VERSION 5.8 ;
BUSBITCHARS "[]" ;
DIVIDERCHAR "/" ;
UNITS
    DATABASE MICRONS 1000 ;
END UNITS

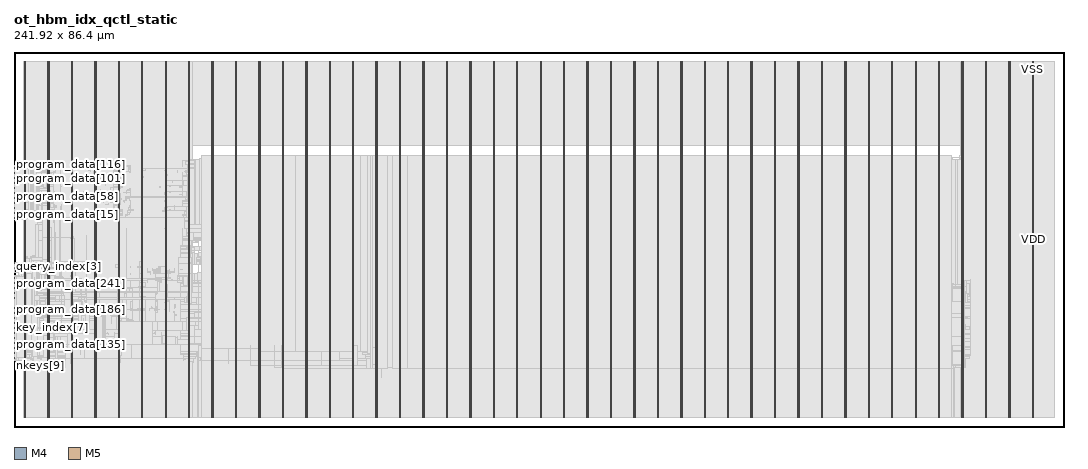
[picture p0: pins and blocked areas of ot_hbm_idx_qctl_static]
MACRO ot_hbm_idx_qctl_static
  FOREIGN ot_hbm_idx_qctl_static 0 0 ;
  CLASS BLOCK ;
  SIZE 241.92 BY 86.4 ;
  PIN clk_program
    DIRECTION INPUT ;
    USE SIGNAL ;
    PORT
      LAYER M4 ;
        RECT  0 21.936 0.084 21.96 ;
    END
  END clk_program
  PIN clk_program_mem
    DIRECTION INPUT ;
    USE SIGNAL ;
    PORT
      LAYER M4 ;
        RECT  0 22.032 0.084 22.056 ;
    END
  END clk_program_mem
  PIN fault
    DIRECTION OUTPUT ;
    USE SIGNAL ;
    PORT
      LAYER M4 ;
        RECT  0 22.128 0.084 22.152 ;
    END
  END fault
  PIN frame_start
    DIRECTION OUTPUT ;
    USE SIGNAL ;
    PORT
      LAYER M4 ;
        RECT  0 22.224 0.084 22.248 ;
    END
  END frame_start
  PIN key_index[0]
    DIRECTION OUTPUT ;
    USE SIGNAL ;
    PORT
      LAYER M4 ;
        RECT  0 22.32 0.084 22.344 ;
    END
  END key_index[0]
  PIN key_index[1]
    DIRECTION OUTPUT ;
    USE SIGNAL ;
    PORT
      LAYER M4 ;
        RECT  0 22.416 0.084 22.44 ;
    END
  END key_index[1]
  PIN key_index[2]
    DIRECTION OUTPUT ;
    USE SIGNAL ;
    PORT
      LAYER M4 ;
        RECT  0 22.512 0.084 22.536 ;
    END
  END key_index[2]
  PIN key_index[3]
    DIRECTION OUTPUT ;
    USE SIGNAL ;
    PORT
      LAYER M4 ;
        RECT  0 22.608 0.084 22.632 ;
    END
  END key_index[3]
  PIN key_index[4]
    DIRECTION OUTPUT ;
    USE SIGNAL ;
    PORT
      LAYER M4 ;
        RECT  0 22.704 0.084 22.728 ;
    END
  END key_index[4]
  PIN key_index[5]
    DIRECTION OUTPUT ;
    USE SIGNAL ;
    PORT
      LAYER M4 ;
        RECT  0 22.8 0.084 22.824 ;
    END
  END key_index[5]
  PIN key_index[6]
    DIRECTION OUTPUT ;
    USE SIGNAL ;
    PORT
      LAYER M4 ;
        RECT  0 22.896 0.084 22.92 ;
    END
  END key_index[6]
  PIN key_index[7]
    DIRECTION OUTPUT ;
    USE SIGNAL ;
    PORT
      LAYER M4 ;
        RECT  0 22.992 0.084 23.016 ;
    END
  END key_index[7]
  PIN key_slot
    DIRECTION OUTPUT ;
    USE SIGNAL ;
    PORT
      LAYER M4 ;
        RECT  0 23.088 0.084 23.112 ;
    END
  END key_slot
  PIN length[0]
    DIRECTION INPUT ;
    USE SIGNAL ;
    PORT
      LAYER M4 ;
        RECT  0 23.184 0.084 23.208 ;
    END
  END length[0]
  PIN length[10]
    DIRECTION INPUT ;
    USE SIGNAL ;
    PORT
      LAYER M4 ;
        RECT  0 24.144 0.084 24.168 ;
    END
  END length[10]
  PIN length[11]
    DIRECTION INPUT ;
    USE SIGNAL ;
    PORT
      LAYER M4 ;
        RECT  0 24.24 0.084 24.264 ;
    END
  END length[11]
  PIN length[1]
    DIRECTION INPUT ;
    USE SIGNAL ;
    PORT
      LAYER M4 ;
        RECT  0 23.28 0.084 23.304 ;
    END
  END length[1]
  PIN length[2]
    DIRECTION INPUT ;
    USE SIGNAL ;
    PORT
      LAYER M4 ;
        RECT  0 23.376 0.084 23.4 ;
    END
  END length[2]
  PIN length[3]
    DIRECTION INPUT ;
    USE SIGNAL ;
    PORT
      LAYER M4 ;
        RECT  0 23.472 0.084 23.496 ;
    END
  END length[3]
  PIN length[4]
    DIRECTION INPUT ;
    USE SIGNAL ;
    PORT
      LAYER M4 ;
        RECT  0 23.568 0.084 23.592 ;
    END
  END length[4]
  PIN length[5]
    DIRECTION INPUT ;
    USE SIGNAL ;
    PORT
      LAYER M4 ;
        RECT  0 23.664 0.084 23.688 ;
    END
  END length[5]
  PIN length[6]
    DIRECTION INPUT ;
    USE SIGNAL ;
    PORT
      LAYER M4 ;
        RECT  0 23.76 0.084 23.784 ;
    END
  END length[6]
  PIN length[7]
    DIRECTION INPUT ;
    USE SIGNAL ;
    PORT
      LAYER M4 ;
        RECT  0 23.856 0.084 23.88 ;
    END
  END length[7]
  PIN length[8]
    DIRECTION INPUT ;
    USE SIGNAL ;
    PORT
      LAYER M4 ;
        RECT  0 23.952 0.084 23.976 ;
    END
  END length[8]
  PIN length[9]
    DIRECTION INPUT ;
    USE SIGNAL ;
    PORT
      LAYER M4 ;
        RECT  0 24.048 0.084 24.072 ;
    END
  END length[9]
  PIN nkeys[0]
    DIRECTION INPUT ;
    USE SIGNAL ;
    PORT
      LAYER M4 ;
        RECT  0 24.336 0.084 24.36 ;
    END
  END nkeys[0]
  PIN nkeys[10]
    DIRECTION INPUT ;
    USE SIGNAL ;
    PORT
      LAYER M4 ;
        RECT  0 16.08 0.084 16.104 ;
    END
  END nkeys[10]
  PIN nkeys[11]
    DIRECTION INPUT ;
    USE SIGNAL ;
    PORT
      LAYER M4 ;
        RECT  0 16.176 0.084 16.2 ;
    END
  END nkeys[11]
  PIN nkeys[12]
    DIRECTION INPUT ;
    USE SIGNAL ;
    PORT
      LAYER M4 ;
        RECT  0 16.272 0.084 16.296 ;
    END
  END nkeys[12]
  PIN nkeys[13]
    DIRECTION INPUT ;
    USE SIGNAL ;
    PORT
      LAYER M4 ;
        RECT  0 16.368 0.084 16.392 ;
    END
  END nkeys[13]
  PIN nkeys[1]
    DIRECTION INPUT ;
    USE SIGNAL ;
    PORT
      LAYER M4 ;
        RECT  0 24.432 0.084 24.456 ;
    END
  END nkeys[1]
  PIN nkeys[2]
    DIRECTION INPUT ;
    USE SIGNAL ;
    PORT
      LAYER M4 ;
        RECT  0 24.528 0.084 24.552 ;
    END
  END nkeys[2]
  PIN nkeys[3]
    DIRECTION INPUT ;
    USE SIGNAL ;
    PORT
      LAYER M4 ;
        RECT  0 24.624 0.084 24.648 ;
    END
  END nkeys[3]
  PIN nkeys[4]
    DIRECTION INPUT ;
    USE SIGNAL ;
    PORT
      LAYER M4 ;
        RECT  0 24.72 0.084 24.744 ;
    END
  END nkeys[4]
  PIN nkeys[5]
    DIRECTION INPUT ;
    USE SIGNAL ;
    PORT
      LAYER M4 ;
        RECT  0 24.816 0.084 24.84 ;
    END
  END nkeys[5]
  PIN nkeys[6]
    DIRECTION INPUT ;
    USE SIGNAL ;
    PORT
      LAYER M4 ;
        RECT  0 24.912 0.084 24.936 ;
    END
  END nkeys[6]
  PIN nkeys[7]
    DIRECTION INPUT ;
    USE SIGNAL ;
    PORT
      LAYER M4 ;
        RECT  0 15.792 0.084 15.816 ;
    END
  END nkeys[7]
  PIN nkeys[8]
    DIRECTION INPUT ;
    USE SIGNAL ;
    PORT
      LAYER M4 ;
        RECT  0 15.888 0.084 15.912 ;
    END
  END nkeys[8]
  PIN nkeys[9]
    DIRECTION INPUT ;
    USE SIGNAL ;
    PORT
      LAYER M4 ;
        RECT  0 15.984 0.084 16.008 ;
    END
  END nkeys[9]
  PIN nq[0]
    DIRECTION OUTPUT ;
    USE SIGNAL ;
    PORT
      LAYER M4 ;
        RECT  0 16.464 0.084 16.488 ;
    END
  END nq[0]
  PIN nq[10]
    DIRECTION OUTPUT ;
    USE SIGNAL ;
    PORT
      LAYER M4 ;
        RECT  0 17.424 0.084 17.448 ;
    END
  END nq[10]
  PIN nq[11]
    DIRECTION OUTPUT ;
    USE SIGNAL ;
    PORT
      LAYER M4 ;
        RECT  0 17.52 0.084 17.544 ;
    END
  END nq[11]
  PIN nq[1]
    DIRECTION OUTPUT ;
    USE SIGNAL ;
    PORT
      LAYER M4 ;
        RECT  0 16.56 0.084 16.584 ;
    END
  END nq[1]
  PIN nq[2]
    DIRECTION OUTPUT ;
    USE SIGNAL ;
    PORT
      LAYER M4 ;
        RECT  0 16.656 0.084 16.68 ;
    END
  END nq[2]
  PIN nq[3]
    DIRECTION OUTPUT ;
    USE SIGNAL ;
    PORT
      LAYER M4 ;
        RECT  0 16.752 0.084 16.776 ;
    END
  END nq[3]
  PIN nq[4]
    DIRECTION OUTPUT ;
    USE SIGNAL ;
    PORT
      LAYER M4 ;
        RECT  0 16.848 0.084 16.872 ;
    END
  END nq[4]
  PIN nq[5]
    DIRECTION OUTPUT ;
    USE SIGNAL ;
    PORT
      LAYER M4 ;
        RECT  0 16.944 0.084 16.968 ;
    END
  END nq[5]
  PIN nq[6]
    DIRECTION OUTPUT ;
    USE SIGNAL ;
    PORT
      LAYER M4 ;
        RECT  0 17.04 0.084 17.064 ;
    END
  END nq[6]
  PIN nq[7]
    DIRECTION OUTPUT ;
    USE SIGNAL ;
    PORT
      LAYER M4 ;
        RECT  0 17.136 0.084 17.16 ;
    END
  END nq[7]
  PIN nq[8]
    DIRECTION OUTPUT ;
    USE SIGNAL ;
    PORT
      LAYER M4 ;
        RECT  0 17.232 0.084 17.256 ;
    END
  END nq[8]
  PIN nq[9]
    DIRECTION OUTPUT ;
    USE SIGNAL ;
    PORT
      LAYER M4 ;
        RECT  0 17.328 0.084 17.352 ;
    END
  END nq[9]
  PIN program_addr[0]
    DIRECTION INPUT ;
    USE SIGNAL ;
    PORT
      LAYER M4 ;
        RECT  0 17.616 0.084 17.64 ;
    END
  END program_addr[0]
  PIN program_addr[1]
    DIRECTION INPUT ;
    USE SIGNAL ;
    PORT
      LAYER M4 ;
        RECT  0 17.712 0.084 17.736 ;
    END
  END program_addr[1]
  PIN program_addr[2]
    DIRECTION INPUT ;
    USE SIGNAL ;
    PORT
      LAYER M4 ;
        RECT  0 17.808 0.084 17.832 ;
    END
  END program_addr[2]
  PIN program_addr[3]
    DIRECTION INPUT ;
    USE SIGNAL ;
    PORT
      LAYER M4 ;
        RECT  0 17.904 0.084 17.928 ;
    END
  END program_addr[3]
  PIN program_addr[4]
    DIRECTION INPUT ;
    USE SIGNAL ;
    PORT
      LAYER M4 ;
        RECT  0 18 0.084 18.024 ;
    END
  END program_addr[4]
  PIN program_addr[5]
    DIRECTION INPUT ;
    USE SIGNAL ;
    PORT
      LAYER M4 ;
        RECT  0 18.096 0.084 18.12 ;
    END
  END program_addr[5]
  PIN program_addr[6]
    DIRECTION INPUT ;
    USE SIGNAL ;
    PORT
      LAYER M4 ;
        RECT  0 18.192 0.084 18.216 ;
    END
  END program_addr[6]
  PIN program_addr[7]
    DIRECTION INPUT ;
    USE SIGNAL ;
    PORT
      LAYER M4 ;
        RECT  0 18.288 0.084 18.312 ;
    END
  END program_addr[7]
  PIN program_data[0]
    DIRECTION INPUT ;
    USE SIGNAL ;
    PORT
      LAYER M4 ;
        RECT  0 18.384 0.084 18.408 ;
    END
  END program_data[0]
  PIN program_data[100]
    DIRECTION INPUT ;
    USE SIGNAL ;
    PORT
      LAYER M4 ;
        RECT  0 57.168 0.084 57.192 ;
    END
  END program_data[100]
  PIN program_data[101]
    DIRECTION INPUT ;
    USE SIGNAL ;
    PORT
      LAYER M4 ;
        RECT  0 57.264 0.084 57.288 ;
    END
  END program_data[101]
  PIN program_data[102]
    DIRECTION INPUT ;
    USE SIGNAL ;
    PORT
      LAYER M4 ;
        RECT  0 57.36 0.084 57.384 ;
    END
  END program_data[102]
  PIN program_data[103]
    DIRECTION INPUT ;
    USE SIGNAL ;
    PORT
      LAYER M4 ;
        RECT  0 57.456 0.084 57.48 ;
    END
  END program_data[103]
  PIN program_data[104]
    DIRECTION INPUT ;
    USE SIGNAL ;
    PORT
      LAYER M4 ;
        RECT  0 57.552 0.084 57.576 ;
    END
  END program_data[104]
  PIN program_data[105]
    DIRECTION INPUT ;
    USE SIGNAL ;
    PORT
      LAYER M4 ;
        RECT  0 57.648 0.084 57.672 ;
    END
  END program_data[105]
  PIN program_data[106]
    DIRECTION INPUT ;
    USE SIGNAL ;
    PORT
      LAYER M4 ;
        RECT  0 57.744 0.084 57.768 ;
    END
  END program_data[106]
  PIN program_data[107]
    DIRECTION INPUT ;
    USE SIGNAL ;
    PORT
      LAYER M4 ;
        RECT  0 57.84 0.084 57.864 ;
    END
  END program_data[107]
  PIN program_data[108]
    DIRECTION INPUT ;
    USE SIGNAL ;
    PORT
      LAYER M4 ;
        RECT  0 57.936 0.084 57.96 ;
    END
  END program_data[108]
  PIN program_data[109]
    DIRECTION INPUT ;
    USE SIGNAL ;
    PORT
      LAYER M4 ;
        RECT  0 58.032 0.084 58.056 ;
    END
  END program_data[109]
  PIN program_data[10]
    DIRECTION INPUT ;
    USE SIGNAL ;
    PORT
      LAYER M4 ;
        RECT  0 48.528 0.084 48.552 ;
    END
  END program_data[10]
  PIN program_data[110]
    DIRECTION INPUT ;
    USE SIGNAL ;
    PORT
      LAYER M4 ;
        RECT  0 58.128 0.084 58.152 ;
    END
  END program_data[110]
  PIN program_data[111]
    DIRECTION INPUT ;
    USE SIGNAL ;
    PORT
      LAYER M4 ;
        RECT  0 58.224 0.084 58.248 ;
    END
  END program_data[111]
  PIN program_data[112]
    DIRECTION INPUT ;
    USE SIGNAL ;
    PORT
      LAYER M4 ;
        RECT  0 58.32 0.084 58.344 ;
    END
  END program_data[112]
  PIN program_data[113]
    DIRECTION INPUT ;
    USE SIGNAL ;
    PORT
      LAYER M4 ;
        RECT  0 58.416 0.084 58.44 ;
    END
  END program_data[113]
  PIN program_data[114]
    DIRECTION INPUT ;
    USE SIGNAL ;
    PORT
      LAYER M4 ;
        RECT  0 58.512 0.084 58.536 ;
    END
  END program_data[114]
  PIN program_data[115]
    DIRECTION INPUT ;
    USE SIGNAL ;
    PORT
      LAYER M4 ;
        RECT  0 58.608 0.084 58.632 ;
    END
  END program_data[115]
  PIN program_data[116]
    DIRECTION INPUT ;
    USE SIGNAL ;
    PORT
      LAYER M4 ;
        RECT  0 58.704 0.084 58.728 ;
    END
  END program_data[116]
  PIN program_data[117]
    DIRECTION INPUT ;
    USE SIGNAL ;
    PORT
      LAYER M4 ;
        RECT  0 58.8 0.084 58.824 ;
    END
  END program_data[117]
  PIN program_data[118]
    DIRECTION INPUT ;
    USE SIGNAL ;
    PORT
      LAYER M4 ;
        RECT  0 58.896 0.084 58.92 ;
    END
  END program_data[118]
  PIN program_data[119]
    DIRECTION INPUT ;
    USE SIGNAL ;
    PORT
      LAYER M4 ;
        RECT  0 58.992 0.084 59.016 ;
    END
  END program_data[119]
  PIN program_data[11]
    DIRECTION INPUT ;
    USE SIGNAL ;
    PORT
      LAYER M4 ;
        RECT  0 48.624 0.084 48.648 ;
    END
  END program_data[11]
  PIN program_data[120]
    DIRECTION INPUT ;
    USE SIGNAL ;
    PORT
      LAYER M4 ;
        RECT  0 59.088 0.084 59.112 ;
    END
  END program_data[120]
  PIN program_data[121]
    DIRECTION INPUT ;
    USE SIGNAL ;
    PORT
      LAYER M4 ;
        RECT  0 59.184 0.084 59.208 ;
    END
  END program_data[121]
  PIN program_data[122]
    DIRECTION INPUT ;
    USE SIGNAL ;
    PORT
      LAYER M4 ;
        RECT  0 59.28 0.084 59.304 ;
    END
  END program_data[122]
  PIN program_data[123]
    DIRECTION INPUT ;
    USE SIGNAL ;
    PORT
      LAYER M4 ;
        RECT  0 59.376 0.084 59.4 ;
    END
  END program_data[123]
  PIN program_data[124]
    DIRECTION INPUT ;
    USE SIGNAL ;
    PORT
      LAYER M4 ;
        RECT  0 59.472 0.084 59.496 ;
    END
  END program_data[124]
  PIN program_data[125]
    DIRECTION INPUT ;
    USE SIGNAL ;
    PORT
      LAYER M4 ;
        RECT  0 59.568 0.084 59.592 ;
    END
  END program_data[125]
  PIN program_data[126]
    DIRECTION INPUT ;
    USE SIGNAL ;
    PORT
      LAYER M4 ;
        RECT  0 59.664 0.084 59.688 ;
    END
  END program_data[126]
  PIN program_data[127]
    DIRECTION INPUT ;
    USE SIGNAL ;
    PORT
      LAYER M4 ;
        RECT  0 59.76 0.084 59.784 ;
    END
  END program_data[127]
  PIN program_data[128]
    DIRECTION INPUT ;
    USE SIGNAL ;
    PORT
      LAYER M4 ;
        RECT  0 59.856 0.084 59.88 ;
    END
  END program_data[128]
  PIN program_data[129]
    DIRECTION INPUT ;
    USE SIGNAL ;
    PORT
      LAYER M4 ;
        RECT  0 59.952 0.084 59.976 ;
    END
  END program_data[129]
  PIN program_data[12]
    DIRECTION INPUT ;
    USE SIGNAL ;
    PORT
      LAYER M4 ;
        RECT  0 48.72 0.084 48.744 ;
    END
  END program_data[12]
  PIN program_data[130]
    DIRECTION INPUT ;
    USE SIGNAL ;
    PORT
      LAYER M4 ;
        RECT  0 60.048 0.084 60.072 ;
    END
  END program_data[130]
  PIN program_data[131]
    DIRECTION INPUT ;
    USE SIGNAL ;
    PORT
      LAYER M4 ;
        RECT  0 60.144 0.084 60.168 ;
    END
  END program_data[131]
  PIN program_data[132]
    DIRECTION INPUT ;
    USE SIGNAL ;
    PORT
      LAYER M4 ;
        RECT  0 60.24 0.084 60.264 ;
    END
  END program_data[132]
  PIN program_data[133]
    DIRECTION INPUT ;
    USE SIGNAL ;
    PORT
      LAYER M4 ;
        RECT  0 18.864 0.084 18.888 ;
    END
  END program_data[133]
  PIN program_data[134]
    DIRECTION INPUT ;
    USE SIGNAL ;
    PORT
      LAYER M4 ;
        RECT  0 18.96 0.084 18.984 ;
    END
  END program_data[134]
  PIN program_data[135]
    DIRECTION INPUT ;
    USE SIGNAL ;
    PORT
      LAYER M4 ;
        RECT  0 19.056 0.084 19.08 ;
    END
  END program_data[135]
  PIN program_data[136]
    DIRECTION INPUT ;
    USE SIGNAL ;
    PORT
      LAYER M4 ;
        RECT  0 19.152 0.084 19.176 ;
    END
  END program_data[136]
  PIN program_data[137]
    DIRECTION INPUT ;
    USE SIGNAL ;
    PORT
      LAYER M4 ;
        RECT  0 19.248 0.084 19.272 ;
    END
  END program_data[137]
  PIN program_data[138]
    DIRECTION INPUT ;
    USE SIGNAL ;
    PORT
      LAYER M4 ;
        RECT  0 19.344 0.084 19.368 ;
    END
  END program_data[138]
  PIN program_data[139]
    DIRECTION INPUT ;
    USE SIGNAL ;
    PORT
      LAYER M4 ;
        RECT  0 19.44 0.084 19.464 ;
    END
  END program_data[139]
  PIN program_data[13]
    DIRECTION INPUT ;
    USE SIGNAL ;
    PORT
      LAYER M4 ;
        RECT  0 48.816 0.084 48.84 ;
    END
  END program_data[13]
  PIN program_data[140]
    DIRECTION INPUT ;
    USE SIGNAL ;
    PORT
      LAYER M4 ;
        RECT  0 19.536 0.084 19.56 ;
    END
  END program_data[140]
  PIN program_data[141]
    DIRECTION INPUT ;
    USE SIGNAL ;
    PORT
      LAYER M4 ;
        RECT  0 19.632 0.084 19.656 ;
    END
  END program_data[141]
  PIN program_data[142]
    DIRECTION INPUT ;
    USE SIGNAL ;
    PORT
      LAYER M4 ;
        RECT  0 19.728 0.084 19.752 ;
    END
  END program_data[142]
  PIN program_data[143]
    DIRECTION INPUT ;
    USE SIGNAL ;
    PORT
      LAYER M4 ;
        RECT  0 19.824 0.084 19.848 ;
    END
  END program_data[143]
  PIN program_data[144]
    DIRECTION INPUT ;
    USE SIGNAL ;
    PORT
      LAYER M4 ;
        RECT  0 19.92 0.084 19.944 ;
    END
  END program_data[144]
  PIN program_data[145]
    DIRECTION INPUT ;
    USE SIGNAL ;
    PORT
      LAYER M4 ;
        RECT  0 20.016 0.084 20.04 ;
    END
  END program_data[145]
  PIN program_data[146]
    DIRECTION INPUT ;
    USE SIGNAL ;
    PORT
      LAYER M4 ;
        RECT  0 20.112 0.084 20.136 ;
    END
  END program_data[146]
  PIN program_data[147]
    DIRECTION INPUT ;
    USE SIGNAL ;
    PORT
      LAYER M4 ;
        RECT  0 20.208 0.084 20.232 ;
    END
  END program_data[147]
  PIN program_data[148]
    DIRECTION INPUT ;
    USE SIGNAL ;
    PORT
      LAYER M4 ;
        RECT  0 20.304 0.084 20.328 ;
    END
  END program_data[148]
  PIN program_data[149]
    DIRECTION INPUT ;
    USE SIGNAL ;
    PORT
      LAYER M4 ;
        RECT  0 20.4 0.084 20.424 ;
    END
  END program_data[149]
  PIN program_data[14]
    DIRECTION INPUT ;
    USE SIGNAL ;
    PORT
      LAYER M4 ;
        RECT  0 48.912 0.084 48.936 ;
    END
  END program_data[14]
  PIN program_data[150]
    DIRECTION INPUT ;
    USE SIGNAL ;
    PORT
      LAYER M4 ;
        RECT  0 20.496 0.084 20.52 ;
    END
  END program_data[150]
  PIN program_data[151]
    DIRECTION INPUT ;
    USE SIGNAL ;
    PORT
      LAYER M4 ;
        RECT  0 20.592 0.084 20.616 ;
    END
  END program_data[151]
  PIN program_data[152]
    DIRECTION INPUT ;
    USE SIGNAL ;
    PORT
      LAYER M4 ;
        RECT  0 20.688 0.084 20.712 ;
    END
  END program_data[152]
  PIN program_data[153]
    DIRECTION INPUT ;
    USE SIGNAL ;
    PORT
      LAYER M4 ;
        RECT  0 20.784 0.084 20.808 ;
    END
  END program_data[153]
  PIN program_data[154]
    DIRECTION INPUT ;
    USE SIGNAL ;
    PORT
      LAYER M4 ;
        RECT  0 20.88 0.084 20.904 ;
    END
  END program_data[154]
  PIN program_data[155]
    DIRECTION INPUT ;
    USE SIGNAL ;
    PORT
      LAYER M4 ;
        RECT  0 20.976 0.084 21 ;
    END
  END program_data[155]
  PIN program_data[156]
    DIRECTION INPUT ;
    USE SIGNAL ;
    PORT
      LAYER M4 ;
        RECT  0 21.072 0.084 21.096 ;
    END
  END program_data[156]
  PIN program_data[157]
    DIRECTION INPUT ;
    USE SIGNAL ;
    PORT
      LAYER M4 ;
        RECT  0 21.168 0.084 21.192 ;
    END
  END program_data[157]
  PIN program_data[158]
    DIRECTION INPUT ;
    USE SIGNAL ;
    PORT
      LAYER M4 ;
        RECT  0 21.264 0.084 21.288 ;
    END
  END program_data[158]
  PIN program_data[159]
    DIRECTION INPUT ;
    USE SIGNAL ;
    PORT
      LAYER M4 ;
        RECT  0 21.36 0.084 21.384 ;
    END
  END program_data[159]
  PIN program_data[15]
    DIRECTION INPUT ;
    USE SIGNAL ;
    PORT
      LAYER M4 ;
        RECT  0 49.008 0.084 49.032 ;
    END
  END program_data[15]
  PIN program_data[160]
    DIRECTION INPUT ;
    USE SIGNAL ;
    PORT
      LAYER M4 ;
        RECT  0 21.456 0.084 21.48 ;
    END
  END program_data[160]
  PIN program_data[161]
    DIRECTION INPUT ;
    USE SIGNAL ;
    PORT
      LAYER M4 ;
        RECT  0 21.552 0.084 21.576 ;
    END
  END program_data[161]
  PIN program_data[162]
    DIRECTION INPUT ;
    USE SIGNAL ;
    PORT
      LAYER M4 ;
        RECT  0 21.648 0.084 21.672 ;
    END
  END program_data[162]
  PIN program_data[163]
    DIRECTION INPUT ;
    USE SIGNAL ;
    PORT
      LAYER M4 ;
        RECT  0 21.744 0.084 21.768 ;
    END
  END program_data[163]
  PIN program_data[164]
    DIRECTION INPUT ;
    USE SIGNAL ;
    PORT
      LAYER M4 ;
        RECT  0 21.84 0.084 21.864 ;
    END
  END program_data[164]
  PIN program_data[165]
    DIRECTION INPUT ;
    USE SIGNAL ;
    PORT
      LAYER M4 ;
        RECT  0 25.008 0.084 25.032 ;
    END
  END program_data[165]
  PIN program_data[166]
    DIRECTION INPUT ;
    USE SIGNAL ;
    PORT
      LAYER M4 ;
        RECT  0 25.104 0.084 25.128 ;
    END
  END program_data[166]
  PIN program_data[167]
    DIRECTION INPUT ;
    USE SIGNAL ;
    PORT
      LAYER M4 ;
        RECT  0 25.2 0.084 25.224 ;
    END
  END program_data[167]
  PIN program_data[168]
    DIRECTION INPUT ;
    USE SIGNAL ;
    PORT
      LAYER M4 ;
        RECT  0 25.296 0.084 25.32 ;
    END
  END program_data[168]
  PIN program_data[169]
    DIRECTION INPUT ;
    USE SIGNAL ;
    PORT
      LAYER M4 ;
        RECT  0 25.392 0.084 25.416 ;
    END
  END program_data[169]
  PIN program_data[16]
    DIRECTION INPUT ;
    USE SIGNAL ;
    PORT
      LAYER M4 ;
        RECT  0 49.104 0.084 49.128 ;
    END
  END program_data[16]
  PIN program_data[170]
    DIRECTION INPUT ;
    USE SIGNAL ;
    PORT
      LAYER M4 ;
        RECT  0 25.488 0.084 25.512 ;
    END
  END program_data[170]
  PIN program_data[171]
    DIRECTION INPUT ;
    USE SIGNAL ;
    PORT
      LAYER M4 ;
        RECT  0 25.584 0.084 25.608 ;
    END
  END program_data[171]
  PIN program_data[172]
    DIRECTION INPUT ;
    USE SIGNAL ;
    PORT
      LAYER M4 ;
        RECT  0 25.68 0.084 25.704 ;
    END
  END program_data[172]
  PIN program_data[173]
    DIRECTION INPUT ;
    USE SIGNAL ;
    PORT
      LAYER M4 ;
        RECT  0 25.776 0.084 25.8 ;
    END
  END program_data[173]
  PIN program_data[174]
    DIRECTION INPUT ;
    USE SIGNAL ;
    PORT
      LAYER M4 ;
        RECT  0 25.872 0.084 25.896 ;
    END
  END program_data[174]
  PIN program_data[175]
    DIRECTION INPUT ;
    USE SIGNAL ;
    PORT
      LAYER M4 ;
        RECT  0 25.968 0.084 25.992 ;
    END
  END program_data[175]
  PIN program_data[176]
    DIRECTION INPUT ;
    USE SIGNAL ;
    PORT
      LAYER M4 ;
        RECT  0 26.064 0.084 26.088 ;
    END
  END program_data[176]
  PIN program_data[177]
    DIRECTION INPUT ;
    USE SIGNAL ;
    PORT
      LAYER M4 ;
        RECT  0 26.16 0.084 26.184 ;
    END
  END program_data[177]
  PIN program_data[178]
    DIRECTION INPUT ;
    USE SIGNAL ;
    PORT
      LAYER M4 ;
        RECT  0 26.256 0.084 26.28 ;
    END
  END program_data[178]
  PIN program_data[179]
    DIRECTION INPUT ;
    USE SIGNAL ;
    PORT
      LAYER M4 ;
        RECT  0 26.352 0.084 26.376 ;
    END
  END program_data[179]
  PIN program_data[17]
    DIRECTION INPUT ;
    USE SIGNAL ;
    PORT
      LAYER M4 ;
        RECT  0 49.2 0.084 49.224 ;
    END
  END program_data[17]
  PIN program_data[180]
    DIRECTION INPUT ;
    USE SIGNAL ;
    PORT
      LAYER M4 ;
        RECT  0 26.448 0.084 26.472 ;
    END
  END program_data[180]
  PIN program_data[181]
    DIRECTION INPUT ;
    USE SIGNAL ;
    PORT
      LAYER M4 ;
        RECT  0 26.544 0.084 26.568 ;
    END
  END program_data[181]
  PIN program_data[182]
    DIRECTION INPUT ;
    USE SIGNAL ;
    PORT
      LAYER M4 ;
        RECT  0 26.64 0.084 26.664 ;
    END
  END program_data[182]
  PIN program_data[183]
    DIRECTION INPUT ;
    USE SIGNAL ;
    PORT
      LAYER M4 ;
        RECT  0 26.736 0.084 26.76 ;
    END
  END program_data[183]
  PIN program_data[184]
    DIRECTION INPUT ;
    USE SIGNAL ;
    PORT
      LAYER M4 ;
        RECT  0 26.832 0.084 26.856 ;
    END
  END program_data[184]
  PIN program_data[185]
    DIRECTION INPUT ;
    USE SIGNAL ;
    PORT
      LAYER M4 ;
        RECT  0 26.928 0.084 26.952 ;
    END
  END program_data[185]
  PIN program_data[186]
    DIRECTION INPUT ;
    USE SIGNAL ;
    PORT
      LAYER M4 ;
        RECT  0 27.024 0.084 27.048 ;
    END
  END program_data[186]
  PIN program_data[187]
    DIRECTION INPUT ;
    USE SIGNAL ;
    PORT
      LAYER M4 ;
        RECT  0 27.12 0.084 27.144 ;
    END
  END program_data[187]
  PIN program_data[188]
    DIRECTION INPUT ;
    USE SIGNAL ;
    PORT
      LAYER M4 ;
        RECT  0 27.216 0.084 27.24 ;
    END
  END program_data[188]
  PIN program_data[189]
    DIRECTION INPUT ;
    USE SIGNAL ;
    PORT
      LAYER M4 ;
        RECT  0 27.312 0.084 27.336 ;
    END
  END program_data[189]
  PIN program_data[18]
    DIRECTION INPUT ;
    USE SIGNAL ;
    PORT
      LAYER M4 ;
        RECT  0 49.296 0.084 49.32 ;
    END
  END program_data[18]
  PIN program_data[190]
    DIRECTION INPUT ;
    USE SIGNAL ;
    PORT
      LAYER M4 ;
        RECT  0 27.408 0.084 27.432 ;
    END
  END program_data[190]
  PIN program_data[191]
    DIRECTION INPUT ;
    USE SIGNAL ;
    PORT
      LAYER M4 ;
        RECT  0 27.504 0.084 27.528 ;
    END
  END program_data[191]
  PIN program_data[192]
    DIRECTION INPUT ;
    USE SIGNAL ;
    PORT
      LAYER M4 ;
        RECT  0 27.6 0.084 27.624 ;
    END
  END program_data[192]
  PIN program_data[193]
    DIRECTION INPUT ;
    USE SIGNAL ;
    PORT
      LAYER M4 ;
        RECT  0 27.696 0.084 27.72 ;
    END
  END program_data[193]
  PIN program_data[194]
    DIRECTION INPUT ;
    USE SIGNAL ;
    PORT
      LAYER M4 ;
        RECT  0 27.792 0.084 27.816 ;
    END
  END program_data[194]
  PIN program_data[195]
    DIRECTION INPUT ;
    USE SIGNAL ;
    PORT
      LAYER M4 ;
        RECT  0 27.888 0.084 27.912 ;
    END
  END program_data[195]
  PIN program_data[196]
    DIRECTION INPUT ;
    USE SIGNAL ;
    PORT
      LAYER M4 ;
        RECT  0 27.984 0.084 28.008 ;
    END
  END program_data[196]
  PIN program_data[197]
    DIRECTION INPUT ;
    USE SIGNAL ;
    PORT
      LAYER M4 ;
        RECT  0 28.848 0.084 28.872 ;
    END
  END program_data[197]
  PIN program_data[198]
    DIRECTION INPUT ;
    USE SIGNAL ;
    PORT
      LAYER M4 ;
        RECT  0 28.944 0.084 28.968 ;
    END
  END program_data[198]
  PIN program_data[199]
    DIRECTION INPUT ;
    USE SIGNAL ;
    PORT
      LAYER M4 ;
        RECT  0 29.04 0.084 29.064 ;
    END
  END program_data[199]
  PIN program_data[19]
    DIRECTION INPUT ;
    USE SIGNAL ;
    PORT
      LAYER M4 ;
        RECT  0 49.392 0.084 49.416 ;
    END
  END program_data[19]
  PIN program_data[1]
    DIRECTION INPUT ;
    USE SIGNAL ;
    PORT
      LAYER M4 ;
        RECT  0 18.48 0.084 18.504 ;
    END
  END program_data[1]
  PIN program_data[200]
    DIRECTION INPUT ;
    USE SIGNAL ;
    PORT
      LAYER M4 ;
        RECT  0 29.136 0.084 29.16 ;
    END
  END program_data[200]
  PIN program_data[201]
    DIRECTION INPUT ;
    USE SIGNAL ;
    PORT
      LAYER M4 ;
        RECT  0 29.232 0.084 29.256 ;
    END
  END program_data[201]
  PIN program_data[202]
    DIRECTION INPUT ;
    USE SIGNAL ;
    PORT
      LAYER M4 ;
        RECT  0 29.328 0.084 29.352 ;
    END
  END program_data[202]
  PIN program_data[203]
    DIRECTION INPUT ;
    USE SIGNAL ;
    PORT
      LAYER M4 ;
        RECT  0 29.424 0.084 29.448 ;
    END
  END program_data[203]
  PIN program_data[204]
    DIRECTION INPUT ;
    USE SIGNAL ;
    PORT
      LAYER M4 ;
        RECT  0 29.52 0.084 29.544 ;
    END
  END program_data[204]
  PIN program_data[205]
    DIRECTION INPUT ;
    USE SIGNAL ;
    PORT
      LAYER M4 ;
        RECT  0 29.616 0.084 29.64 ;
    END
  END program_data[205]
  PIN program_data[206]
    DIRECTION INPUT ;
    USE SIGNAL ;
    PORT
      LAYER M4 ;
        RECT  0 29.712 0.084 29.736 ;
    END
  END program_data[206]
  PIN program_data[207]
    DIRECTION INPUT ;
    USE SIGNAL ;
    PORT
      LAYER M4 ;
        RECT  0 29.808 0.084 29.832 ;
    END
  END program_data[207]
  PIN program_data[208]
    DIRECTION INPUT ;
    USE SIGNAL ;
    PORT
      LAYER M4 ;
        RECT  0 29.904 0.084 29.928 ;
    END
  END program_data[208]
  PIN program_data[209]
    DIRECTION INPUT ;
    USE SIGNAL ;
    PORT
      LAYER M4 ;
        RECT  0 30 0.084 30.024 ;
    END
  END program_data[209]
  PIN program_data[20]
    DIRECTION INPUT ;
    USE SIGNAL ;
    PORT
      LAYER M4 ;
        RECT  0 49.488 0.084 49.512 ;
    END
  END program_data[20]
  PIN program_data[210]
    DIRECTION INPUT ;
    USE SIGNAL ;
    PORT
      LAYER M4 ;
        RECT  0 30.096 0.084 30.12 ;
    END
  END program_data[210]
  PIN program_data[211]
    DIRECTION INPUT ;
    USE SIGNAL ;
    PORT
      LAYER M4 ;
        RECT  0 30.192 0.084 30.216 ;
    END
  END program_data[211]
  PIN program_data[212]
    DIRECTION INPUT ;
    USE SIGNAL ;
    PORT
      LAYER M4 ;
        RECT  0 30.288 0.084 30.312 ;
    END
  END program_data[212]
  PIN program_data[213]
    DIRECTION INPUT ;
    USE SIGNAL ;
    PORT
      LAYER M4 ;
        RECT  0 30.384 0.084 30.408 ;
    END
  END program_data[213]
  PIN program_data[214]
    DIRECTION INPUT ;
    USE SIGNAL ;
    PORT
      LAYER M4 ;
        RECT  0 30.48 0.084 30.504 ;
    END
  END program_data[214]
  PIN program_data[215]
    DIRECTION INPUT ;
    USE SIGNAL ;
    PORT
      LAYER M4 ;
        RECT  0 30.576 0.084 30.6 ;
    END
  END program_data[215]
  PIN program_data[216]
    DIRECTION INPUT ;
    USE SIGNAL ;
    PORT
      LAYER M4 ;
        RECT  0 30.672 0.084 30.696 ;
    END
  END program_data[216]
  PIN program_data[217]
    DIRECTION INPUT ;
    USE SIGNAL ;
    PORT
      LAYER M4 ;
        RECT  0 30.768 0.084 30.792 ;
    END
  END program_data[217]
  PIN program_data[218]
    DIRECTION INPUT ;
    USE SIGNAL ;
    PORT
      LAYER M4 ;
        RECT  0 30.864 0.084 30.888 ;
    END
  END program_data[218]
  PIN program_data[219]
    DIRECTION INPUT ;
    USE SIGNAL ;
    PORT
      LAYER M4 ;
        RECT  0 30.96 0.084 30.984 ;
    END
  END program_data[219]
  PIN program_data[21]
    DIRECTION INPUT ;
    USE SIGNAL ;
    PORT
      LAYER M4 ;
        RECT  0 49.584 0.084 49.608 ;
    END
  END program_data[21]
  PIN program_data[220]
    DIRECTION INPUT ;
    USE SIGNAL ;
    PORT
      LAYER M4 ;
        RECT  0 31.056 0.084 31.08 ;
    END
  END program_data[220]
  PIN program_data[221]
    DIRECTION INPUT ;
    USE SIGNAL ;
    PORT
      LAYER M4 ;
        RECT  0 31.152 0.084 31.176 ;
    END
  END program_data[221]
  PIN program_data[222]
    DIRECTION INPUT ;
    USE SIGNAL ;
    PORT
      LAYER M4 ;
        RECT  0 31.248 0.084 31.272 ;
    END
  END program_data[222]
  PIN program_data[223]
    DIRECTION INPUT ;
    USE SIGNAL ;
    PORT
      LAYER M4 ;
        RECT  0 31.344 0.084 31.368 ;
    END
  END program_data[223]
  PIN program_data[224]
    DIRECTION INPUT ;
    USE SIGNAL ;
    PORT
      LAYER M4 ;
        RECT  0 31.44 0.084 31.464 ;
    END
  END program_data[224]
  PIN program_data[225]
    DIRECTION INPUT ;
    USE SIGNAL ;
    PORT
      LAYER M4 ;
        RECT  0 31.536 0.084 31.56 ;
    END
  END program_data[225]
  PIN program_data[226]
    DIRECTION INPUT ;
    USE SIGNAL ;
    PORT
      LAYER M4 ;
        RECT  0 31.632 0.084 31.656 ;
    END
  END program_data[226]
  PIN program_data[227]
    DIRECTION INPUT ;
    USE SIGNAL ;
    PORT
      LAYER M4 ;
        RECT  0 31.728 0.084 31.752 ;
    END
  END program_data[227]
  PIN program_data[228]
    DIRECTION INPUT ;
    USE SIGNAL ;
    PORT
      LAYER M4 ;
        RECT  0 31.824 0.084 31.848 ;
    END
  END program_data[228]
  PIN program_data[229]
    DIRECTION INPUT ;
    USE SIGNAL ;
    PORT
      LAYER M4 ;
        RECT  0 31.92 0.084 31.944 ;
    END
  END program_data[229]
  PIN program_data[22]
    DIRECTION INPUT ;
    USE SIGNAL ;
    PORT
      LAYER M4 ;
        RECT  0 49.68 0.084 49.704 ;
    END
  END program_data[22]
  PIN program_data[230]
    DIRECTION INPUT ;
    USE SIGNAL ;
    PORT
      LAYER M4 ;
        RECT  0 32.016 0.084 32.04 ;
    END
  END program_data[230]
  PIN program_data[231]
    DIRECTION INPUT ;
    USE SIGNAL ;
    PORT
      LAYER M4 ;
        RECT  0 32.112 0.084 32.136 ;
    END
  END program_data[231]
  PIN program_data[232]
    DIRECTION INPUT ;
    USE SIGNAL ;
    PORT
      LAYER M4 ;
        RECT  0 32.208 0.084 32.232 ;
    END
  END program_data[232]
  PIN program_data[233]
    DIRECTION INPUT ;
    USE SIGNAL ;
    PORT
      LAYER M4 ;
        RECT  0 32.304 0.084 32.328 ;
    END
  END program_data[233]
  PIN program_data[234]
    DIRECTION INPUT ;
    USE SIGNAL ;
    PORT
      LAYER M4 ;
        RECT  0 32.4 0.084 32.424 ;
    END
  END program_data[234]
  PIN program_data[235]
    DIRECTION INPUT ;
    USE SIGNAL ;
    PORT
      LAYER M4 ;
        RECT  0 32.496 0.084 32.52 ;
    END
  END program_data[235]
  PIN program_data[236]
    DIRECTION INPUT ;
    USE SIGNAL ;
    PORT
      LAYER M4 ;
        RECT  0 32.592 0.084 32.616 ;
    END
  END program_data[236]
  PIN program_data[237]
    DIRECTION INPUT ;
    USE SIGNAL ;
    PORT
      LAYER M4 ;
        RECT  0 32.688 0.084 32.712 ;
    END
  END program_data[237]
  PIN program_data[238]
    DIRECTION INPUT ;
    USE SIGNAL ;
    PORT
      LAYER M4 ;
        RECT  0 32.784 0.084 32.808 ;
    END
  END program_data[238]
  PIN program_data[239]
    DIRECTION INPUT ;
    USE SIGNAL ;
    PORT
      LAYER M4 ;
        RECT  0 32.88 0.084 32.904 ;
    END
  END program_data[239]
  PIN program_data[23]
    DIRECTION INPUT ;
    USE SIGNAL ;
    PORT
      LAYER M4 ;
        RECT  0 49.776 0.084 49.8 ;
    END
  END program_data[23]
  PIN program_data[240]
    DIRECTION INPUT ;
    USE SIGNAL ;
    PORT
      LAYER M4 ;
        RECT  0 32.976 0.084 33 ;
    END
  END program_data[240]
  PIN program_data[241]
    DIRECTION INPUT ;
    USE SIGNAL ;
    PORT
      LAYER M4 ;
        RECT  0 33.072 0.084 33.096 ;
    END
  END program_data[241]
  PIN program_data[242]
    DIRECTION INPUT ;
    USE SIGNAL ;
    PORT
      LAYER M4 ;
        RECT  0 33.168 0.084 33.192 ;
    END
  END program_data[242]
  PIN program_data[243]
    DIRECTION INPUT ;
    USE SIGNAL ;
    PORT
      LAYER M4 ;
        RECT  0 33.264 0.084 33.288 ;
    END
  END program_data[243]
  PIN program_data[244]
    DIRECTION INPUT ;
    USE SIGNAL ;
    PORT
      LAYER M4 ;
        RECT  0 33.36 0.084 33.384 ;
    END
  END program_data[244]
  PIN program_data[245]
    DIRECTION INPUT ;
    USE SIGNAL ;
    PORT
      LAYER M4 ;
        RECT  0 33.456 0.084 33.48 ;
    END
  END program_data[245]
  PIN program_data[246]
    DIRECTION INPUT ;
    USE SIGNAL ;
    PORT
      LAYER M4 ;
        RECT  0 33.552 0.084 33.576 ;
    END
  END program_data[246]
  PIN program_data[247]
    DIRECTION INPUT ;
    USE SIGNAL ;
    PORT
      LAYER M4 ;
        RECT  0 33.648 0.084 33.672 ;
    END
  END program_data[247]
  PIN program_data[248]
    DIRECTION INPUT ;
    USE SIGNAL ;
    PORT
      LAYER M4 ;
        RECT  0 33.744 0.084 33.768 ;
    END
  END program_data[248]
  PIN program_data[249]
    DIRECTION INPUT ;
    USE SIGNAL ;
    PORT
      LAYER M4 ;
        RECT  0 33.84 0.084 33.864 ;
    END
  END program_data[249]
  PIN program_data[24]
    DIRECTION INPUT ;
    USE SIGNAL ;
    PORT
      LAYER M4 ;
        RECT  0 49.872 0.084 49.896 ;
    END
  END program_data[24]
  PIN program_data[250]
    DIRECTION INPUT ;
    USE SIGNAL ;
    PORT
      LAYER M4 ;
        RECT  0 33.936 0.084 33.96 ;
    END
  END program_data[250]
  PIN program_data[251]
    DIRECTION INPUT ;
    USE SIGNAL ;
    PORT
      LAYER M4 ;
        RECT  0 34.032 0.084 34.056 ;
    END
  END program_data[251]
  PIN program_data[252]
    DIRECTION INPUT ;
    USE SIGNAL ;
    PORT
      LAYER M4 ;
        RECT  0 34.128 0.084 34.152 ;
    END
  END program_data[252]
  PIN program_data[253]
    DIRECTION INPUT ;
    USE SIGNAL ;
    PORT
      LAYER M4 ;
        RECT  0 34.224 0.084 34.248 ;
    END
  END program_data[253]
  PIN program_data[254]
    DIRECTION INPUT ;
    USE SIGNAL ;
    PORT
      LAYER M4 ;
        RECT  0 34.32 0.084 34.344 ;
    END
  END program_data[254]
  PIN program_data[255]
    DIRECTION INPUT ;
    USE SIGNAL ;
    PORT
      LAYER M4 ;
        RECT  0 34.416 0.084 34.44 ;
    END
  END program_data[255]
  PIN program_data[25]
    DIRECTION INPUT ;
    USE SIGNAL ;
    PORT
      LAYER M4 ;
        RECT  0 49.968 0.084 49.992 ;
    END
  END program_data[25]
  PIN program_data[26]
    DIRECTION INPUT ;
    USE SIGNAL ;
    PORT
      LAYER M4 ;
        RECT  0 50.064 0.084 50.088 ;
    END
  END program_data[26]
  PIN program_data[27]
    DIRECTION INPUT ;
    USE SIGNAL ;
    PORT
      LAYER M4 ;
        RECT  0 50.16 0.084 50.184 ;
    END
  END program_data[27]
  PIN program_data[28]
    DIRECTION INPUT ;
    USE SIGNAL ;
    PORT
      LAYER M4 ;
        RECT  0 50.256 0.084 50.28 ;
    END
  END program_data[28]
  PIN program_data[29]
    DIRECTION INPUT ;
    USE SIGNAL ;
    PORT
      LAYER M4 ;
        RECT  0 50.352 0.084 50.376 ;
    END
  END program_data[29]
  PIN program_data[2]
    DIRECTION INPUT ;
    USE SIGNAL ;
    PORT
      LAYER M4 ;
        RECT  0 18.576 0.084 18.6 ;
    END
  END program_data[2]
  PIN program_data[30]
    DIRECTION INPUT ;
    USE SIGNAL ;
    PORT
      LAYER M4 ;
        RECT  0 50.448 0.084 50.472 ;
    END
  END program_data[30]
  PIN program_data[31]
    DIRECTION INPUT ;
    USE SIGNAL ;
    PORT
      LAYER M4 ;
        RECT  0 50.544 0.084 50.568 ;
    END
  END program_data[31]
  PIN program_data[32]
    DIRECTION INPUT ;
    USE SIGNAL ;
    PORT
      LAYER M4 ;
        RECT  0 50.64 0.084 50.664 ;
    END
  END program_data[32]
  PIN program_data[33]
    DIRECTION INPUT ;
    USE SIGNAL ;
    PORT
      LAYER M4 ;
        RECT  0 50.736 0.084 50.76 ;
    END
  END program_data[33]
  PIN program_data[34]
    DIRECTION INPUT ;
    USE SIGNAL ;
    PORT
      LAYER M4 ;
        RECT  0 50.832 0.084 50.856 ;
    END
  END program_data[34]
  PIN program_data[35]
    DIRECTION INPUT ;
    USE SIGNAL ;
    PORT
      LAYER M4 ;
        RECT  0 50.928 0.084 50.952 ;
    END
  END program_data[35]
  PIN program_data[36]
    DIRECTION INPUT ;
    USE SIGNAL ;
    PORT
      LAYER M4 ;
        RECT  0 51.024 0.084 51.048 ;
    END
  END program_data[36]
  PIN program_data[37]
    DIRECTION INPUT ;
    USE SIGNAL ;
    PORT
      LAYER M4 ;
        RECT  0 51.12 0.084 51.144 ;
    END
  END program_data[37]
  PIN program_data[38]
    DIRECTION INPUT ;
    USE SIGNAL ;
    PORT
      LAYER M4 ;
        RECT  0 51.216 0.084 51.24 ;
    END
  END program_data[38]
  PIN program_data[39]
    DIRECTION INPUT ;
    USE SIGNAL ;
    PORT
      LAYER M4 ;
        RECT  0 51.312 0.084 51.336 ;
    END
  END program_data[39]
  PIN program_data[3]
    DIRECTION INPUT ;
    USE SIGNAL ;
    PORT
      LAYER M4 ;
        RECT  0 18.672 0.084 18.696 ;
    END
  END program_data[3]
  PIN program_data[40]
    DIRECTION INPUT ;
    USE SIGNAL ;
    PORT
      LAYER M4 ;
        RECT  0 51.408 0.084 51.432 ;
    END
  END program_data[40]
  PIN program_data[41]
    DIRECTION INPUT ;
    USE SIGNAL ;
    PORT
      LAYER M4 ;
        RECT  0 51.504 0.084 51.528 ;
    END
  END program_data[41]
  PIN program_data[42]
    DIRECTION INPUT ;
    USE SIGNAL ;
    PORT
      LAYER M4 ;
        RECT  0 51.6 0.084 51.624 ;
    END
  END program_data[42]
  PIN program_data[43]
    DIRECTION INPUT ;
    USE SIGNAL ;
    PORT
      LAYER M4 ;
        RECT  0 51.696 0.084 51.72 ;
    END
  END program_data[43]
  PIN program_data[44]
    DIRECTION INPUT ;
    USE SIGNAL ;
    PORT
      LAYER M4 ;
        RECT  0 51.792 0.084 51.816 ;
    END
  END program_data[44]
  PIN program_data[45]
    DIRECTION INPUT ;
    USE SIGNAL ;
    PORT
      LAYER M4 ;
        RECT  0 51.888 0.084 51.912 ;
    END
  END program_data[45]
  PIN program_data[46]
    DIRECTION INPUT ;
    USE SIGNAL ;
    PORT
      LAYER M4 ;
        RECT  0 51.984 0.084 52.008 ;
    END
  END program_data[46]
  PIN program_data[47]
    DIRECTION INPUT ;
    USE SIGNAL ;
    PORT
      LAYER M4 ;
        RECT  0 52.08 0.084 52.104 ;
    END
  END program_data[47]
  PIN program_data[48]
    DIRECTION INPUT ;
    USE SIGNAL ;
    PORT
      LAYER M4 ;
        RECT  0 52.176 0.084 52.2 ;
    END
  END program_data[48]
  PIN program_data[49]
    DIRECTION INPUT ;
    USE SIGNAL ;
    PORT
      LAYER M4 ;
        RECT  0 52.272 0.084 52.296 ;
    END
  END program_data[49]
  PIN program_data[4]
    DIRECTION INPUT ;
    USE SIGNAL ;
    PORT
      LAYER M4 ;
        RECT  0 18.768 0.084 18.792 ;
    END
  END program_data[4]
  PIN program_data[50]
    DIRECTION INPUT ;
    USE SIGNAL ;
    PORT
      LAYER M4 ;
        RECT  0 52.368 0.084 52.392 ;
    END
  END program_data[50]
  PIN program_data[51]
    DIRECTION INPUT ;
    USE SIGNAL ;
    PORT
      LAYER M4 ;
        RECT  0 52.464 0.084 52.488 ;
    END
  END program_data[51]
  PIN program_data[52]
    DIRECTION INPUT ;
    USE SIGNAL ;
    PORT
      LAYER M4 ;
        RECT  0 52.56 0.084 52.584 ;
    END
  END program_data[52]
  PIN program_data[53]
    DIRECTION INPUT ;
    USE SIGNAL ;
    PORT
      LAYER M4 ;
        RECT  0 52.656 0.084 52.68 ;
    END
  END program_data[53]
  PIN program_data[54]
    DIRECTION INPUT ;
    USE SIGNAL ;
    PORT
      LAYER M4 ;
        RECT  0 52.752 0.084 52.776 ;
    END
  END program_data[54]
  PIN program_data[55]
    DIRECTION INPUT ;
    USE SIGNAL ;
    PORT
      LAYER M4 ;
        RECT  0 52.848 0.084 52.872 ;
    END
  END program_data[55]
  PIN program_data[56]
    DIRECTION INPUT ;
    USE SIGNAL ;
    PORT
      LAYER M4 ;
        RECT  0 52.944 0.084 52.968 ;
    END
  END program_data[56]
  PIN program_data[57]
    DIRECTION INPUT ;
    USE SIGNAL ;
    PORT
      LAYER M4 ;
        RECT  0 53.04 0.084 53.064 ;
    END
  END program_data[57]
  PIN program_data[58]
    DIRECTION INPUT ;
    USE SIGNAL ;
    PORT
      LAYER M4 ;
        RECT  0 53.136 0.084 53.16 ;
    END
  END program_data[58]
  PIN program_data[59]
    DIRECTION INPUT ;
    USE SIGNAL ;
    PORT
      LAYER M4 ;
        RECT  0 53.232 0.084 53.256 ;
    END
  END program_data[59]
  PIN program_data[5]
    DIRECTION INPUT ;
    USE SIGNAL ;
    PORT
      LAYER M4 ;
        RECT  0 48.048 0.084 48.072 ;
    END
  END program_data[5]
  PIN program_data[60]
    DIRECTION INPUT ;
    USE SIGNAL ;
    PORT
      LAYER M4 ;
        RECT  0 53.328 0.084 53.352 ;
    END
  END program_data[60]
  PIN program_data[61]
    DIRECTION INPUT ;
    USE SIGNAL ;
    PORT
      LAYER M4 ;
        RECT  0 53.424 0.084 53.448 ;
    END
  END program_data[61]
  PIN program_data[62]
    DIRECTION INPUT ;
    USE SIGNAL ;
    PORT
      LAYER M4 ;
        RECT  0 53.52 0.084 53.544 ;
    END
  END program_data[62]
  PIN program_data[63]
    DIRECTION INPUT ;
    USE SIGNAL ;
    PORT
      LAYER M4 ;
        RECT  0 53.616 0.084 53.64 ;
    END
  END program_data[63]
  PIN program_data[64]
    DIRECTION INPUT ;
    USE SIGNAL ;
    PORT
      LAYER M4 ;
        RECT  0 53.712 0.084 53.736 ;
    END
  END program_data[64]
  PIN program_data[65]
    DIRECTION INPUT ;
    USE SIGNAL ;
    PORT
      LAYER M4 ;
        RECT  0 53.808 0.084 53.832 ;
    END
  END program_data[65]
  PIN program_data[66]
    DIRECTION INPUT ;
    USE SIGNAL ;
    PORT
      LAYER M4 ;
        RECT  0 53.904 0.084 53.928 ;
    END
  END program_data[66]
  PIN program_data[67]
    DIRECTION INPUT ;
    USE SIGNAL ;
    PORT
      LAYER M4 ;
        RECT  0 54 0.084 54.024 ;
    END
  END program_data[67]
  PIN program_data[68]
    DIRECTION INPUT ;
    USE SIGNAL ;
    PORT
      LAYER M4 ;
        RECT  0 54.096 0.084 54.12 ;
    END
  END program_data[68]
  PIN program_data[69]
    DIRECTION INPUT ;
    USE SIGNAL ;
    PORT
      LAYER M4 ;
        RECT  0 54.192 0.084 54.216 ;
    END
  END program_data[69]
  PIN program_data[6]
    DIRECTION INPUT ;
    USE SIGNAL ;
    PORT
      LAYER M4 ;
        RECT  0 48.144 0.084 48.168 ;
    END
  END program_data[6]
  PIN program_data[70]
    DIRECTION INPUT ;
    USE SIGNAL ;
    PORT
      LAYER M4 ;
        RECT  0 54.288 0.084 54.312 ;
    END
  END program_data[70]
  PIN program_data[71]
    DIRECTION INPUT ;
    USE SIGNAL ;
    PORT
      LAYER M4 ;
        RECT  0 54.384 0.084 54.408 ;
    END
  END program_data[71]
  PIN program_data[72]
    DIRECTION INPUT ;
    USE SIGNAL ;
    PORT
      LAYER M4 ;
        RECT  0 54.48 0.084 54.504 ;
    END
  END program_data[72]
  PIN program_data[73]
    DIRECTION INPUT ;
    USE SIGNAL ;
    PORT
      LAYER M4 ;
        RECT  0 54.576 0.084 54.6 ;
    END
  END program_data[73]
  PIN program_data[74]
    DIRECTION INPUT ;
    USE SIGNAL ;
    PORT
      LAYER M4 ;
        RECT  0 54.672 0.084 54.696 ;
    END
  END program_data[74]
  PIN program_data[75]
    DIRECTION INPUT ;
    USE SIGNAL ;
    PORT
      LAYER M4 ;
        RECT  0 54.768 0.084 54.792 ;
    END
  END program_data[75]
  PIN program_data[76]
    DIRECTION INPUT ;
    USE SIGNAL ;
    PORT
      LAYER M4 ;
        RECT  0 54.864 0.084 54.888 ;
    END
  END program_data[76]
  PIN program_data[77]
    DIRECTION INPUT ;
    USE SIGNAL ;
    PORT
      LAYER M4 ;
        RECT  0 54.96 0.084 54.984 ;
    END
  END program_data[77]
  PIN program_data[78]
    DIRECTION INPUT ;
    USE SIGNAL ;
    PORT
      LAYER M4 ;
        RECT  0 55.056 0.084 55.08 ;
    END
  END program_data[78]
  PIN program_data[79]
    DIRECTION INPUT ;
    USE SIGNAL ;
    PORT
      LAYER M4 ;
        RECT  0 55.152 0.084 55.176 ;
    END
  END program_data[79]
  PIN program_data[7]
    DIRECTION INPUT ;
    USE SIGNAL ;
    PORT
      LAYER M4 ;
        RECT  0 48.24 0.084 48.264 ;
    END
  END program_data[7]
  PIN program_data[80]
    DIRECTION INPUT ;
    USE SIGNAL ;
    PORT
      LAYER M4 ;
        RECT  0 55.248 0.084 55.272 ;
    END
  END program_data[80]
  PIN program_data[81]
    DIRECTION INPUT ;
    USE SIGNAL ;
    PORT
      LAYER M4 ;
        RECT  0 55.344 0.084 55.368 ;
    END
  END program_data[81]
  PIN program_data[82]
    DIRECTION INPUT ;
    USE SIGNAL ;
    PORT
      LAYER M4 ;
        RECT  0 55.44 0.084 55.464 ;
    END
  END program_data[82]
  PIN program_data[83]
    DIRECTION INPUT ;
    USE SIGNAL ;
    PORT
      LAYER M4 ;
        RECT  0 55.536 0.084 55.56 ;
    END
  END program_data[83]
  PIN program_data[84]
    DIRECTION INPUT ;
    USE SIGNAL ;
    PORT
      LAYER M4 ;
        RECT  0 55.632 0.084 55.656 ;
    END
  END program_data[84]
  PIN program_data[85]
    DIRECTION INPUT ;
    USE SIGNAL ;
    PORT
      LAYER M4 ;
        RECT  0 55.728 0.084 55.752 ;
    END
  END program_data[85]
  PIN program_data[86]
    DIRECTION INPUT ;
    USE SIGNAL ;
    PORT
      LAYER M4 ;
        RECT  0 55.824 0.084 55.848 ;
    END
  END program_data[86]
  PIN program_data[87]
    DIRECTION INPUT ;
    USE SIGNAL ;
    PORT
      LAYER M4 ;
        RECT  0 55.92 0.084 55.944 ;
    END
  END program_data[87]
  PIN program_data[88]
    DIRECTION INPUT ;
    USE SIGNAL ;
    PORT
      LAYER M4 ;
        RECT  0 56.016 0.084 56.04 ;
    END
  END program_data[88]
  PIN program_data[89]
    DIRECTION INPUT ;
    USE SIGNAL ;
    PORT
      LAYER M4 ;
        RECT  0 56.112 0.084 56.136 ;
    END
  END program_data[89]
  PIN program_data[8]
    DIRECTION INPUT ;
    USE SIGNAL ;
    PORT
      LAYER M4 ;
        RECT  0 48.336 0.084 48.36 ;
    END
  END program_data[8]
  PIN program_data[90]
    DIRECTION INPUT ;
    USE SIGNAL ;
    PORT
      LAYER M4 ;
        RECT  0 56.208 0.084 56.232 ;
    END
  END program_data[90]
  PIN program_data[91]
    DIRECTION INPUT ;
    USE SIGNAL ;
    PORT
      LAYER M4 ;
        RECT  0 56.304 0.084 56.328 ;
    END
  END program_data[91]
  PIN program_data[92]
    DIRECTION INPUT ;
    USE SIGNAL ;
    PORT
      LAYER M4 ;
        RECT  0 56.4 0.084 56.424 ;
    END
  END program_data[92]
  PIN program_data[93]
    DIRECTION INPUT ;
    USE SIGNAL ;
    PORT
      LAYER M4 ;
        RECT  0 56.496 0.084 56.52 ;
    END
  END program_data[93]
  PIN program_data[94]
    DIRECTION INPUT ;
    USE SIGNAL ;
    PORT
      LAYER M4 ;
        RECT  0 56.592 0.084 56.616 ;
    END
  END program_data[94]
  PIN program_data[95]
    DIRECTION INPUT ;
    USE SIGNAL ;
    PORT
      LAYER M4 ;
        RECT  0 56.688 0.084 56.712 ;
    END
  END program_data[95]
  PIN program_data[96]
    DIRECTION INPUT ;
    USE SIGNAL ;
    PORT
      LAYER M4 ;
        RECT  0 56.784 0.084 56.808 ;
    END
  END program_data[96]
  PIN program_data[97]
    DIRECTION INPUT ;
    USE SIGNAL ;
    PORT
      LAYER M4 ;
        RECT  0 56.88 0.084 56.904 ;
    END
  END program_data[97]
  PIN program_data[98]
    DIRECTION INPUT ;
    USE SIGNAL ;
    PORT
      LAYER M4 ;
        RECT  0 56.976 0.084 57 ;
    END
  END program_data[98]
  PIN program_data[99]
    DIRECTION INPUT ;
    USE SIGNAL ;
    PORT
      LAYER M4 ;
        RECT  0 57.072 0.084 57.096 ;
    END
  END program_data[99]
  PIN program_data[9]
    DIRECTION INPUT ;
    USE SIGNAL ;
    PORT
      LAYER M4 ;
        RECT  0 48.432 0.084 48.456 ;
    END
  END program_data[9]
  PIN program_we
    DIRECTION INPUT ;
    USE SIGNAL ;
    PORT
      LAYER M4 ;
        RECT  0 34.512 0.084 34.536 ;
    END
  END program_we
  PIN qf
    DIRECTION INPUT ;
    USE SIGNAL ;
    PORT
      LAYER M4 ;
        RECT  0 34.608 0.084 34.632 ;
    END
  END qf
  PIN query_emit
    DIRECTION OUTPUT ;
    USE SIGNAL ;
    PORT
      LAYER M4 ;
        RECT  0 34.704 0.084 34.728 ;
    END
  END query_emit
  PIN query_emit_head[0]
    DIRECTION OUTPUT ;
    USE SIGNAL ;
    PORT
      LAYER M4 ;
        RECT  0 34.8 0.084 34.824 ;
    END
  END query_emit_head[0]
  PIN query_emit_head[1]
    DIRECTION OUTPUT ;
    USE SIGNAL ;
    PORT
      LAYER M4 ;
        RECT  0 34.896 0.084 34.92 ;
    END
  END query_emit_head[1]
  PIN query_emit_head[2]
    DIRECTION OUTPUT ;
    USE SIGNAL ;
    PORT
      LAYER M4 ;
        RECT  0 36.432 0.084 36.456 ;
    END
  END query_emit_head[2]
  PIN query_emit_head[3]
    DIRECTION OUTPUT ;
    USE SIGNAL ;
    PORT
      LAYER M4 ;
        RECT  0 36.528 0.084 36.552 ;
    END
  END query_emit_head[3]
  PIN query_emit_head[4]
    DIRECTION OUTPUT ;
    USE SIGNAL ;
    PORT
      LAYER M4 ;
        RECT  0 36.624 0.084 36.648 ;
    END
  END query_emit_head[4]
  PIN query_index[0]
    DIRECTION OUTPUT ;
    USE SIGNAL ;
    PORT
      LAYER M4 ;
        RECT  0 36.72 0.084 36.744 ;
    END
  END query_index[0]
  PIN query_index[1]
    DIRECTION OUTPUT ;
    USE SIGNAL ;
    PORT
      LAYER M4 ;
        RECT  0 36.816 0.084 36.84 ;
    END
  END query_index[1]
  PIN query_index[2]
    DIRECTION OUTPUT ;
    USE SIGNAL ;
    PORT
      LAYER M4 ;
        RECT  0 36.912 0.084 36.936 ;
    END
  END query_index[2]
  PIN query_index[3]
    DIRECTION OUTPUT ;
    USE SIGNAL ;
    PORT
      LAYER M4 ;
        RECT  0 37.008 0.084 37.032 ;
    END
  END query_index[3]
  PIN query_index[4]
    DIRECTION OUTPUT ;
    USE SIGNAL ;
    PORT
      LAYER M4 ;
        RECT  0 37.104 0.084 37.128 ;
    END
  END query_index[4]
  PIN query_index[5]
    DIRECTION OUTPUT ;
    USE SIGNAL ;
    PORT
      LAYER M4 ;
        RECT  0 37.2 0.084 37.224 ;
    END
  END query_index[5]
  PIN query_index[6]
    DIRECTION OUTPUT ;
    USE SIGNAL ;
    PORT
      LAYER M4 ;
        RECT  0 37.296 0.084 37.32 ;
    END
  END query_index[6]
  PIN query_slot
    DIRECTION OUTPUT ;
    USE SIGNAL ;
    PORT
      LAYER M4 ;
        RECT  0 37.392 0.084 37.416 ;
    END
  END query_slot
  PIN rst_n
    DIRECTION INPUT ;
    USE SIGNAL ;
    PORT
      LAYER M4 ;
        RECT  0 37.488 0.084 37.512 ;
    END
  END rst_n
  PIN scf
    DIRECTION INPUT ;
    USE SIGNAL ;
    PORT
      LAYER M4 ;
        RECT  0 37.584 0.084 37.608 ;
    END
  END scf
  PIN slot
    DIRECTION INPUT ;
    USE SIGNAL ;
    PORT
      LAYER M4 ;
        RECT  0 37.68 0.084 37.704 ;
    END
  END slot
  PIN start
    DIRECTION INPUT ;
    USE SIGNAL ;
    PORT
      LAYER M4 ;
        RECT  0 37.776 0.084 37.8 ;
    END
  END start
  PIN vf
    DIRECTION INPUT ;
    USE SIGNAL ;
    PORT
      LAYER M4 ;
        RECT  0 37.872 0.084 37.896 ;
    END
  END vf
  PIN weight_slot
    DIRECTION OUTPUT ;
    USE SIGNAL ;
    PORT
      LAYER M4 ;
        RECT  0 37.968 0.084 37.992 ;
    END
  END weight_slot
  PIN VDD
    DIRECTION INOUT ;
    USE POWER ;
    PORT
      LAYER M5 ;
        RECT  234.792 2.151 234.912 84.249 ;
        RECT  229.392 2.151 229.512 84.249 ;
        RECT  223.992 2.151 224.112 84.249 ;
        RECT  218.592 2.151 218.712 84.249 ;
        RECT  213.192 2.151 213.312 84.249 ;
        RECT  207.792 2.151 207.912 84.249 ;
        RECT  202.392 2.151 202.512 84.249 ;
        RECT  196.992 2.151 197.112 84.249 ;
        RECT  191.592 2.151 191.712 84.249 ;
        RECT  186.192 2.151 186.312 84.249 ;
        RECT  180.792 2.151 180.912 84.249 ;
        RECT  175.392 2.151 175.512 84.249 ;
        RECT  169.992 2.151 170.112 84.249 ;
        RECT  164.592 2.151 164.712 84.249 ;
        RECT  159.192 2.151 159.312 84.249 ;
        RECT  153.792 2.151 153.912 84.249 ;
        RECT  148.392 2.151 148.512 84.249 ;
        RECT  142.992 2.151 143.112 84.249 ;
        RECT  137.592 2.151 137.712 84.249 ;
        RECT  132.192 2.151 132.312 84.249 ;
        RECT  126.792 2.151 126.912 84.249 ;
        RECT  121.392 2.151 121.512 84.249 ;
        RECT  115.992 2.151 116.112 84.249 ;
        RECT  110.592 2.151 110.712 84.249 ;
        RECT  105.192 2.151 105.312 84.249 ;
        RECT  99.792 2.151 99.912 84.249 ;
        RECT  94.392 2.151 94.512 84.249 ;
        RECT  88.992 2.151 89.112 84.249 ;
        RECT  83.592 2.151 83.712 84.249 ;
        RECT  78.192 2.151 78.312 84.249 ;
        RECT  72.792 2.151 72.912 84.249 ;
        RECT  67.392 2.151 67.512 84.249 ;
        RECT  61.992 2.151 62.112 84.249 ;
        RECT  56.592 2.151 56.712 84.249 ;
        RECT  51.192 2.151 51.312 84.249 ;
        RECT  45.792 2.151 45.912 84.249 ;
        RECT  40.392 2.151 40.512 84.249 ;
        RECT  34.992 2.151 35.112 84.249 ;
        RECT  29.592 2.151 29.712 84.249 ;
        RECT  24.192 2.151 24.312 84.249 ;
        RECT  18.792 2.151 18.912 84.249 ;
        RECT  13.392 2.151 13.512 84.249 ;
        RECT  7.992 2.151 8.112 84.249 ;
        RECT  2.592 2.151 2.712 84.249 ;
    END
  END VDD
  PIN VSS
    DIRECTION INOUT ;
    USE GROUND ;
    PORT
      LAYER M5 ;
        RECT  234.6 2.137 234.72 84.263 ;
        RECT  229.2 2.137 229.32 84.263 ;
        RECT  223.8 2.137 223.92 84.263 ;
        RECT  218.4 2.137 218.52 84.263 ;
        RECT  213 2.137 213.12 84.263 ;
        RECT  207.6 2.137 207.72 84.263 ;
        RECT  202.2 2.137 202.32 84.263 ;
        RECT  196.8 2.137 196.92 84.263 ;
        RECT  191.4 2.137 191.52 84.263 ;
        RECT  186 2.137 186.12 84.263 ;
        RECT  180.6 2.137 180.72 84.263 ;
        RECT  175.2 2.137 175.32 84.263 ;
        RECT  169.8 2.137 169.92 84.263 ;
        RECT  164.4 2.137 164.52 84.263 ;
        RECT  159 2.137 159.12 84.263 ;
        RECT  153.6 2.137 153.72 84.263 ;
        RECT  148.2 2.137 148.32 84.263 ;
        RECT  142.8 2.137 142.92 84.263 ;
        RECT  137.4 2.137 137.52 84.263 ;
        RECT  132 2.137 132.12 84.263 ;
        RECT  126.6 2.137 126.72 84.263 ;
        RECT  121.2 2.137 121.32 84.263 ;
        RECT  115.8 2.137 115.92 84.263 ;
        RECT  110.4 2.137 110.52 84.263 ;
        RECT  105 2.137 105.12 84.263 ;
        RECT  99.6 2.137 99.72 84.263 ;
        RECT  94.2 2.137 94.32 84.263 ;
        RECT  88.8 2.137 88.92 84.263 ;
        RECT  83.4 2.137 83.52 84.263 ;
        RECT  78 2.137 78.12 84.263 ;
        RECT  72.6 2.137 72.72 84.263 ;
        RECT  67.2 2.137 67.32 84.263 ;
        RECT  61.8 2.137 61.92 84.263 ;
        RECT  56.4 2.137 56.52 84.263 ;
        RECT  51 2.137 51.12 84.263 ;
        RECT  45.6 2.137 45.72 84.263 ;
        RECT  40.2 2.137 40.32 84.263 ;
        RECT  34.8 2.137 34.92 84.263 ;
        RECT  29.4 2.137 29.52 84.263 ;
        RECT  24 2.137 24.12 84.263 ;
        RECT  18.6 2.137 18.72 84.263 ;
        RECT  13.2 2.137 13.32 84.263 ;
        RECT  7.8 2.137 7.92 84.263 ;
        RECT  2.4 2.137 2.52 84.263 ;
    END
  END VSS
  # OT_OBS_CLOSED layer=M5 d_um=1.536 added=21
  OBS
    LAYER RVTN ;
     RECT  2.16 2.16 239.76 2.295 ;
     RECT  2.16 2.565 239.76 2.835 ;
     RECT  2.16 3.105 239.76 3.375 ;
     RECT  2.16 3.645 239.76 3.915 ;
     RECT  2.16 4.185 239.76 4.455 ;
     RECT  2.16 4.725 239.76 4.995 ;
     RECT  2.16 5.265 239.76 5.535 ;
     RECT  2.16 5.805 239.76 6.075 ;
     RECT  2.16 6.345 239.76 6.615 ;
     RECT  2.16 6.885 239.76 7.155 ;
     RECT  2.16 7.425 239.76 7.695 ;
     RECT  2.16 7.965 239.76 8.235 ;
     RECT  2.16 8.505 239.76 8.775 ;
     RECT  2.16 9.045 239.76 9.315 ;
     RECT  2.16 9.585 239.76 9.855 ;
     RECT  2.16 10.125 239.76 10.395 ;
     RECT  2.16 10.665 239.76 10.935 ;
     RECT  2.16 11.205 239.76 11.475 ;
     RECT  2.16 11.745 239.76 12.015 ;
     RECT  2.16 12.285 239.76 12.555 ;
     RECT  2.16 12.825 239.76 13.095 ;
     RECT  2.16 13.365 239.76 13.635 ;
     RECT  2.16 13.905 239.76 14.175 ;
     RECT  2.16 14.445 239.76 14.715 ;
     RECT  2.16 14.985 239.76 15.255 ;
     RECT  2.16 15.525 239.76 15.795 ;
     RECT  2.16 16.065 239.76 16.335 ;
     RECT  2.16 16.605 239.76 16.875 ;
     RECT  2.16 17.145 239.76 17.415 ;
     RECT  2.16 17.685 239.76 17.955 ;
     RECT  2.16 18.225 239.76 18.495 ;
     RECT  2.16 18.765 239.76 19.035 ;
     RECT  2.16 19.305 239.76 19.44 ;
     RECT  2.16 19.44 41.148 19.575 ;
     RECT  218.052 19.44 239.76 19.575 ;
     RECT  2.16 19.845 41.148 20.115 ;
     RECT  218.052 19.845 239.76 20.115 ;
     RECT  2.16 20.385 41.148 20.655 ;
     RECT  218.052 20.385 239.76 20.655 ;
     RECT  2.16 20.925 41.148 21.195 ;
     RECT  218.052 20.925 239.76 21.195 ;
     RECT  2.16 21.465 41.148 21.735 ;
     RECT  218.052 21.465 239.76 21.735 ;
     RECT  2.16 22.005 41.148 22.275 ;
     RECT  218.052 22.005 239.76 22.275 ;
     RECT  2.16 22.545 41.148 22.815 ;
     RECT  218.052 22.545 239.76 22.815 ;
     RECT  2.16 23.085 41.148 23.355 ;
     RECT  218.052 23.085 239.76 23.355 ;
     RECT  2.16 23.625 41.148 23.895 ;
     RECT  218.052 23.625 239.76 23.895 ;
     RECT  2.16 24.165 41.148 24.435 ;
     RECT  218.052 24.165 239.76 24.435 ;
     RECT  2.16 24.705 41.148 24.975 ;
     RECT  218.052 24.705 239.76 24.975 ;
     RECT  2.16 25.245 41.148 25.515 ;
     RECT  218.052 25.245 239.76 25.515 ;
     RECT  2.16 25.785 41.148 26.055 ;
     RECT  218.052 25.785 239.76 26.055 ;
     RECT  2.16 26.325 41.148 26.595 ;
     RECT  218.052 26.325 239.76 26.595 ;
     RECT  2.16 26.865 41.148 27.135 ;
     RECT  218.052 26.865 239.76 27.135 ;
     RECT  2.16 27.405 41.148 27.675 ;
     RECT  218.052 27.405 239.76 27.675 ;
     RECT  2.16 27.945 41.148 28.215 ;
     RECT  218.052 27.945 239.76 28.215 ;
     RECT  2.16 28.485 41.148 28.755 ;
     RECT  218.052 28.485 239.76 28.755 ;
     RECT  2.16 29.025 41.148 29.295 ;
     RECT  218.052 29.025 239.76 29.295 ;
     RECT  2.16 29.565 41.148 29.835 ;
     RECT  218.052 29.565 239.76 29.835 ;
     RECT  2.16 30.105 41.148 30.375 ;
     RECT  218.052 30.105 239.76 30.375 ;
     RECT  2.16 30.645 41.148 30.915 ;
     RECT  218.052 30.645 239.76 30.915 ;
     RECT  2.16 31.185 41.148 31.455 ;
     RECT  218.052 31.185 239.76 31.455 ;
     RECT  2.16 31.725 41.148 31.995 ;
     RECT  218.052 31.725 239.76 31.995 ;
     RECT  2.16 32.265 41.148 32.535 ;
     RECT  218.052 32.265 239.76 32.535 ;
     RECT  2.16 32.805 41.148 33.075 ;
     RECT  218.052 32.805 239.76 33.075 ;
     RECT  2.16 33.345 41.148 33.615 ;
     RECT  218.052 33.345 239.76 33.615 ;
     RECT  2.16 33.885 41.148 34.155 ;
     RECT  218.052 33.885 239.76 34.155 ;
     RECT  2.16 34.425 41.148 34.695 ;
     RECT  218.052 34.425 239.76 34.695 ;
     RECT  2.16 34.965 41.148 35.235 ;
     RECT  218.052 34.965 239.76 35.235 ;
     RECT  2.16 35.505 41.148 35.775 ;
     RECT  218.052 35.505 239.76 35.775 ;
     RECT  2.16 36.045 41.148 36.315 ;
     RECT  218.052 36.045 239.76 36.315 ;
     RECT  2.16 36.585 41.148 36.855 ;
     RECT  218.052 36.585 239.76 36.855 ;
     RECT  2.16 37.125 41.148 37.395 ;
     RECT  218.052 37.125 239.76 37.395 ;
     RECT  2.16 37.665 41.148 37.935 ;
     RECT  218.052 37.665 239.76 37.935 ;
     RECT  2.16 38.205 41.148 38.475 ;
     RECT  218.052 38.205 239.76 38.475 ;
     RECT  2.16 38.745 41.148 39.015 ;
     RECT  218.052 38.745 239.76 39.015 ;
     RECT  2.16 39.285 41.148 39.555 ;
     RECT  218.052 39.285 239.76 39.555 ;
     RECT  2.16 39.825 41.148 40.095 ;
     RECT  218.052 39.825 239.76 40.095 ;
     RECT  2.16 40.365 41.148 40.635 ;
     RECT  218.052 40.365 239.76 40.635 ;
     RECT  2.16 40.905 41.148 41.175 ;
     RECT  218.052 40.905 239.76 41.175 ;
     RECT  2.16 41.445 41.148 41.715 ;
     RECT  218.052 41.445 239.76 41.715 ;
     RECT  2.16 41.985 41.148 42.255 ;
     RECT  218.052 41.985 239.76 42.255 ;
     RECT  2.16 42.525 41.148 42.795 ;
     RECT  218.052 42.525 239.76 42.795 ;
     RECT  2.16 43.065 41.148 43.335 ;
     RECT  218.052 43.065 239.76 43.335 ;
     RECT  2.16 43.605 41.148 43.875 ;
     RECT  218.052 43.605 239.76 43.875 ;
     RECT  2.16 44.145 41.148 44.415 ;
     RECT  218.052 44.145 239.76 44.415 ;
     RECT  2.16 44.685 41.148 44.955 ;
     RECT  218.052 44.685 239.76 44.955 ;
     RECT  2.16 45.225 41.148 45.495 ;
     RECT  218.052 45.225 239.76 45.495 ;
     RECT  2.16 45.765 41.148 46.035 ;
     RECT  218.052 45.765 239.76 46.035 ;
     RECT  2.16 46.305 41.148 46.575 ;
     RECT  218.052 46.305 239.76 46.575 ;
     RECT  2.16 46.845 41.148 47.115 ;
     RECT  218.052 46.845 239.76 47.115 ;
     RECT  2.16 47.385 41.148 47.655 ;
     RECT  218.052 47.385 239.76 47.655 ;
     RECT  2.16 47.925 41.148 48.195 ;
     RECT  218.052 47.925 239.76 48.195 ;
     RECT  2.16 48.465 41.148 48.735 ;
     RECT  218.052 48.465 239.76 48.735 ;
     RECT  2.16 49.005 41.148 49.275 ;
     RECT  218.052 49.005 239.76 49.275 ;
     RECT  2.16 49.545 41.148 49.815 ;
     RECT  218.052 49.545 239.76 49.815 ;
     RECT  2.16 50.085 41.148 50.355 ;
     RECT  218.052 50.085 239.76 50.355 ;
     RECT  2.16 50.625 41.148 50.895 ;
     RECT  218.052 50.625 239.76 50.895 ;
     RECT  2.16 51.165 41.148 51.435 ;
     RECT  218.052 51.165 239.76 51.435 ;
     RECT  2.16 51.705 41.148 51.975 ;
     RECT  218.052 51.705 239.76 51.975 ;
     RECT  2.16 52.245 41.148 52.515 ;
     RECT  218.052 52.245 239.76 52.515 ;
     RECT  2.16 52.785 41.148 53.055 ;
     RECT  218.052 52.785 239.76 53.055 ;
     RECT  2.16 53.325 41.148 53.595 ;
     RECT  218.052 53.325 239.76 53.595 ;
     RECT  2.16 53.865 41.148 54.135 ;
     RECT  218.052 53.865 239.76 54.135 ;
     RECT  2.16 54.405 41.148 54.675 ;
     RECT  218.052 54.405 239.76 54.675 ;
     RECT  2.16 54.945 41.148 55.215 ;
     RECT  218.052 54.945 239.76 55.215 ;
     RECT  2.16 55.485 41.148 55.755 ;
     RECT  218.052 55.485 239.76 55.755 ;
     RECT  2.16 56.025 41.148 56.295 ;
     RECT  218.052 56.025 239.76 56.295 ;
     RECT  2.16 56.565 41.148 56.835 ;
     RECT  218.052 56.565 239.76 56.835 ;
     RECT  2.16 57.105 41.148 57.375 ;
     RECT  218.052 57.105 239.76 57.375 ;
     RECT  2.16 57.645 41.148 57.915 ;
     RECT  218.052 57.645 239.76 57.915 ;
     RECT  2.16 58.185 41.148 58.455 ;
     RECT  218.052 58.185 239.76 58.455 ;
     RECT  2.16 58.725 41.148 58.995 ;
     RECT  218.052 58.725 239.76 58.995 ;
     RECT  2.16 59.265 41.148 59.535 ;
     RECT  218.052 59.265 239.76 59.535 ;
     RECT  2.16 59.805 41.148 60.075 ;
     RECT  218.052 59.805 239.76 60.075 ;
     RECT  2.16 60.345 41.148 60.615 ;
     RECT  218.052 60.345 239.76 60.615 ;
     RECT  2.16 60.885 41.148 61.155 ;
     RECT  218.052 60.885 239.76 61.155 ;
     RECT  2.16 61.425 41.148 61.695 ;
     RECT  218.052 61.425 239.76 61.695 ;
     RECT  2.16 61.965 41.148 62.235 ;
     RECT  218.052 61.965 239.76 62.235 ;
     RECT  2.16 62.505 41.148 62.775 ;
     RECT  218.052 62.505 239.76 62.775 ;
     RECT  2.16 63.045 41.148 63.315 ;
     RECT  218.052 63.045 239.76 63.315 ;
     RECT  2.16 63.585 41.148 63.855 ;
     RECT  218.052 63.585 239.76 63.855 ;
     RECT  2.16 64.125 41.148 64.395 ;
     RECT  218.052 64.125 239.76 64.395 ;
     RECT  2.16 64.665 41.148 64.8 ;
     RECT  218.052 64.665 239.76 64.8 ;
     RECT  2.16 64.8 239.76 64.935 ;
     RECT  2.16 65.205 239.76 65.475 ;
     RECT  2.16 65.745 239.76 66.015 ;
     RECT  2.16 66.285 239.76 66.555 ;
     RECT  2.16 66.825 239.76 67.095 ;
     RECT  2.16 67.365 239.76 67.635 ;
     RECT  2.16 67.905 239.76 68.175 ;
     RECT  2.16 68.445 239.76 68.715 ;
     RECT  2.16 68.985 239.76 69.255 ;
     RECT  2.16 69.525 239.76 69.795 ;
     RECT  2.16 70.065 239.76 70.335 ;
     RECT  2.16 70.605 239.76 70.875 ;
     RECT  2.16 71.145 239.76 71.415 ;
     RECT  2.16 71.685 239.76 71.955 ;
     RECT  2.16 72.225 239.76 72.495 ;
     RECT  2.16 72.765 239.76 73.035 ;
     RECT  2.16 73.305 239.76 73.575 ;
     RECT  2.16 73.845 239.76 74.115 ;
     RECT  2.16 74.385 239.76 74.655 ;
     RECT  2.16 74.925 239.76 75.195 ;
     RECT  2.16 75.465 239.76 75.735 ;
     RECT  2.16 76.005 239.76 76.275 ;
     RECT  2.16 76.545 239.76 76.815 ;
     RECT  2.16 77.085 239.76 77.355 ;
     RECT  2.16 77.625 239.76 77.895 ;
     RECT  2.16 78.165 239.76 78.435 ;
     RECT  2.16 78.705 239.76 78.975 ;
     RECT  2.16 79.245 239.76 79.515 ;
     RECT  2.16 79.785 239.76 80.055 ;
     RECT  2.16 80.325 239.76 80.595 ;
     RECT  2.16 80.865 239.76 81.135 ;
     RECT  2.16 81.405 239.76 81.675 ;
     RECT  2.16 81.945 239.76 82.215 ;
     RECT  2.16 82.485 239.76 82.755 ;
     RECT  2.16 83.025 239.76 83.295 ;
     RECT  2.16 83.565 239.76 83.835 ;
     RECT  2.16 84.105 239.76 84.24 ;
    LAYER RVTP ;
     RECT  2.16 2.295 239.76 2.565 ;
     RECT  2.16 2.835 239.76 3.105 ;
     RECT  2.16 3.375 239.76 3.645 ;
     RECT  2.16 3.915 239.76 4.185 ;
     RECT  2.16 4.455 239.76 4.725 ;
     RECT  2.16 4.995 239.76 5.265 ;
     RECT  2.16 5.535 239.76 5.805 ;
     RECT  2.16 6.075 239.76 6.345 ;
     RECT  2.16 6.615 239.76 6.885 ;
     RECT  2.16 7.155 239.76 7.425 ;
     RECT  2.16 7.695 239.76 7.965 ;
     RECT  2.16 8.235 239.76 8.505 ;
     RECT  2.16 8.775 239.76 9.045 ;
     RECT  2.16 9.315 239.76 9.585 ;
     RECT  2.16 9.855 239.76 10.125 ;
     RECT  2.16 10.395 239.76 10.665 ;
     RECT  2.16 10.935 239.76 11.205 ;
     RECT  2.16 11.475 239.76 11.745 ;
     RECT  2.16 12.015 239.76 12.285 ;
     RECT  2.16 12.555 239.76 12.825 ;
     RECT  2.16 13.095 239.76 13.365 ;
     RECT  2.16 13.635 239.76 13.905 ;
     RECT  2.16 14.175 239.76 14.445 ;
     RECT  2.16 14.715 239.76 14.985 ;
     RECT  2.16 15.255 239.76 15.525 ;
     RECT  2.16 15.795 239.76 16.065 ;
     RECT  2.16 16.335 239.76 16.605 ;
     RECT  2.16 16.875 239.76 17.145 ;
     RECT  2.16 17.415 239.76 17.685 ;
     RECT  2.16 17.955 239.76 18.225 ;
     RECT  2.16 18.495 239.76 18.765 ;
     RECT  2.16 19.035 239.76 19.305 ;
     RECT  2.16 19.575 41.148 19.845 ;
     RECT  218.052 19.575 239.76 19.845 ;
     RECT  2.16 20.115 41.148 20.385 ;
     RECT  218.052 20.115 239.76 20.385 ;
     RECT  2.16 20.655 41.148 20.925 ;
     RECT  218.052 20.655 239.76 20.925 ;
     RECT  2.16 21.195 41.148 21.465 ;
     RECT  218.052 21.195 239.76 21.465 ;
     RECT  2.16 21.735 41.148 22.005 ;
     RECT  218.052 21.735 239.76 22.005 ;
     RECT  2.16 22.275 41.148 22.545 ;
     RECT  218.052 22.275 239.76 22.545 ;
     RECT  2.16 22.815 41.148 23.085 ;
     RECT  218.052 22.815 239.76 23.085 ;
     RECT  2.16 23.355 41.148 23.625 ;
     RECT  218.052 23.355 239.76 23.625 ;
     RECT  2.16 23.895 41.148 24.165 ;
     RECT  218.052 23.895 239.76 24.165 ;
     RECT  2.16 24.435 41.148 24.705 ;
     RECT  218.052 24.435 239.76 24.705 ;
     RECT  2.16 24.975 41.148 25.245 ;
     RECT  218.052 24.975 239.76 25.245 ;
     RECT  2.16 25.515 41.148 25.785 ;
     RECT  218.052 25.515 239.76 25.785 ;
     RECT  2.16 26.055 41.148 26.325 ;
     RECT  218.052 26.055 239.76 26.325 ;
     RECT  2.16 26.595 41.148 26.865 ;
     RECT  218.052 26.595 239.76 26.865 ;
     RECT  2.16 27.135 41.148 27.405 ;
     RECT  218.052 27.135 239.76 27.405 ;
     RECT  2.16 27.675 41.148 27.945 ;
     RECT  218.052 27.675 239.76 27.945 ;
     RECT  2.16 28.215 41.148 28.485 ;
     RECT  218.052 28.215 239.76 28.485 ;
     RECT  2.16 28.755 41.148 29.025 ;
     RECT  218.052 28.755 239.76 29.025 ;
     RECT  2.16 29.295 41.148 29.565 ;
     RECT  218.052 29.295 239.76 29.565 ;
     RECT  2.16 29.835 41.148 30.105 ;
     RECT  218.052 29.835 239.76 30.105 ;
     RECT  2.16 30.375 41.148 30.645 ;
     RECT  218.052 30.375 239.76 30.645 ;
     RECT  2.16 30.915 41.148 31.185 ;
     RECT  218.052 30.915 239.76 31.185 ;
     RECT  2.16 31.455 41.148 31.725 ;
     RECT  218.052 31.455 239.76 31.725 ;
     RECT  2.16 31.995 41.148 32.265 ;
     RECT  218.052 31.995 239.76 32.265 ;
     RECT  2.16 32.535 41.148 32.805 ;
     RECT  218.052 32.535 239.76 32.805 ;
     RECT  2.16 33.075 41.148 33.345 ;
     RECT  218.052 33.075 239.76 33.345 ;
     RECT  2.16 33.615 41.148 33.885 ;
     RECT  218.052 33.615 239.76 33.885 ;
     RECT  2.16 34.155 41.148 34.425 ;
     RECT  218.052 34.155 239.76 34.425 ;
     RECT  2.16 34.695 41.148 34.965 ;
     RECT  218.052 34.695 239.76 34.965 ;
     RECT  2.16 35.235 41.148 35.505 ;
     RECT  218.052 35.235 239.76 35.505 ;
     RECT  2.16 35.775 41.148 36.045 ;
     RECT  218.052 35.775 239.76 36.045 ;
     RECT  2.16 36.315 41.148 36.585 ;
     RECT  218.052 36.315 239.76 36.585 ;
     RECT  2.16 36.855 41.148 37.125 ;
     RECT  218.052 36.855 239.76 37.125 ;
     RECT  2.16 37.395 41.148 37.665 ;
     RECT  218.052 37.395 239.76 37.665 ;
     RECT  2.16 37.935 41.148 38.205 ;
     RECT  218.052 37.935 239.76 38.205 ;
     RECT  2.16 38.475 41.148 38.745 ;
     RECT  218.052 38.475 239.76 38.745 ;
     RECT  2.16 39.015 41.148 39.285 ;
     RECT  218.052 39.015 239.76 39.285 ;
     RECT  2.16 39.555 41.148 39.825 ;
     RECT  218.052 39.555 239.76 39.825 ;
     RECT  2.16 40.095 41.148 40.365 ;
     RECT  218.052 40.095 239.76 40.365 ;
     RECT  2.16 40.635 41.148 40.905 ;
     RECT  218.052 40.635 239.76 40.905 ;
     RECT  2.16 41.175 41.148 41.445 ;
     RECT  218.052 41.175 239.76 41.445 ;
     RECT  2.16 41.715 41.148 41.985 ;
     RECT  218.052 41.715 239.76 41.985 ;
     RECT  2.16 42.255 41.148 42.525 ;
     RECT  218.052 42.255 239.76 42.525 ;
     RECT  2.16 42.795 41.148 43.065 ;
     RECT  218.052 42.795 239.76 43.065 ;
     RECT  2.16 43.335 41.148 43.605 ;
     RECT  218.052 43.335 239.76 43.605 ;
     RECT  2.16 43.875 41.148 44.145 ;
     RECT  218.052 43.875 239.76 44.145 ;
     RECT  2.16 44.415 41.148 44.685 ;
     RECT  218.052 44.415 239.76 44.685 ;
     RECT  2.16 44.955 41.148 45.225 ;
     RECT  218.052 44.955 239.76 45.225 ;
     RECT  2.16 45.495 41.148 45.765 ;
     RECT  218.052 45.495 239.76 45.765 ;
     RECT  2.16 46.035 41.148 46.305 ;
     RECT  218.052 46.035 239.76 46.305 ;
     RECT  2.16 46.575 41.148 46.845 ;
     RECT  218.052 46.575 239.76 46.845 ;
     RECT  2.16 47.115 41.148 47.385 ;
     RECT  218.052 47.115 239.76 47.385 ;
     RECT  2.16 47.655 41.148 47.925 ;
     RECT  218.052 47.655 239.76 47.925 ;
     RECT  2.16 48.195 41.148 48.465 ;
     RECT  218.052 48.195 239.76 48.465 ;
     RECT  2.16 48.735 41.148 49.005 ;
     RECT  218.052 48.735 239.76 49.005 ;
     RECT  2.16 49.275 41.148 49.545 ;
     RECT  218.052 49.275 239.76 49.545 ;
     RECT  2.16 49.815 41.148 50.085 ;
     RECT  218.052 49.815 239.76 50.085 ;
     RECT  2.16 50.355 41.148 50.625 ;
     RECT  218.052 50.355 239.76 50.625 ;
     RECT  2.16 50.895 41.148 51.165 ;
     RECT  218.052 50.895 239.76 51.165 ;
     RECT  2.16 51.435 41.148 51.705 ;
     RECT  218.052 51.435 239.76 51.705 ;
     RECT  2.16 51.975 41.148 52.245 ;
     RECT  218.052 51.975 239.76 52.245 ;
     RECT  2.16 52.515 41.148 52.785 ;
     RECT  218.052 52.515 239.76 52.785 ;
     RECT  2.16 53.055 41.148 53.325 ;
     RECT  218.052 53.055 239.76 53.325 ;
     RECT  2.16 53.595 41.148 53.865 ;
     RECT  218.052 53.595 239.76 53.865 ;
     RECT  2.16 54.135 41.148 54.405 ;
     RECT  218.052 54.135 239.76 54.405 ;
     RECT  2.16 54.675 41.148 54.945 ;
     RECT  218.052 54.675 239.76 54.945 ;
     RECT  2.16 55.215 41.148 55.485 ;
     RECT  218.052 55.215 239.76 55.485 ;
     RECT  2.16 55.755 41.148 56.025 ;
     RECT  218.052 55.755 239.76 56.025 ;
     RECT  2.16 56.295 41.148 56.565 ;
     RECT  218.052 56.295 239.76 56.565 ;
     RECT  2.16 56.835 41.148 57.105 ;
     RECT  218.052 56.835 239.76 57.105 ;
     RECT  2.16 57.375 41.148 57.645 ;
     RECT  218.052 57.375 239.76 57.645 ;
     RECT  2.16 57.915 41.148 58.185 ;
     RECT  218.052 57.915 239.76 58.185 ;
     RECT  2.16 58.455 41.148 58.725 ;
     RECT  218.052 58.455 239.76 58.725 ;
     RECT  2.16 58.995 41.148 59.265 ;
     RECT  218.052 58.995 239.76 59.265 ;
     RECT  2.16 59.535 41.148 59.805 ;
     RECT  218.052 59.535 239.76 59.805 ;
     RECT  2.16 60.075 41.148 60.345 ;
     RECT  218.052 60.075 239.76 60.345 ;
     RECT  2.16 60.615 41.148 60.885 ;
     RECT  218.052 60.615 239.76 60.885 ;
     RECT  2.16 61.155 41.148 61.425 ;
     RECT  218.052 61.155 239.76 61.425 ;
     RECT  2.16 61.695 41.148 61.965 ;
     RECT  218.052 61.695 239.76 61.965 ;
     RECT  2.16 62.235 41.148 62.505 ;
     RECT  218.052 62.235 239.76 62.505 ;
     RECT  2.16 62.775 41.148 63.045 ;
     RECT  218.052 62.775 239.76 63.045 ;
     RECT  2.16 63.315 41.148 63.585 ;
     RECT  218.052 63.315 239.76 63.585 ;
     RECT  2.16 63.855 41.148 64.125 ;
     RECT  218.052 63.855 239.76 64.125 ;
     RECT  2.16 64.395 41.148 64.665 ;
     RECT  218.052 64.395 239.76 64.665 ;
     RECT  2.16 64.935 239.76 65.205 ;
     RECT  2.16 65.475 239.76 65.745 ;
     RECT  2.16 66.015 239.76 66.285 ;
     RECT  2.16 66.555 239.76 66.825 ;
     RECT  2.16 67.095 239.76 67.365 ;
     RECT  2.16 67.635 239.76 67.905 ;
     RECT  2.16 68.175 239.76 68.445 ;
     RECT  2.16 68.715 239.76 68.985 ;
     RECT  2.16 69.255 239.76 69.525 ;
     RECT  2.16 69.795 239.76 70.065 ;
     RECT  2.16 70.335 239.76 70.605 ;
     RECT  2.16 70.875 239.76 71.145 ;
     RECT  2.16 71.415 239.76 71.685 ;
     RECT  2.16 71.955 239.76 72.225 ;
     RECT  2.16 72.495 239.76 72.765 ;
     RECT  2.16 73.035 239.76 73.305 ;
     RECT  2.16 73.575 239.76 73.845 ;
     RECT  2.16 74.115 239.76 74.385 ;
     RECT  2.16 74.655 239.76 74.925 ;
     RECT  2.16 75.195 239.76 75.465 ;
     RECT  2.16 75.735 239.76 76.005 ;
     RECT  2.16 76.275 239.76 76.545 ;
     RECT  2.16 76.815 239.76 77.085 ;
     RECT  2.16 77.355 239.76 77.625 ;
     RECT  2.16 77.895 239.76 78.165 ;
     RECT  2.16 78.435 239.76 78.705 ;
     RECT  2.16 78.975 239.76 79.245 ;
     RECT  2.16 79.515 239.76 79.785 ;
     RECT  2.16 80.055 239.76 80.325 ;
     RECT  2.16 80.595 239.76 80.865 ;
     RECT  2.16 81.135 239.76 81.405 ;
     RECT  2.16 81.675 239.76 81.945 ;
     RECT  2.16 82.215 239.76 82.485 ;
     RECT  2.16 82.755 239.76 83.025 ;
     RECT  2.16 83.295 239.76 83.565 ;
     RECT  2.16 83.835 239.76 84.105 ;
    LAYER M1 ;
     RECT  2.16 2.151 239.76 19.449 ;
     RECT  43.2 21.6 216.024 62.664 ;
     RECT  2.16 19.449 41.148 64.791 ;
     RECT  218.052 19.449 239.76 64.791 ;
     RECT  2.16 64.791 239.76 84.249 ;
    LAYER M2 ;
     RECT  0.103 22.626 0.139 25.2 ;
     RECT  0.103 26.028 0.139 27.9 ;
     RECT  0.103 30.042 0.139 31.14 ;
     RECT  0.103 47.862 0.139 47.88 ;
     RECT  0.103 48.78 0.139 52.74 ;
     RECT  0.103 53.91 0.139 60.3 ;
     RECT  0.139 15.3 0.175 15.318 ;
     RECT  0.103 16.11 0.175 21.69 ;
     RECT  0.103 28.962 0.211 28.98 ;
     RECT  0.139 30.042 0.211 31.176 ;
     RECT  0.211 28.962 0.499 31.176 ;
     RECT  0.103 31.932 0.499 34.884 ;
     RECT  0.139 47.862 0.499 52.74 ;
     RECT  0.175 15.3 0.535 21.69 ;
     RECT  0.139 22.626 0.535 27.9 ;
     RECT  0.103 37.602 0.535 37.62 ;
     RECT  0.499 47.862 0.535 52.884 ;
     RECT  0.139 53.802 0.535 60.336 ;
     RECT  0.535 15.3 1.147 27.9 ;
     RECT  0.499 28.962 1.147 34.884 ;
     RECT  0.139 35.676 1.147 35.694 ;
     RECT  1.147 28.962 1.723 35.694 ;
     RECT  0.535 47.862 1.723 60.336 ;
     RECT  1.723 28.962 1.759 36.144 ;
     RECT  0.535 36.936 1.759 37.962 ;
     RECT  1.147 15.3 2.16 28.044 ;
     RECT  1.759 28.962 2.16 37.962 ;
     RECT  1.723 47.7 2.16 60.336 ;
     RECT  2.16 2.151 41.148 84.249 ;
     RECT  41.148 23.058 41.423 35.028 ;
     RECT  41.148 48.816 41.603 61.614 ;
     RECT  41.423 31.464 41.639 35.028 ;
     RECT  41.148 37.476 41.639 40.158 ;
     RECT  41.148 40.95 41.639 41.274 ;
     RECT  41.603 48.816 41.639 61.38 ;
     RECT  41.639 49.554 41.711 61.38 ;
     RECT  41.148 42.498 41.927 47.61 ;
     RECT  41.423 23.058 42.071 30.636 ;
     RECT  42.071 28.116 42.107 30.636 ;
     RECT  41.639 31.464 42.179 34.722 ;
     RECT  41.639 40.95 42.179 41.202 ;
     RECT  41.711 56.916 42.179 61.38 ;
     RECT  41.148 2.151 42.215 22.068 ;
     RECT  42.071 23.058 42.215 27.36 ;
     RECT  42.179 32.076 42.215 34.722 ;
     RECT  41.639 37.476 42.215 40.086 ;
     RECT  41.927 43.038 42.215 47.61 ;
     RECT  41.711 49.554 42.215 56.124 ;
     RECT  42.179 56.916 42.215 60.912 ;
     RECT  42.215 32.706 42.251 34.722 ;
     RECT  42.179 40.986 42.251 41.202 ;
     RECT  42.215 44.928 42.251 47.61 ;
     RECT  42.215 49.788 42.251 50.274 ;
     RECT  42.215 51.066 42.251 51.264 ;
     RECT  42.215 56.961 42.251 60.912 ;
     RECT  42.251 44.928 42.287 47.034 ;
     RECT  42.215 52.056 42.323 52.614 ;
     RECT  42.215 23.13 42.395 27.36 ;
     RECT  42.215 2.151 42.467 21.924 ;
     RECT  42.467 2.151 43.2 21.564 ;
     RECT  42.395 23.13 43.2 23.148 ;
     RECT  42.395 23.904 43.2 27.36 ;
     RECT  42.107 28.224 43.2 30.636 ;
     RECT  42.251 32.706 43.2 34.182 ;
     RECT  42.215 37.674 43.2 40.086 ;
     RECT  42.251 41.184 43.2 41.202 ;
     RECT  42.215 43.038 43.2 43.056 ;
     RECT  42.215 43.848 43.2 44.136 ;
     RECT  42.287 44.928 43.2 46.494 ;
     RECT  42.251 49.788 43.2 50.076 ;
     RECT  42.251 51.066 43.2 51.084 ;
     RECT  42.323 52.056 43.2 52.2 ;
     RECT  42.215 55.386 43.2 56.124 ;
     RECT  42.251 56.961 43.2 56.979 ;
     RECT  42.251 57.816 43.2 58.95 ;
     RECT  42.251 60.12 43.2 60.912 ;
     RECT  43.2 2.151 216.024 62.664 ;
     RECT  216.024 29.736 216.383 29.754 ;
     RECT  216.024 2.151 216.527 21.492 ;
     RECT  216.024 24.516 216.635 24.966 ;
     RECT  216.527 2.151 216.743 21.069 ;
     RECT  216.635 24.516 216.851 24.534 ;
     RECT  216.024 46.512 217.147 52.704 ;
     RECT  216.024 53.532 217.147 57.87 ;
     RECT  216.024 34.326 217.183 42.21 ;
     RECT  216.024 43.272 217.183 43.29 ;
     RECT  217.147 46.512 217.183 57.87 ;
     RECT  216.024 58.896 217.183 59.76 ;
     RECT  216.024 44.352 217.759 45.684 ;
     RECT  217.183 46.512 217.759 59.76 ;
     RECT  216.024 61.362 217.759 61.38 ;
     RECT  216.024 62.136 217.759 62.154 ;
     RECT  217.759 61.128 217.831 62.154 ;
     RECT  216.743 2.151 218.052 21.024 ;
     RECT  217.183 34.326 218.052 43.29 ;
     RECT  217.759 44.19 218.052 60.066 ;
     RECT  217.831 61.128 218.052 62.46 ;
     RECT  41.148 64.791 218.052 84.249 ;
     RECT  218.052 2.151 239.76 84.249 ;
    LAYER M3 ;
     RECT  2.415 2.143 2.505 2.413 ;
     RECT  7.815 2.143 7.905 2.413 ;
     RECT  13.215 2.143 13.305 2.413 ;
     RECT  18.615 2.143 18.705 2.413 ;
     RECT  24.015 2.143 24.105 2.413 ;
     RECT  29.415 2.143 29.505 2.413 ;
     RECT  34.815 2.143 34.905 2.413 ;
     RECT  40.215 2.143 40.305 2.413 ;
     RECT  45.615 2.143 45.705 2.413 ;
     RECT  51.015 2.143 51.105 2.413 ;
     RECT  56.415 2.143 56.505 2.413 ;
     RECT  61.815 2.143 61.905 2.413 ;
     RECT  67.215 2.143 67.305 2.413 ;
     RECT  72.615 2.143 72.705 2.413 ;
     RECT  78.015 2.143 78.105 2.413 ;
     RECT  83.415 2.143 83.505 2.413 ;
     RECT  88.815 2.143 88.905 2.413 ;
     RECT  94.215 2.143 94.305 2.413 ;
     RECT  99.615 2.143 99.705 2.413 ;
     RECT  105.015 2.143 105.105 2.413 ;
     RECT  110.415 2.143 110.505 2.413 ;
     RECT  115.815 2.143 115.905 2.413 ;
     RECT  121.215 2.143 121.305 2.413 ;
     RECT  126.615 2.143 126.705 2.413 ;
     RECT  132.015 2.143 132.105 2.413 ;
     RECT  137.415 2.143 137.505 2.413 ;
     RECT  142.815 2.143 142.905 2.413 ;
     RECT  148.215 2.143 148.305 2.413 ;
     RECT  153.615 2.143 153.705 2.413 ;
     RECT  159.015 2.143 159.105 2.413 ;
     RECT  164.415 2.143 164.505 2.413 ;
     RECT  169.815 2.143 169.905 2.413 ;
     RECT  175.215 2.143 175.305 2.413 ;
     RECT  180.615 2.143 180.705 2.413 ;
     RECT  186.015 2.143 186.105 2.413 ;
     RECT  191.415 2.143 191.505 2.413 ;
     RECT  196.815 2.143 196.905 2.413 ;
     RECT  202.215 2.143 202.305 2.413 ;
     RECT  207.615 2.143 207.705 2.413 ;
     RECT  213.015 2.143 213.105 2.413 ;
     RECT  218.415 2.143 218.505 2.413 ;
     RECT  223.815 2.143 223.905 2.413 ;
     RECT  229.215 2.143 229.305 2.413 ;
     RECT  234.615 2.143 234.705 2.413 ;
     RECT  218.415 2.413 218.697 11.371 ;
     RECT  110.415 2.413 110.697 13.525 ;
     RECT  67.215 2.413 67.497 13.531 ;
     RECT  78.015 2.413 78.297 13.531 ;
     RECT  99.615 2.413 99.897 13.531 ;
     RECT  121.215 2.413 121.497 13.531 ;
     RECT  132.015 2.413 132.297 13.531 ;
     RECT  142.815 2.413 143.097 13.531 ;
     RECT  153.615 2.413 153.897 13.531 ;
     RECT  164.415 2.413 164.697 13.531 ;
     RECT  175.215 2.413 175.497 13.531 ;
     RECT  186.015 2.413 186.297 13.531 ;
     RECT  196.815 2.413 197.097 13.531 ;
     RECT  207.615 2.413 207.897 13.531 ;
     RECT  86.004 13.387 86.022 13.559 ;
     RECT  87.12 13.387 87.138 13.559 ;
     RECT  82.656 13.387 82.674 13.565 ;
     RECT  90.612 13.387 90.63 13.565 ;
     RECT  110.304 13.525 110.697 13.565 ;
     RECT  67.104 13.531 67.497 13.568 ;
     RECT  77.904 13.531 78.297 13.568 ;
     RECT  121.104 13.531 121.497 13.568 ;
     RECT  131.904 13.531 132.297 13.568 ;
     RECT  142.704 13.531 143.097 13.568 ;
     RECT  153.504 13.531 153.897 13.568 ;
     RECT  164.304 13.531 164.697 13.568 ;
     RECT  175.104 13.531 175.497 13.568 ;
     RECT  185.904 13.531 186.297 13.568 ;
     RECT  196.704 13.531 197.097 13.568 ;
     RECT  207.504 13.531 207.897 13.568 ;
     RECT  105.015 2.413 105.297 13.639 ;
     RECT  218.415 11.371 218.862 13.639 ;
     RECT  84.564 11.371 84.582 14.071 ;
     RECT  109.008 13.603 109.026 14.071 ;
     RECT  109.008 14.071 109.422 14.107 ;
     RECT  115.815 2.413 116.097 14.143 ;
     RECT  86.148 14.107 86.166 14.144 ;
     RECT  11.772 13.603 11.79 14.179 ;
     RECT  108.288 14.107 109.422 14.189 ;
     RECT  83.415 2.413 83.697 14.215 ;
     RECT  84.564 14.071 85.05 14.215 ;
     RECT  114.624 14.071 114.642 14.237 ;
     RECT  9.936 14.143 9.954 14.341 ;
     RECT  115.74 14.143 116.097 14.341 ;
     RECT  115.236 14.341 116.097 14.429 ;
     RECT  114.12 14.395 114.138 14.441 ;
     RECT  78.015 13.568 78.297 14.449 ;
     RECT  82.584 14.44 82.602 14.449 ;
     RECT  9.936 14.341 10.386 14.521 ;
     RECT  11.268 14.179 11.79 14.521 ;
     RECT  82.296 14.449 82.602 14.521 ;
     RECT  81.828 14.521 82.602 14.611 ;
     RECT  81.468 14.611 82.638 14.639 ;
     RECT  13.215 2.413 13.497 14.647 ;
     RECT  78.015 14.449 78.678 14.647 ;
     RECT  83.415 14.215 85.05 14.719 ;
     RECT  82.224 14.639 82.638 14.747 ;
     RECT  83.415 14.719 85.554 14.765 ;
     RECT  81.468 14.639 81.486 14.779 ;
     RECT  24.015 2.413 24.297 14.881 ;
     RECT  9.936 14.521 11.79 14.909 ;
     RECT  82.512 14.747 82.638 14.917 ;
     RECT  83.415 14.765 84.582 14.917 ;
     RECT  99.504 13.531 99.897 15.061 ;
     RECT  132.015 13.568 132.297 15.061 ;
     RECT  142.815 13.568 143.097 15.061 ;
     RECT  153.615 13.568 153.897 15.061 ;
     RECT  169.815 2.413 170.097 15.061 ;
     RECT  175.215 13.568 175.497 15.061 ;
     RECT  196.815 13.568 197.097 15.061 ;
     RECT  86.616 15.061 86.634 15.151 ;
     RECT  88.815 2.413 89.097 15.151 ;
     RECT  98.604 15.061 98.622 15.151 ;
     RECT  105.015 13.639 105.966 15.151 ;
     RECT  110.415 13.565 110.697 15.151 ;
     RECT  118.008 14.755 118.026 15.151 ;
     RECT  121.215 13.568 121.497 15.151 ;
     RECT  130.536 15.061 130.554 15.151 ;
     RECT  132.015 15.061 132.354 15.151 ;
     RECT  138.636 15.061 138.654 15.151 ;
     RECT  142.815 15.061 143.154 15.151 ;
     RECT  150.48 15.061 150.498 15.151 ;
     RECT  153.615 15.061 153.954 15.151 ;
     RECT  164.415 13.568 164.697 15.151 ;
     RECT  169.815 15.061 170.442 15.151 ;
     RECT  175.215 15.061 175.554 15.151 ;
     RECT  186.015 13.568 186.297 15.151 ;
     RECT  194.364 15.061 194.382 15.151 ;
     RECT  196.815 15.061 197.154 15.151 ;
     RECT  207.615 13.568 207.897 15.151 ;
     RECT  218.415 13.639 219.258 15.151 ;
     RECT  40.215 2.413 40.497 15.187 ;
     RECT  41.328 14.755 41.346 15.187 ;
     RECT  85.32 14.765 85.554 15.187 ;
     RECT  218.376 15.151 219.258 15.187 ;
     RECT  88.704 15.151 89.097 15.197 ;
     RECT  99.504 15.061 99.954 15.197 ;
     RECT  110.304 15.151 110.718 15.197 ;
     RECT  121.104 15.151 121.497 15.197 ;
     RECT  131.904 15.151 132.354 15.197 ;
     RECT  142.704 15.151 143.154 15.197 ;
     RECT  153.504 15.151 153.954 15.197 ;
     RECT  164.304 15.151 164.697 15.197 ;
     RECT  175.104 15.151 175.554 15.197 ;
     RECT  185.904 15.151 186.297 15.197 ;
     RECT  196.704 15.151 197.154 15.197 ;
     RECT  207.504 15.151 207.897 15.197 ;
     RECT  98.604 15.151 98.694 15.215 ;
     RECT  99.576 15.197 99.954 15.215 ;
     RECT  130.536 15.151 130.626 15.215 ;
     RECT  132.015 15.197 132.354 15.215 ;
     RECT  138.564 15.151 138.654 15.215 ;
     RECT  142.815 15.197 143.154 15.215 ;
     RECT  150.48 15.151 150.57 15.215 ;
     RECT  153.615 15.197 153.954 15.215 ;
     RECT  175.215 15.197 175.554 15.215 ;
     RECT  194.364 15.151 194.454 15.215 ;
     RECT  196.815 15.197 197.154 15.215 ;
     RECT  4.176 15.151 4.194 15.223 ;
     RECT  86.616 15.151 86.706 15.251 ;
     RECT  98.676 15.215 98.694 15.251 ;
     RECT  105.015 15.151 106.686 15.251 ;
     RECT  110.415 15.197 110.718 15.251 ;
     RECT  118.008 15.151 118.638 15.251 ;
     RECT  130.608 15.215 130.626 15.251 ;
     RECT  138.564 15.215 138.582 15.251 ;
     RECT  150.552 15.215 150.57 15.251 ;
     RECT  162.504 15.151 162.522 15.251 ;
     RECT  169.815 15.151 170.514 15.251 ;
     RECT  182.448 15.151 182.466 15.251 ;
     RECT  194.436 15.215 194.454 15.251 ;
     RECT  206.388 15.151 206.406 15.251 ;
     RECT  218.304 15.187 219.258 15.295 ;
     RECT  218.124 15.295 219.258 15.331 ;
     RECT  85.32 15.187 85.878 15.359 ;
     RECT  4.176 15.223 4.518 15.421 ;
     RECT  0.144 15.295 0.162 15.457 ;
     RECT  39.024 15.331 39.042 15.457 ;
     RECT  81.18 14.779 81.486 15.457 ;
     RECT  85.32 15.359 85.554 15.485 ;
     RECT  4.176 15.421 4.59 15.529 ;
     RECT  78.015 14.647 78.75 15.557 ;
     RECT  81.036 15.457 81.486 15.557 ;
     RECT  2.415 2.413 2.697 15.601 ;
     RECT  6.264 15.529 6.282 15.601 ;
     RECT  34.815 2.413 35.097 15.685 ;
     RECT  24.015 14.881 24.534 15.691 ;
     RECT  39.024 15.457 39.474 15.691 ;
     RECT  34.704 15.685 35.097 15.725 ;
     RECT  3.78 15.529 4.59 15.727 ;
     RECT  6.084 15.601 6.282 15.727 ;
     RECT  40.215 15.187 41.346 15.727 ;
     RECT  23.904 15.691 24.534 15.728 ;
     RECT  38.772 15.691 39.474 15.799 ;
     RECT  40.215 15.727 41.634 15.799 ;
     RECT  38.772 15.799 41.634 15.821 ;
     RECT  43.128 15.727 43.146 15.827 ;
     RECT  5.832 15.727 6.282 15.835 ;
     RECT  39.024 15.821 41.634 15.835 ;
     RECT  81.072 15.557 81.486 15.835 ;
     RECT  82.512 14.917 84.582 15.835 ;
     RECT  217.584 15.331 219.258 15.835 ;
     RECT  2.415 15.601 2.826 15.871 ;
     RECT  3.564 15.727 4.59 15.871 ;
     RECT  5.58 15.835 6.282 15.871 ;
     RECT  217.296 15.835 219.258 15.871 ;
     RECT  220.212 15.799 220.23 15.871 ;
     RECT  5.472 15.871 6.282 15.961 ;
     RECT  10.152 14.909 11.79 15.961 ;
     RECT  43.056 15.871 43.074 15.965 ;
     RECT  214.344 15.787 214.362 15.965 ;
     RECT  5.472 15.961 7.002 15.997 ;
     RECT  7.815 2.413 8.097 15.997 ;
     RECT  9.108 14.215 9.126 15.997 ;
     RECT  9.936 15.961 11.79 15.997 ;
     RECT  5.472 15.997 7.074 16.069 ;
     RECT  7.815 15.997 11.79 16.069 ;
     RECT  78.015 15.557 78.678 16.097 ;
     RECT  0.144 15.457 0.558 16.105 ;
     RECT  86.616 15.251 86.634 16.141 ;
     RECT  2.415 15.871 4.59 16.231 ;
     RECT  81.072 15.835 84.582 16.267 ;
     RECT  85.536 15.485 85.554 16.267 ;
     RECT  2.268 16.231 4.59 16.303 ;
     RECT  5.472 16.069 11.79 16.303 ;
     RECT  81.072 16.267 85.554 16.304 ;
     RECT  39.024 15.835 41.886 16.339 ;
     RECT  217.296 15.871 220.23 16.339 ;
     RECT  86.544 16.141 86.634 16.375 ;
     RECT  2.232 16.303 4.59 16.501 ;
     RECT  5.436 16.303 11.79 16.501 ;
     RECT  216.828 16.339 220.23 16.501 ;
     RECT  24.015 15.728 24.534 16.537 ;
     RECT  39.024 16.339 41.958 16.609 ;
     RECT  15.408 16.645 15.426 16.681 ;
     RECT  87.588 16.645 87.606 16.681 ;
     RECT  105.015 15.251 105.966 16.681 ;
     RECT  216.828 16.501 220.338 16.681 ;
     RECT  86.508 16.375 86.634 16.771 ;
     RECT  87.516 16.681 87.606 16.799 ;
     RECT  80.244 16.771 80.262 16.807 ;
     RECT  81.072 16.304 84.474 16.807 ;
     RECT  87.588 16.799 87.606 16.835 ;
     RECT  38.448 16.609 41.958 16.879 ;
     RECT  96.408 14.215 96.426 16.915 ;
     RECT  38.448 16.879 41.994 16.951 ;
     RECT  80.244 16.807 84.474 17.075 ;
     RECT  80.244 17.075 84.438 17.105 ;
     RECT  78.015 16.097 78.297 17.221 ;
     RECT  79.236 16.411 79.254 17.221 ;
     RECT  1.728 16.501 11.79 17.261 ;
     RECT  86.508 16.771 86.67 17.311 ;
     RECT  88.815 15.197 89.097 17.311 ;
     RECT  99.576 15.215 99.897 17.311 ;
     RECT  104.292 16.681 105.966 17.311 ;
     RECT  110.415 15.251 110.697 17.311 ;
     RECT  118.008 15.251 118.026 17.311 ;
     RECT  121.215 15.197 121.497 17.311 ;
     RECT  132.015 15.215 132.297 17.311 ;
     RECT  142.815 15.215 143.097 17.311 ;
     RECT  153.615 15.215 153.897 17.311 ;
     RECT  164.415 15.197 164.697 17.311 ;
     RECT  169.815 15.251 170.097 17.311 ;
     RECT  175.215 15.215 175.497 17.311 ;
     RECT  186.015 15.197 186.297 17.311 ;
     RECT  196.815 15.215 197.097 17.311 ;
     RECT  207.615 15.197 207.897 17.311 ;
     RECT  2.376 17.261 11.79 17.347 ;
     RECT  98.676 17.311 98.694 17.347 ;
     RECT  99.504 17.311 99.897 17.347 ;
     RECT  130.608 17.311 130.626 17.347 ;
     RECT  131.904 17.311 132.297 17.347 ;
     RECT  138.564 17.311 138.582 17.347 ;
     RECT  142.704 17.311 143.097 17.347 ;
     RECT  150.552 17.311 150.57 17.347 ;
     RECT  153.504 17.311 153.897 17.347 ;
     RECT  175.104 17.311 175.497 17.347 ;
     RECT  194.436 17.311 194.454 17.347 ;
     RECT  196.704 17.311 197.097 17.347 ;
     RECT  88.704 17.311 89.097 17.357 ;
     RECT  110.304 17.311 110.718 17.357 ;
     RECT  121.104 17.311 121.497 17.357 ;
     RECT  131.904 17.347 132.354 17.357 ;
     RECT  142.704 17.347 143.154 17.357 ;
     RECT  153.504 17.347 153.954 17.357 ;
     RECT  164.304 17.311 164.697 17.357 ;
     RECT  175.104 17.347 175.554 17.357 ;
     RECT  185.904 17.311 186.297 17.357 ;
     RECT  196.704 17.347 197.154 17.357 ;
     RECT  207.504 17.311 207.897 17.357 ;
     RECT  78.015 17.221 79.254 17.371 ;
     RECT  80.244 17.105 84.402 17.371 ;
     RECT  38.448 16.951 42.066 17.383 ;
     RECT  86.508 17.311 86.706 17.411 ;
     RECT  98.604 17.347 98.694 17.411 ;
     RECT  104.292 17.311 106.686 17.411 ;
     RECT  110.415 17.357 110.718 17.411 ;
     RECT  118.008 17.311 118.638 17.411 ;
     RECT  130.536 17.347 130.626 17.411 ;
     RECT  150.48 17.347 150.57 17.411 ;
     RECT  162.504 17.311 162.522 17.411 ;
     RECT  169.815 17.311 170.514 17.411 ;
     RECT  182.448 17.311 182.466 17.411 ;
     RECT  194.364 17.347 194.454 17.411 ;
     RECT  206.388 17.311 206.406 17.411 ;
     RECT  85.248 16.304 85.554 17.455 ;
     RECT  56.415 2.413 56.697 17.467 ;
     RECT  99.504 17.347 99.954 17.483 ;
     RECT  132.015 17.357 132.354 17.483 ;
     RECT  138.564 17.347 138.654 17.483 ;
     RECT  142.815 17.357 143.154 17.483 ;
     RECT  153.615 17.357 153.954 17.483 ;
     RECT  175.215 17.357 175.554 17.483 ;
     RECT  196.815 17.357 197.154 17.483 ;
     RECT  137.415 2.413 137.697 17.887 ;
     RECT  15.3 16.681 15.426 17.923 ;
     RECT  16.308 15.763 16.326 17.923 ;
     RECT  107.784 17.689 107.802 17.923 ;
     RECT  216.396 16.681 220.338 17.923 ;
     RECT  98.604 17.411 98.622 17.981 ;
     RECT  104.292 17.411 106.614 17.981 ;
     RECT  118.008 17.411 118.602 17.981 ;
     RECT  130.536 17.411 130.554 17.981 ;
     RECT  138.528 17.851 138.546 17.981 ;
     RECT  150.48 17.411 150.498 17.981 ;
     RECT  162.468 17.851 162.486 17.981 ;
     RECT  169.815 17.411 170.442 17.981 ;
     RECT  182.412 17.851 182.43 17.981 ;
     RECT  194.364 17.411 194.382 17.981 ;
     RECT  206.352 17.851 206.37 17.981 ;
     RECT  0.108 16.105 0.558 17.987 ;
     RECT  2.376 17.347 12.258 17.995 ;
     RECT  75.06 15.835 75.078 17.995 ;
     RECT  90.54 17.959 90.558 18.149 ;
     RECT  74.736 17.995 75.078 18.185 ;
     RECT  87.732 17.959 87.75 18.185 ;
     RECT  86.508 17.411 86.67 18.427 ;
     RECT  216.288 17.923 220.338 18.427 ;
     RECT  85.176 17.455 85.554 18.463 ;
     RECT  85.14 18.463 85.554 18.535 ;
     RECT  86.508 18.427 86.706 18.535 ;
     RECT  2.304 17.995 12.258 18.563 ;
     RECT  126.615 2.413 126.897 18.571 ;
     RECT  216.288 18.427 220.41 18.571 ;
     RECT  78.015 17.371 84.402 18.661 ;
     RECT  85.14 18.535 86.706 18.661 ;
     RECT  96.408 16.915 96.678 18.689 ;
     RECT  13.032 14.647 13.497 18.697 ;
     RECT  115.815 14.429 116.097 18.697 ;
     RECT  15.3 17.923 16.326 18.733 ;
     RECT  101.916 14.179 101.934 18.805 ;
     RECT  61.815 2.413 62.097 18.811 ;
     RECT  104.292 17.981 105.966 18.841 ;
     RECT  110.415 17.411 110.697 18.841 ;
     RECT  38.448 17.383 42.642 18.907 ;
     RECT  38.448 18.907 43.65 18.931 ;
     RECT  78.015 18.661 86.706 18.931 ;
     RECT  94.215 2.413 94.497 18.931 ;
     RECT  111.96 14.143 111.978 18.931 ;
     RECT  0.108 17.987 0.414 18.955 ;
     RECT  45.615 2.413 45.897 18.955 ;
     RECT  70.812 13.627 70.83 18.955 ;
     RECT  101.916 18.805 102.654 18.955 ;
     RECT  98.676 18.841 98.694 18.967 ;
     RECT  104.292 18.841 106.002 18.967 ;
     RECT  111.888 18.931 111.978 18.967 ;
     RECT  115.128 18.697 116.097 18.967 ;
     RECT  118.008 17.981 118.026 18.967 ;
     RECT  109.008 14.189 109.026 19.003 ;
     RECT  118.008 18.967 118.278 19.003 ;
     RECT  38.448 18.931 43.686 19.031 ;
     RECT  15.3 18.733 16.398 19.039 ;
     RECT  132.015 17.483 132.297 19.039 ;
     RECT  150.084 19.003 150.102 19.051 ;
     RECT  98.604 18.967 98.694 19.067 ;
     RECT  101.916 18.955 102.726 19.067 ;
     RECT  114.588 18.967 116.226 19.067 ;
     RECT  102.672 19.067 102.726 19.075 ;
     RECT  110.415 18.841 111.15 19.075 ;
     RECT  111.888 18.967 112.05 19.075 ;
     RECT  137.415 17.887 137.79 19.099 ;
     RECT  44.46 18.841 44.478 19.111 ;
     RECT  56.415 17.467 57.006 19.111 ;
     RECT  61.668 18.811 62.097 19.111 ;
     RECT  64.908 17.419 64.926 19.111 ;
     RECT  67.215 13.568 67.497 19.111 ;
     RECT  70.74 18.955 70.83 19.111 ;
     RECT  121.215 17.357 121.497 19.111 ;
     RECT  122.976 14.791 122.994 19.111 ;
     RECT  45.615 18.955 45.99 19.133 ;
     RECT  14.724 19.039 16.398 19.139 ;
     RECT  78.015 18.931 86.742 19.139 ;
     RECT  45.615 19.133 45.897 19.187 ;
     RECT  51.015 2.413 51.297 19.187 ;
     RECT  61.668 19.111 62.73 19.187 ;
     RECT  66.708 19.111 67.497 19.187 ;
     RECT  88.815 17.357 89.097 19.187 ;
     RECT  104.292 18.967 106.686 19.187 ;
     RECT  125.352 18.571 126.897 19.187 ;
     RECT  142.815 17.483 143.097 19.187 ;
     RECT  148.215 2.413 148.497 19.187 ;
     RECT  153.615 17.483 153.897 19.187 ;
     RECT  159.015 2.413 159.297 19.187 ;
     RECT  164.415 17.357 164.697 19.187 ;
     RECT  169.815 17.981 170.097 19.187 ;
     RECT  175.215 17.483 175.497 19.187 ;
     RECT  180.615 2.413 180.897 19.187 ;
     RECT  186.015 17.357 186.297 19.187 ;
     RECT  191.415 2.413 191.697 19.187 ;
     RECT  196.815 17.483 197.097 19.187 ;
     RECT  202.215 2.413 202.497 19.187 ;
     RECT  207.615 17.357 207.897 19.187 ;
     RECT  213.015 2.413 213.297 19.187 ;
     RECT  79.992 19.139 86.742 19.201 ;
     RECT  110.415 19.075 112.05 19.201 ;
     RECT  118.008 19.003 118.638 19.201 ;
     RECT  122.904 19.111 122.994 19.201 ;
     RECT  132.015 19.039 132.822 19.201 ;
     RECT  140.328 19.039 140.346 19.201 ;
     RECT  70.632 19.111 70.83 19.228 ;
     RECT  14.796 19.139 16.398 19.229 ;
     RECT  49.428 14.683 49.446 19.229 ;
     RECT  52.776 18.763 52.794 19.229 ;
     RECT  54.576 18.811 54.594 19.229 ;
     RECT  56.34 19.111 57.006 19.229 ;
     RECT  60.048 18.811 60.066 19.229 ;
     RECT  75.06 18.185 75.078 19.229 ;
     RECT  78.015 19.139 79.218 19.229 ;
     RECT  79.992 19.201 87.39 19.229 ;
     RECT  88.815 19.187 88.974 19.229 ;
     RECT  96.48 18.689 96.678 19.229 ;
     RECT  101.916 19.067 101.934 19.229 ;
     RECT  104.292 19.187 105.105 19.229 ;
     RECT  105.876 19.187 106.686 19.229 ;
     RECT  120.276 19.075 120.294 19.229 ;
     RECT  149.832 19.051 150.102 19.229 ;
     RECT  61.668 19.187 61.905 19.237 ;
     RECT  70.632 19.228 70.866 19.237 ;
     RECT  72.615 2.413 72.897 19.237 ;
     RECT  74.016 18.955 74.034 19.237 ;
     RECT  94.215 18.931 94.554 19.237 ;
     RECT  136.908 19.099 137.79 19.237 ;
     RECT  145.908 19.201 145.926 19.237 ;
     RECT  155.196 19.201 155.214 19.237 ;
     RECT  149.832 19.229 149.85 19.243 ;
     RECT  56.34 19.229 56.505 19.265 ;
     RECT  99.504 17.483 99.897 19.265 ;
     RECT  109.008 19.003 109.098 19.265 ;
     RECT  117.612 19.201 118.638 19.265 ;
     RECT  132.015 19.201 133.074 19.265 ;
     RECT  136.908 19.237 137.862 19.265 ;
     RECT  149.328 19.243 149.85 19.265 ;
     RECT  151.02 19.003 151.038 19.265 ;
     RECT  64.908 19.111 65.574 19.273 ;
     RECT  91.476 19.201 91.494 19.273 ;
     RECT  117.612 19.265 117.63 19.273 ;
     RECT  122.904 19.201 123.246 19.273 ;
     RECT  137.16 19.265 137.862 19.273 ;
     RECT  138.636 19.237 138.654 19.273 ;
     RECT  140.328 19.201 140.526 19.273 ;
     RECT  38.448 19.031 43.65 19.277 ;
     RECT  72.615 19.237 74.034 19.277 ;
     RECT  137.16 19.273 138.654 19.277 ;
     RECT  154.944 19.237 155.214 19.277 ;
     RECT  62.712 19.187 62.73 19.301 ;
     RECT  64.656 19.273 65.574 19.301 ;
     RECT  66.708 19.187 67.305 19.301 ;
     RECT  98.676 19.067 98.694 19.301 ;
     RECT  109.08 19.265 109.098 19.301 ;
     RECT  114.66 19.067 116.226 19.301 ;
     RECT  134.532 19.039 134.55 19.301 ;
     RECT  29.415 2.413 29.697 19.309 ;
     RECT  102.672 19.075 103.158 19.337 ;
     RECT  105.876 19.229 105.894 19.337 ;
     RECT  117.288 19.273 117.63 19.337 ;
     RECT  69.804 19.273 69.822 19.345 ;
     RECT  86.004 19.229 87.39 19.345 ;
     RECT  91.296 19.273 91.494 19.345 ;
     RECT  94.215 19.237 94.806 19.345 ;
     RECT  99.576 19.265 99.897 19.345 ;
     RECT  104.112 19.273 104.13 19.345 ;
     RECT  106.668 19.229 106.686 19.345 ;
     RECT  107.532 17.923 107.802 19.345 ;
     RECT  114.984 19.301 116.226 19.345 ;
     RECT  129.708 19.201 129.726 19.345 ;
     RECT  64.656 19.301 65.502 19.373 ;
     RECT  66.78 19.301 67.305 19.373 ;
     RECT  69.48 19.345 69.822 19.373 ;
     RECT  70.56 19.237 70.866 19.373 ;
     RECT  72.615 19.277 73.926 19.373 ;
     RECT  96.48 19.229 96.498 19.373 ;
     RECT  99.576 19.345 100.098 19.373 ;
     RECT  104.04 19.345 104.13 19.373 ;
     RECT  106.668 19.345 107.874 19.373 ;
     RECT  117.288 19.337 117.306 19.373 ;
     RECT  118.62 19.265 118.638 19.373 ;
     RECT  121.215 19.111 121.77 19.373 ;
     RECT  122.652 19.273 123.246 19.373 ;
     RECT  133.056 19.265 133.074 19.373 ;
     RECT  72.615 19.373 73.746 19.379 ;
     RECT  125.352 19.187 126.705 19.381 ;
     RECT  102.888 19.337 103.158 19.409 ;
     RECT  38.448 19.277 43.326 19.421 ;
     RECT  45.615 19.187 45.705 19.457 ;
     RECT  51.015 19.187 51.105 19.457 ;
     RECT  56.415 19.265 56.505 19.457 ;
     RECT  61.488 19.237 61.905 19.457 ;
     RECT  67.215 19.373 67.305 19.457 ;
     RECT  72.615 19.379 72.705 19.457 ;
     RECT  78.015 19.229 79.038 19.457 ;
     RECT  88.815 19.229 88.905 19.457 ;
     RECT  94.215 19.345 94.878 19.457 ;
     RECT  99.615 19.373 100.098 19.457 ;
     RECT  105.015 19.229 105.105 19.457 ;
     RECT  110.415 19.201 112.77 19.457 ;
     RECT  121.215 19.373 121.698 19.457 ;
     RECT  125.28 19.381 126.705 19.457 ;
     RECT  132.015 19.265 132.105 19.457 ;
     RECT  142.815 19.187 142.905 19.457 ;
     RECT  148.215 19.187 148.305 19.457 ;
     RECT  153.615 19.187 153.705 19.457 ;
     RECT  159.015 19.187 159.105 19.457 ;
     RECT  164.415 19.187 164.505 19.457 ;
     RECT  169.815 19.187 169.905 19.457 ;
     RECT  175.215 19.187 175.305 19.457 ;
     RECT  180.615 19.187 180.705 19.457 ;
     RECT  186.015 19.187 186.105 19.457 ;
     RECT  191.415 19.187 191.505 19.457 ;
     RECT  196.815 19.187 196.905 19.457 ;
     RECT  202.215 19.187 202.305 19.457 ;
     RECT  207.615 19.187 207.705 19.457 ;
     RECT  213.015 19.187 213.105 19.457 ;
     RECT  86.004 19.345 87.822 19.535 ;
     RECT  0.108 18.955 0.558 19.627 ;
     RECT  79.992 19.229 84.906 19.661 ;
     RECT  79.992 19.661 82.062 19.679 ;
     RECT  83.232 19.661 84.906 19.709 ;
     RECT  78.66 19.457 79.038 19.724 ;
     RECT  86.004 19.535 86.166 19.724 ;
     RECT  0.108 19.627 0.666 19.757 ;
     RECT  84.312 19.709 84.906 19.757 ;
     RECT  80.748 19.679 81.63 19.769 ;
     RECT  101.664 19.345 101.682 19.805 ;
     RECT  102.888 19.409 102.906 19.805 ;
     RECT  120.024 19.345 120.042 19.805 ;
     RECT  216.18 18.571 220.41 19.813 ;
     RECT  91.224 19.345 91.494 19.841 ;
     RECT  125.28 19.457 126.27 19.841 ;
     RECT  73.476 19.379 73.746 19.877 ;
     RECT  138.888 19.381 138.906 19.877 ;
     RECT  2.415 18.563 12.258 19.912 ;
     RECT  64.656 19.373 65.43 19.913 ;
     RECT  79.992 19.679 80.01 19.913 ;
     RECT  145.764 19.237 145.926 19.913 ;
     RECT  129.456 19.345 129.726 19.949 ;
     RECT  83.232 19.709 83.25 19.994 ;
     RECT  114.984 19.345 116.262 19.994 ;
     RECT  137.16 19.277 138.114 19.997 ;
     RECT  34.815 15.725 35.097 20.005 ;
     RECT  24.015 16.537 24.786 20.011 ;
     RECT  34.704 20.005 35.097 20.045 ;
     RECT  111.168 19.457 112.77 20.045 ;
     RECT  23.904 20.011 24.786 20.048 ;
     RECT  127.116 19.921 127.134 20.075 ;
     RECT  104.04 19.373 104.058 20.111 ;
     RECT  15.3 19.229 16.398 20.119 ;
     RECT  94.68 19.457 94.878 20.147 ;
     RECT  155.196 19.277 155.214 20.147 ;
     RECT  86.94 19.535 87.822 20.183 ;
     RECT  138.096 19.997 138.114 20.183 ;
     RECT  135.072 19.381 135.09 20.189 ;
     RECT  81.612 19.769 81.63 20.219 ;
     RECT  86.94 20.183 87.39 20.219 ;
     RECT  87.12 20.219 87.39 20.237 ;
     RECT  87.12 20.237 87.138 20.264 ;
     RECT  112.212 20.045 112.77 20.264 ;
     RECT  94.68 20.147 94.698 20.309 ;
     RECT  64.656 19.913 64.674 20.317 ;
     RECT  216.108 19.813 220.41 20.317 ;
     RECT  99.828 19.457 100.098 20.345 ;
     RECT  109.26 19.345 109.278 20.345 ;
     RECT  59.904 19.237 59.922 20.381 ;
     RECT  123.228 19.373 123.246 20.381 ;
     RECT  49.176 19.237 49.194 20.417 ;
     RECT  62.712 20.317 62.73 20.417 ;
     RECT  64.404 20.317 64.674 20.417 ;
     RECT  125.604 19.841 126.27 20.417 ;
     RECT  125.676 20.417 126.27 20.453 ;
     RECT  119.124 19.849 119.142 20.489 ;
     RECT  129.708 19.949 129.726 20.489 ;
     RECT  78.66 19.724 78.678 20.579 ;
     RECT  14.724 20.119 16.398 20.651 ;
     RECT  0.108 19.757 0.558 20.683 ;
     RECT  111.168 20.045 111.186 20.687 ;
     RECT  29.415 19.309 30.222 20.695 ;
     RECT  44.46 19.111 44.514 20.723 ;
     RECT  86.148 19.724 86.166 20.804 ;
     RECT  100.08 20.345 100.098 20.804 ;
     RECT  73.728 19.877 73.746 20.813 ;
     RECT  34.815 20.045 35.097 20.827 ;
     RECT  14.796 20.651 16.398 20.849 ;
     RECT  37.584 20.539 37.602 20.849 ;
     RECT  112.752 20.264 112.77 20.849 ;
     RECT  38.448 19.421 42.966 20.857 ;
     RECT  65.412 19.913 65.43 20.861 ;
     RECT  0.108 20.683 1.17 20.957 ;
     RECT  34.776 20.827 35.097 20.957 ;
     RECT  37.224 20.92 37.242 20.957 ;
     RECT  38.448 20.857 43.002 21.046 ;
     RECT  15.3 20.849 16.398 21.361 ;
     RECT  29.415 20.695 30.366 21.361 ;
     RECT  216.072 20.317 220.41 21.361 ;
     RECT  2.304 19.912 12.258 21.499 ;
     RECT  13.032 18.697 13.95 21.499 ;
     RECT  27.036 15.961 27.054 21.499 ;
     RECT  20.628 18.121 20.646 21.505 ;
     RECT  21.708 21.361 21.726 21.505 ;
     RECT  32.508 21.361 32.526 21.505 ;
     RECT  15.3 21.361 17.118 21.569 ;
     RECT  20.628 21.505 21.726 21.569 ;
     RECT  29.415 21.361 30.798 21.569 ;
     RECT  38.448 21.046 43.074 21.6 ;
     RECT  44.496 20.723 44.514 21.6 ;
     RECT  52.524 19.237 52.542 21.6 ;
     RECT  54.396 19.237 54.414 21.6 ;
     RECT  61.488 19.457 61.506 21.6 ;
     RECT  64.404 20.417 64.422 21.6 ;
     RECT  69.48 19.373 69.75 21.6 ;
     RECT  70.56 19.373 70.578 21.6 ;
     RECT  80.748 19.769 80.766 21.6 ;
     RECT  91.476 19.841 91.494 21.6 ;
     RECT  107.28 19.373 107.874 21.6 ;
     RECT  115.596 19.994 116.262 21.6 ;
     RECT  121.428 19.457 121.698 21.6 ;
     RECT  125.676 20.453 125.694 21.6 ;
     RECT  137.16 19.997 137.178 21.6 ;
     RECT  140.256 19.273 140.526 21.6 ;
     RECT  145.908 19.913 145.926 21.6 ;
     RECT  149.328 19.265 149.346 21.6 ;
     RECT  151.272 19.381 151.29 21.6 ;
     RECT  214.344 20.827 214.362 21.6 ;
     RECT  216.036 21.361 220.41 21.6 ;
     RECT  20.628 21.569 21.654 21.629 ;
     RECT  26.748 21.499 27.054 21.629 ;
     RECT  31.932 21.505 32.526 21.629 ;
     RECT  21.636 21.629 21.654 21.659 ;
     RECT  23.184 21.499 23.202 21.659 ;
     RECT  32.436 21.629 32.526 21.659 ;
     RECT  33.984 21.115 34.002 21.659 ;
     RECT  0.108 20.957 0.234 21.695 ;
     RECT  0.144 21.695 0.234 21.733 ;
     RECT  1.152 20.957 1.17 21.733 ;
     RECT  0.144 21.733 1.17 21.839 ;
     RECT  2.304 21.499 13.95 21.929 ;
     RECT  2.304 21.929 12.258 22.009 ;
     RECT  32.616 21.937 32.634 22.267 ;
     RECT  24.015 20.048 24.786 22.459 ;
     RECT  37.62 22.207 37.638 22.469 ;
     RECT  27.036 21.629 27.054 22.577 ;
     RECT  0.144 21.839 0.558 22.603 ;
     RECT  24.015 22.459 24.858 22.603 ;
     RECT  34.815 20.957 35.097 22.603 ;
     RECT  18.615 2.413 18.897 22.621 ;
     RECT  34.704 22.603 35.097 22.649 ;
     RECT  20.628 21.629 20.646 22.711 ;
     RECT  18.252 22.621 18.897 22.747 ;
     RECT  15.3 21.569 16.398 22.819 ;
     RECT  18.252 22.747 19.062 22.819 ;
     RECT  19.98 22.711 20.646 22.819 ;
     RECT  15.3 22.819 17.082 22.855 ;
     RECT  23.904 22.603 24.858 22.855 ;
     RECT  15.3 22.855 17.154 22.891 ;
     RECT  18.252 22.819 20.862 22.891 ;
     RECT  14.904 22.891 17.514 22.981 ;
     RECT  18.252 22.891 20.97 22.981 ;
     RECT  22.536 22.843 22.554 22.987 ;
     RECT  14.832 22.981 17.514 23.017 ;
     RECT  18.252 22.981 21.078 23.017 ;
     RECT  22.176 22.987 22.554 23.017 ;
     RECT  23.688 22.855 24.858 23.017 ;
     RECT  1.728 22.009 12.258 23.021 ;
     RECT  29.415 21.569 30.366 23.431 ;
     RECT  36.468 22.555 36.486 23.459 ;
     RECT  29.415 23.431 30.726 23.549 ;
     RECT  14.832 23.017 24.858 23.629 ;
     RECT  25.92 22.513 25.938 23.701 ;
     RECT  32.616 22.267 33.066 23.729 ;
     RECT  27.54 23.701 27.558 23.791 ;
     RECT  27.468 23.791 27.558 23.819 ;
     RECT  14.832 23.629 24.894 23.927 ;
     RECT  2.268 23.021 12.258 23.935 ;
     RECT  13.032 21.929 13.95 23.935 ;
     RECT  14.832 23.927 24.858 23.971 ;
     RECT  14.796 23.971 24.858 24.088 ;
     RECT  2.268 23.935 13.95 24.097 ;
     RECT  14.76 24.088 24.858 24.097 ;
     RECT  0.108 22.603 0.558 24.173 ;
     RECT  29.415 23.549 30.366 24.205 ;
     RECT  34.815 22.649 35.097 24.325 ;
     RECT  34.704 24.325 35.097 24.365 ;
     RECT  2.268 24.097 24.858 24.539 ;
     RECT  25.92 23.701 26.478 24.601 ;
     RECT  27.468 23.819 27.486 24.601 ;
     RECT  25.92 24.601 27.486 24.629 ;
     RECT  25.92 24.629 27.414 24.773 ;
     RECT  25.92 24.773 26.478 24.899 ;
     RECT  0.108 24.173 0.162 24.901 ;
     RECT  38.448 21.6 220.41 24.971 ;
     RECT  2.304 24.539 24.858 24.979 ;
     RECT  2.304 24.979 25.182 25.015 ;
     RECT  25.92 24.899 26.01 25.015 ;
     RECT  0.108 24.901 0.558 25.249 ;
     RECT  2.304 25.015 26.01 25.519 ;
     RECT  0.108 25.249 1.206 25.583 ;
     RECT  2.268 25.519 26.01 25.709 ;
     RECT  37.008 24.241 37.026 25.717 ;
     RECT  37.008 25.717 37.422 25.889 ;
     RECT  1.152 25.583 1.206 25.963 ;
     RECT  2.304 25.709 26.01 25.979 ;
     RECT  0.108 25.583 0.162 26.045 ;
     RECT  2.304 25.979 17.406 26.051 ;
     RECT  18.18 25.979 25.938 26.087 ;
     RECT  1.152 25.963 1.278 26.093 ;
     RECT  18.612 26.087 25.938 26.123 ;
     RECT  12.492 26.051 17.406 26.159 ;
     RECT  1.152 26.093 1.17 26.237 ;
     RECT  32.616 23.729 32.634 26.329 ;
     RECT  37.008 25.889 37.062 26.365 ;
     RECT  38.448 24.971 216.45 26.525 ;
     RECT  36.756 26.365 37.062 26.555 ;
     RECT  18.615 26.123 25.938 26.627 ;
     RECT  37.044 26.555 37.062 26.627 ;
     RECT  13.032 26.159 17.406 26.789 ;
     RECT  27.396 24.773 27.414 26.797 ;
     RECT  0.108 26.045 0.126 26.827 ;
     RECT  14.292 26.789 16.65 26.861 ;
     RECT  26.784 26.797 27.414 26.869 ;
     RECT  26.784 26.869 28.206 26.941 ;
     RECT  28.944 24.205 30.366 26.941 ;
     RECT  32.616 26.329 33.138 26.941 ;
     RECT  38.448 26.525 216.378 27.005 ;
     RECT  32.472 26.941 33.138 27.031 ;
     RECT  14.652 26.861 16.65 27.059 ;
     RECT  34.815 24.365 35.097 27.067 ;
     RECT  0.108 26.827 0.162 27.103 ;
     RECT  0.108 27.103 0.558 27.115 ;
     RECT  26.784 26.941 30.366 27.149 ;
     RECT  32.472 27.031 33.498 27.167 ;
     RECT  34.776 27.067 35.097 27.167 ;
     RECT  217.188 24.971 220.41 27.197 ;
     RECT  28.512 27.149 30.366 27.239 ;
     RECT  0.108 27.115 1.17 27.245 ;
     RECT  19.728 26.627 25.938 27.245 ;
     RECT  31.284 26.833 31.302 27.307 ;
     RECT  20.628 27.245 25.938 27.329 ;
     RECT  26.784 27.149 27.414 27.329 ;
     RECT  28.8 27.239 30.366 27.329 ;
     RECT  31.14 27.307 31.302 27.337 ;
     RECT  32.472 27.167 33.174 27.337 ;
     RECT  20.628 27.329 20.79 27.341 ;
     RECT  14.652 27.059 15.858 27.365 ;
     RECT  18.615 26.627 18.954 27.365 ;
     RECT  21.528 27.329 21.546 27.365 ;
     RECT  31.14 27.337 33.174 27.365 ;
     RECT  2.304 26.051 11.718 27.409 ;
     RECT  22.824 27.329 25.938 27.437 ;
     RECT  37.044 27.409 37.062 27.481 ;
     RECT  217.26 27.197 220.41 27.485 ;
     RECT  0.108 27.245 0.306 27.509 ;
     RECT  32.688 27.365 33.174 27.509 ;
     RECT  2.268 27.409 11.718 27.599 ;
     RECT  2.268 27.599 11.682 27.629 ;
     RECT  0.108 27.509 0.234 27.635 ;
     RECT  31.68 27.365 31.95 27.635 ;
     RECT  32.76 27.509 33.174 27.707 ;
     RECT  22.824 27.437 25.146 27.743 ;
     RECT  22.824 27.743 23.094 27.869 ;
     RECT  24.015 27.743 25.146 27.869 ;
     RECT  31.68 27.635 31.698 27.869 ;
     RECT  0.108 27.635 0.126 27.905 ;
     RECT  22.824 27.869 22.842 27.905 ;
     RECT  25.056 27.869 25.146 27.905 ;
     RECT  13.032 26.789 13.497 27.913 ;
     RECT  1.152 27.245 1.17 28.049 ;
     RECT  217.404 27.485 220.41 28.061 ;
     RECT  20.628 27.341 20.646 28.139 ;
     RECT  37.044 27.481 37.134 28.139 ;
     RECT  38.448 27.005 216.306 28.157 ;
     RECT  2.304 27.629 11.682 28.175 ;
     RECT  18.615 27.365 18.897 28.219 ;
     RECT  37.116 28.139 37.134 28.319 ;
     RECT  217.512 28.061 220.41 28.637 ;
     RECT  34.815 27.167 35.097 28.651 ;
     RECT  16.596 27.059 16.65 28.687 ;
     RECT  217.548 28.637 220.41 28.733 ;
     RECT  16.596 28.687 16.686 28.759 ;
     RECT  34.776 28.651 35.097 28.787 ;
     RECT  16.488 28.759 16.686 28.921 ;
     RECT  38.448 28.157 216.27 28.925 ;
     RECT  0.324 28.843 0.342 28.939 ;
     RECT  2.415 28.175 2.826 28.939 ;
     RECT  3.6 28.175 11.682 28.939 ;
     RECT  2.415 28.939 11.682 28.949 ;
     RECT  26.784 27.329 27.306 28.949 ;
     RECT  33.084 27.707 33.174 28.957 ;
     RECT  34.815 28.787 35.097 28.957 ;
     RECT  35.82 26.599 35.838 28.957 ;
     RECT  0.108 28.939 0.342 28.985 ;
     RECT  16.488 28.921 16.758 28.993 ;
     RECT  14.652 27.365 15.714 29.021 ;
     RECT  217.764 28.733 220.41 29.021 ;
     RECT  13.032 27.913 13.698 29.029 ;
     RECT  14.652 29.021 15.426 29.029 ;
     RECT  16.452 28.993 16.758 29.029 ;
     RECT  16.308 29.029 16.794 29.069 ;
     RECT  13.032 29.029 15.426 29.219 ;
     RECT  34.815 28.957 35.838 29.219 ;
     RECT  0.18 28.985 0.342 29.227 ;
     RECT  16.38 29.069 16.758 29.255 ;
     RECT  34.815 29.219 35.586 29.399 ;
     RECT  217.764 29.021 220.338 29.405 ;
     RECT  25.056 27.905 25.074 29.461 ;
     RECT  25.92 27.437 25.938 29.461 ;
     RECT  25.056 29.461 25.938 29.525 ;
     RECT  2.415 28.949 9.63 29.605 ;
     RECT  38.448 28.925 216.024 29.659 ;
     RECT  20.52 29.605 20.538 29.759 ;
     RECT  38.448 29.659 216.378 29.759 ;
     RECT  38.448 29.759 216.27 29.789 ;
     RECT  1.728 29.605 9.63 29.84 ;
     RECT  0.18 29.227 0.558 29.899 ;
     RECT  37.044 29.803 37.062 29.933 ;
     RECT  0.108 29.899 0.558 30.029 ;
     RECT  18.468 28.219 18.897 30.029 ;
     RECT  28.944 27.329 30.366 30.029 ;
     RECT  217.836 29.405 220.338 30.077 ;
     RECT  13.032 29.219 15.318 30.145 ;
     RECT  16.38 29.255 16.686 30.145 ;
     RECT  10.368 28.949 11.682 30.371 ;
     RECT  2.415 29.84 9.63 30.379 ;
     RECT  10.368 30.371 11.394 30.379 ;
     RECT  32.76 28.957 33.174 30.415 ;
     RECT  0.108 30.029 0.306 30.479 ;
     RECT  13.032 30.145 16.686 30.569 ;
     RECT  32.76 30.415 33.57 30.571 ;
     RECT  0.108 30.479 0.234 30.605 ;
     RECT  32.58 30.571 33.57 30.611 ;
     RECT  33.156 30.611 33.57 30.641 ;
     RECT  2.415 30.379 11.394 30.667 ;
     RECT  34.815 29.399 35.298 30.811 ;
     RECT  2.304 30.667 11.394 30.839 ;
     RECT  25.38 29.525 25.938 30.839 ;
     RECT  34.776 30.811 35.298 30.859 ;
     RECT  2.304 30.839 11.322 30.875 ;
     RECT  33.408 30.641 33.57 30.875 ;
     RECT  34.308 30.859 35.298 30.911 ;
     RECT  25.92 30.839 25.938 30.991 ;
     RECT  34.488 30.911 35.298 31.081 ;
     RECT  34.488 31.081 35.37 31.109 ;
     RECT  0.108 30.605 0.162 31.145 ;
     RECT  0.144 31.145 0.162 31.181 ;
     RECT  1.152 31.243 1.17 31.339 ;
     RECT  0.324 31.339 1.17 31.565 ;
     RECT  13.032 30.569 15.318 31.801 ;
     RECT  2.415 30.875 11.322 31.819 ;
     RECT  13.032 31.801 15.426 31.853 ;
     RECT  13.032 31.853 15.318 31.891 ;
     RECT  0.324 31.565 0.342 31.915 ;
     RECT  25.92 30.991 26.514 31.927 ;
     RECT  27.288 28.949 27.306 31.927 ;
     RECT  16.38 30.569 16.686 31.991 ;
     RECT  28.944 30.029 29.697 31.999 ;
     RECT  12.744 31.891 15.318 32.027 ;
     RECT  19.728 27.245 19.746 32.027 ;
     RECT  2.304 31.819 11.322 32.063 ;
     RECT  25.92 31.927 27.306 32.063 ;
     RECT  1.152 31.565 1.17 32.099 ;
     RECT  25.92 32.063 27.09 32.225 ;
     RECT  25.92 32.225 26.91 32.237 ;
     RECT  28.872 31.999 29.697 32.269 ;
     RECT  38.448 29.789 216.024 32.341 ;
     RECT  13.215 32.027 15.318 32.459 ;
     RECT  28.692 32.269 30.222 32.459 ;
     RECT  2.376 32.063 11.322 32.611 ;
     RECT  2.376 32.611 11.394 32.729 ;
     RECT  2.376 32.729 11.322 32.765 ;
     RECT  217.836 30.077 219.51 32.765 ;
     RECT  0.108 31.915 0.342 32.809 ;
     RECT  37.044 32.737 37.062 32.873 ;
     RECT  34.815 31.109 35.37 32.909 ;
     RECT  0.108 32.809 0.558 33.005 ;
     RECT  38.412 32.341 216.024 33.115 ;
     RECT  220.248 30.077 220.338 33.149 ;
     RECT  38.304 33.115 216.024 33.259 ;
     RECT  28.8 32.459 30.222 33.269 ;
     RECT  38.304 33.259 216.126 33.269 ;
     RECT  33.552 30.875 33.57 33.313 ;
     RECT  218.232 32.765 219.51 33.341 ;
     RECT  38.304 33.269 41.67 33.349 ;
     RECT  18.615 30.029 18.897 33.385 ;
     RECT  219.492 33.341 219.51 33.389 ;
     RECT  33.552 33.313 34.002 33.413 ;
     RECT  14.652 32.459 15.318 33.421 ;
     RECT  2.376 32.765 9.558 33.451 ;
     RECT  33.552 33.413 33.966 33.511 ;
     RECT  12.096 33.421 12.114 33.539 ;
     RECT  14.508 33.421 15.318 33.619 ;
     RECT  30.78 33.313 30.798 33.619 ;
     RECT  33.012 33.511 33.966 33.643 ;
     RECT  18.615 33.385 18.918 33.655 ;
     RECT  26.892 32.237 26.91 33.683 ;
     RECT  13.215 32.459 13.698 33.691 ;
     RECT  14.508 33.619 15.462 33.691 ;
     RECT  13.215 33.691 15.462 33.719 ;
     RECT  0.108 33.005 0.162 33.739 ;
     RECT  34.815 32.909 35.097 33.787 ;
     RECT  13.215 33.719 13.986 33.809 ;
     RECT  15.3 33.719 15.426 33.809 ;
     RECT  18.252 33.655 19.35 33.809 ;
     RECT  2.304 33.451 9.558 33.845 ;
     RECT  15.372 33.809 15.426 33.845 ;
     RECT  2.376 33.845 9.558 33.853 ;
     RECT  10.584 32.765 11.322 33.853 ;
     RECT  34.815 33.787 35.19 33.853 ;
     RECT  220.32 33.149 220.338 33.869 ;
     RECT  30.78 33.619 30.834 33.881 ;
     RECT  30.78 33.881 30.798 33.917 ;
     RECT  15.408 33.845 15.426 33.953 ;
     RECT  0.108 33.739 0.558 34.027 ;
     RECT  18.252 33.809 18.897 34.079 ;
     RECT  36.396 33.925 36.414 34.079 ;
     RECT  26.784 33.925 26.802 34.115 ;
     RECT  34.815 33.853 35.298 34.159 ;
     RECT  32.652 33.643 33.966 34.195 ;
     RECT  34.815 34.159 35.946 34.195 ;
     RECT  218.232 33.341 218.697 34.205 ;
     RECT  37.62 33.349 41.67 34.259 ;
     RECT  42.444 33.269 216.126 34.321 ;
     RECT  2.376 33.853 11.322 34.349 ;
     RECT  32.652 34.195 35.946 34.349 ;
     RECT  32.652 34.349 35.694 34.357 ;
     RECT  37.764 34.259 41.67 34.591 ;
     RECT  42.444 34.321 216.63 34.591 ;
     RECT  2.376 34.349 11.214 34.619 ;
     RECT  13.215 33.809 13.662 34.619 ;
     RECT  0.108 34.027 1.17 34.727 ;
     RECT  2.415 34.619 10.962 34.727 ;
     RECT  13.215 34.619 13.497 34.735 ;
     RECT  16.668 31.991 16.686 34.735 ;
     RECT  16.668 34.735 16.794 34.763 ;
     RECT  10.584 34.727 10.962 34.799 ;
     RECT  0.108 34.727 0.162 34.829 ;
     RECT  13.068 34.735 13.497 34.889 ;
     RECT  0.108 34.829 0.126 34.925 ;
     RECT  37.764 34.591 216.63 34.925 ;
     RECT  1.152 34.727 1.17 34.961 ;
     RECT  13.176 34.889 13.497 34.961 ;
     RECT  37.872 34.925 216.63 35.005 ;
     RECT  10.584 34.799 10.818 35.069 ;
     RECT  37.872 35.005 216.666 35.261 ;
     RECT  28.8 33.269 29.697 35.267 ;
     RECT  26.784 35.131 26.802 35.303 ;
     RECT  37.872 35.261 216.63 35.357 ;
     RECT  32.508 34.357 35.694 35.437 ;
     RECT  37.872 35.357 42.462 35.453 ;
     RECT  31.356 35.131 31.374 35.545 ;
     RECT  42.228 35.453 42.462 35.549 ;
     RECT  10.584 35.069 10.602 35.581 ;
     RECT  32.112 35.437 36.018 35.581 ;
     RECT  32.112 35.581 36.522 35.671 ;
     RECT  31.176 35.545 31.374 35.707 ;
     RECT  30.852 35.707 31.374 35.743 ;
     RECT  10.548 35.581 10.602 35.771 ;
     RECT  218.304 34.205 218.697 35.803 ;
     RECT  30.78 35.743 31.374 35.807 ;
     RECT  32.112 35.671 37.062 35.807 ;
     RECT  34.272 35.807 37.062 35.843 ;
     RECT  30.78 35.807 30.87 35.879 ;
     RECT  34.272 35.843 35.91 36.041 ;
     RECT  32.112 35.807 33.462 36.085 ;
     RECT  2.415 34.727 9.558 36.121 ;
     RECT  35.82 36.041 35.91 36.239 ;
     RECT  0.144 35.671 0.162 36.331 ;
     RECT  35.892 36.239 35.91 36.347 ;
     RECT  218.268 35.803 218.697 36.379 ;
     RECT  31.896 36.085 33.462 36.383 ;
     RECT  30.78 35.879 30.798 36.419 ;
     RECT  37.044 35.843 37.062 36.419 ;
     RECT  0.108 36.331 0.162 36.461 ;
     RECT  32.832 36.383 33.462 36.509 ;
     RECT  1.728 36.121 9.558 36.557 ;
     RECT  31.896 36.383 31.914 36.581 ;
     RECT  0.144 36.461 0.162 36.619 ;
     RECT  33.408 36.509 33.462 36.625 ;
     RECT  34.272 36.041 35.097 36.625 ;
     RECT  0.144 36.619 0.342 36.653 ;
     RECT  217.764 36.379 218.697 36.653 ;
     RECT  28.908 35.267 29.697 36.661 ;
     RECT  1.764 36.557 9.558 36.689 ;
     RECT  0.324 36.653 0.342 36.749 ;
     RECT  33.408 36.625 35.097 36.779 ;
     RECT  24.015 27.869 24.297 36.787 ;
     RECT  31.572 36.661 31.59 36.815 ;
     RECT  28.584 36.661 29.697 36.859 ;
     RECT  26.784 36.787 26.802 36.923 ;
     RECT  33.408 36.779 33.426 36.923 ;
     RECT  28.476 36.859 29.697 36.959 ;
     RECT  0.54 36.931 0.558 37.037 ;
     RECT  34.2 36.779 35.097 37.049 ;
     RECT  1.764 36.689 8.55 37.435 ;
     RECT  218.268 36.653 218.697 37.435 ;
     RECT  23.364 36.787 24.297 37.463 ;
     RECT  42.444 35.549 42.462 37.471 ;
     RECT  42.192 37.471 42.462 37.531 ;
     RECT  1.728 37.435 8.55 37.597 ;
     RECT  9.288 36.689 9.558 37.597 ;
     RECT  0.108 37.579 0.126 37.625 ;
     RECT  42.156 37.531 42.462 37.669 ;
     RECT  43.2 35.357 216.63 37.669 ;
     RECT  37.872 35.453 40.914 37.741 ;
     RECT  1.728 37.597 9.558 37.757 ;
     RECT  42.156 37.669 216.63 37.819 ;
     RECT  2.304 37.757 9.558 37.895 ;
     RECT  0.324 37.771 0.342 37.901 ;
     RECT  18.615 34.079 18.897 37.963 ;
     RECT  217.764 37.435 218.697 37.967 ;
     RECT  0.54 37.939 0.558 37.997 ;
     RECT  29.016 36.959 29.697 38.039 ;
     RECT  14.832 37.963 14.85 38.093 ;
     RECT  2.415 37.895 8.55 38.129 ;
     RECT  2.415 38.129 3.186 38.165 ;
     RECT  18.615 37.963 18.954 38.173 ;
     RECT  18.615 38.173 19.134 38.399 ;
     RECT  42.12 37.819 216.63 38.471 ;
     RECT  218.304 37.967 218.697 38.507 ;
     RECT  42.156 38.471 216.63 38.641 ;
     RECT  42.156 38.641 217.206 39.011 ;
     RECT  3.96 38.129 8.55 39.019 ;
     RECT  3.888 39.019 8.55 39.047 ;
     RECT  2.415 38.165 2.97 39.091 ;
     RECT  3.888 39.047 4.878 39.091 ;
     RECT  37.872 37.741 40.95 39.091 ;
     RECT  37.872 39.091 41.094 39.119 ;
     RECT  2.415 39.091 3.114 39.209 ;
     RECT  2.415 39.209 2.97 39.245 ;
     RECT  3.852 39.091 4.878 39.245 ;
     RECT  3.888 39.245 4.878 39.281 ;
     RECT  42.444 39.011 217.206 39.389 ;
     RECT  218.415 38.507 218.697 39.451 ;
     RECT  4.356 39.281 4.878 39.515 ;
     RECT  38.268 39.119 41.094 40.019 ;
     RECT  42.444 39.389 216.63 40.091 ;
     RECT  38.34 40.019 41.094 40.135 ;
     RECT  38.34 40.135 41.634 40.945 ;
     RECT  42.444 40.091 42.462 40.945 ;
     RECT  38.34 40.945 42.462 41.179 ;
     RECT  43.2 40.091 216.63 41.179 ;
     RECT  38.34 41.179 216.63 41.501 ;
     RECT  38.34 41.501 41.634 41.597 ;
     RECT  42.444 41.501 216.63 41.693 ;
     RECT  38.34 41.597 40.986 41.909 ;
     RECT  43.2 41.693 216.63 41.947 ;
     RECT  43.2 41.947 217.17 42.269 ;
     RECT  42.444 41.693 42.462 42.493 ;
     RECT  218.304 39.451 218.697 42.715 ;
     RECT  218.196 42.715 218.697 42.755 ;
     RECT  41.904 42.493 42.462 42.835 ;
     RECT  217.188 42.565 217.206 42.845 ;
     RECT  38.736 41.909 40.986 42.899 ;
     RECT  41.868 42.835 42.462 43.033 ;
     RECT  43.2 42.269 216.024 43.033 ;
     RECT  38.808 42.899 40.986 43.051 ;
     RECT  41.868 43.033 216.024 43.051 ;
     RECT  5.652 39.047 8.55 43.061 ;
     RECT  38.808 43.051 216.024 43.267 ;
     RECT  38.808 43.267 216.63 43.325 ;
     RECT  13.215 34.961 13.497 43.339 ;
     RECT  13.14 43.339 13.497 43.627 ;
     RECT  218.268 42.755 218.697 43.771 ;
     RECT  13.14 43.627 13.77 43.799 ;
     RECT  38.808 43.325 216.024 43.979 ;
     RECT  16.776 34.763 16.794 44.069 ;
     RECT  39.672 43.979 216.024 44.155 ;
     RECT  217.764 43.771 218.697 44.213 ;
     RECT  39.672 44.155 216.63 44.635 ;
     RECT  9.288 37.895 9.558 44.753 ;
     RECT  39.672 44.635 217.17 44.753 ;
     RECT  218.268 44.213 218.697 45.115 ;
     RECT  5.652 43.061 7.038 45.329 ;
     RECT  38.808 43.979 38.826 45.689 ;
     RECT  217.8 45.115 218.697 45.691 ;
     RECT  34.815 37.049 35.097 45.697 ;
     RECT  25.92 32.237 25.938 45.725 ;
     RECT  34.776 45.697 35.097 45.797 ;
     RECT  39.672 44.753 216.63 45.841 ;
     RECT  7.815 43.061 8.55 45.959 ;
     RECT  7.815 45.959 8.19 46.499 ;
     RECT  4.86 39.515 4.878 46.741 ;
     RECT  5.652 45.329 6.93 46.741 ;
     RECT  4.86 46.741 7.002 46.769 ;
     RECT  5.328 46.769 7.002 47.039 ;
     RECT  6.696 47.039 7.002 47.075 ;
     RECT  9.288 44.753 9.306 47.083 ;
     RECT  5.328 47.039 5.67 47.111 ;
     RECT  217.764 45.691 218.697 47.147 ;
     RECT  39.168 45.841 216.63 47.308 ;
     RECT  9.144 47.083 9.306 47.615 ;
     RECT  39.168 47.308 216.666 47.615 ;
     RECT  217.8 47.147 218.697 47.687 ;
     RECT  2.415 39.245 2.697 47.695 ;
     RECT  1.728 47.695 2.697 47.731 ;
     RECT  6.984 47.075 7.002 47.821 ;
     RECT  7.815 46.499 8.097 47.821 ;
     RECT  5.328 47.111 5.346 47.929 ;
     RECT  6.984 47.821 8.097 47.929 ;
     RECT  9.144 47.615 9.162 47.929 ;
     RECT  1.728 47.731 2.97 47.965 ;
     RECT  6.84 47.929 9.162 47.965 ;
     RECT  0.108 47.857 0.126 48.043 ;
     RECT  1.728 47.965 3.546 48.127 ;
     RECT  218.304 47.687 218.697 48.155 ;
     RECT  10.584 35.771 10.602 48.269 ;
     RECT  1.728 48.127 4.518 48.361 ;
     RECT  5.328 47.929 5.778 48.361 ;
     RECT  39.168 47.615 216.63 48.361 ;
     RECT  1.728 48.361 5.778 48.365 ;
     RECT  0.108 48.043 0.162 48.397 ;
     RECT  0.108 48.397 0.558 48.461 ;
     RECT  2.415 48.365 5.778 48.505 ;
     RECT  6.804 47.965 9.162 48.505 ;
     RECT  39.168 48.361 217.206 48.509 ;
     RECT  2.415 48.505 9.162 48.541 ;
     RECT  10.8 48.469 10.818 48.569 ;
     RECT  24.015 37.463 24.297 48.631 ;
     RECT  25.668 48.361 25.686 48.739 ;
     RECT  24.015 48.631 24.714 48.811 ;
     RECT  39.168 48.509 216.63 48.811 ;
     RECT  218.415 48.155 218.697 48.901 ;
     RECT  38.772 48.811 216.63 48.929 ;
     RECT  25.668 48.739 26.082 48.937 ;
     RECT  22.824 48.739 22.842 48.965 ;
     RECT  25.668 48.937 26.586 48.965 ;
     RECT  38.844 48.929 216.63 48.965 ;
     RECT  2.415 48.541 9.45 48.973 ;
     RECT  218.415 48.901 218.826 48.989 ;
     RECT  24.015 48.811 24.93 49.009 ;
     RECT  2.415 48.973 9.882 49.109 ;
     RECT  218.415 48.989 218.697 49.147 ;
     RECT  29.415 38.039 29.697 49.171 ;
     RECT  14.868 48.703 14.886 49.235 ;
     RECT  23.328 49.009 24.93 49.243 ;
     RECT  29.376 49.171 29.697 49.307 ;
     RECT  10.908 48.631 10.926 49.315 ;
     RECT  26.064 48.965 26.586 49.315 ;
     RECT  26.064 49.315 26.802 49.351 ;
     RECT  21.096 48.091 21.114 49.379 ;
     RECT  10.908 49.315 10.962 49.441 ;
     RECT  14.796 49.315 14.814 49.469 ;
     RECT  0.108 48.461 0.234 49.483 ;
     RECT  2.415 49.109 9.414 49.565 ;
     RECT  39.348 48.965 216.63 49.565 ;
     RECT  10.764 49.441 10.962 49.577 ;
     RECT  34.815 45.797 35.097 49.621 ;
     RECT  23.328 49.243 25.11 49.711 ;
     RECT  22.86 49.711 25.11 49.775 ;
     RECT  26.064 49.351 26.874 49.775 ;
     RECT  26.424 49.775 26.874 49.855 ;
     RECT  22.86 49.775 25.074 49.891 ;
     RECT  34.2 49.621 35.097 49.901 ;
     RECT  0.108 49.483 0.558 49.997 ;
     RECT  22.824 49.891 25.074 50.017 ;
     RECT  41.616 49.565 216.63 50.045 ;
     RECT  22.248 50.017 25.074 50.081 ;
     RECT  26.424 49.855 27.45 50.117 ;
     RECT  39.348 49.565 40.878 50.141 ;
     RECT  22.248 50.081 24.966 50.153 ;
     RECT  35.928 50.053 35.946 50.189 ;
     RECT  2.415 49.565 5.958 50.287 ;
     RECT  22.248 50.153 23.058 50.387 ;
     RECT  39.924 50.141 40.878 50.387 ;
     RECT  40.215 50.387 40.878 50.395 ;
     RECT  10.764 49.577 10.926 50.459 ;
     RECT  26.424 50.117 26.946 50.459 ;
     RECT  0.108 49.997 0.342 50.477 ;
     RECT  2.376 50.287 5.958 50.521 ;
     RECT  6.768 49.565 9.414 50.521 ;
     RECT  34.776 49.901 35.097 50.549 ;
     RECT  34.815 50.549 35.097 50.557 ;
     RECT  2.376 50.521 9.414 50.585 ;
     RECT  26.424 50.459 26.838 50.585 ;
     RECT  9.144 50.585 9.414 50.629 ;
     RECT  218.304 49.147 218.697 50.683 ;
     RECT  26.568 50.585 26.838 50.729 ;
     RECT  34.815 50.557 35.442 50.819 ;
     RECT  9.144 50.629 9.702 50.863 ;
     RECT  2.376 50.585 8.37 50.864 ;
     RECT  10.8 50.459 10.926 50.891 ;
     RECT  34.815 50.819 35.37 50.909 ;
     RECT  37.044 50.089 37.062 50.927 ;
     RECT  22.824 50.387 23.058 50.971 ;
     RECT  23.94 50.153 24.297 50.971 ;
     RECT  26.568 50.729 26.766 50.999 ;
     RECT  217.764 50.683 218.697 50.999 ;
     RECT  2.376 50.864 3.186 51.019 ;
     RECT  10.908 50.891 10.926 51.061 ;
     RECT  40.215 50.395 41.058 51.067 ;
     RECT  42.156 50.045 216.63 51.067 ;
     RECT  9.144 50.863 9.882 51.089 ;
     RECT  26.64 50.999 26.766 51.089 ;
     RECT  38.772 50.935 38.862 51.089 ;
     RECT  22.824 50.971 24.297 51.169 ;
     RECT  40.215 51.067 216.63 51.197 ;
     RECT  21.672 51.169 21.69 51.205 ;
     RECT  9.144 51.089 9.306 51.233 ;
     RECT  10.908 51.061 10.998 51.269 ;
     RECT  0.108 50.477 0.162 51.307 ;
     RECT  21.096 51.205 21.69 51.359 ;
     RECT  38.844 51.089 38.862 51.403 ;
     RECT  0.108 51.307 0.342 51.437 ;
     RECT  22.824 51.169 24.534 51.439 ;
     RECT  21.672 51.359 21.69 51.467 ;
     RECT  38.844 51.403 39.366 51.475 ;
     RECT  40.215 51.197 42.246 51.475 ;
     RECT  3.924 50.864 8.37 51.511 ;
     RECT  9.144 51.233 9.162 51.511 ;
     RECT  22.824 51.439 24.642 51.539 ;
     RECT  22.824 51.539 24.534 51.637 ;
     RECT  13.215 43.799 13.497 51.673 ;
     RECT  3.924 51.511 9.162 51.737 ;
     RECT  218.232 50.999 218.697 51.739 ;
     RECT  38.844 51.475 42.246 51.871 ;
     RECT  25.452 51.781 25.47 51.907 ;
     RECT  26.748 51.089 26.766 51.907 ;
     RECT  34.815 50.909 35.097 51.907 ;
     RECT  43.2 51.197 216.63 51.931 ;
     RECT  20.52 51.709 20.538 51.935 ;
     RECT  12.564 51.673 13.497 52.079 ;
     RECT  2.304 51.019 3.186 52.123 ;
     RECT  3.924 51.737 8.262 52.123 ;
     RECT  25.308 51.907 25.47 52.141 ;
     RECT  38.808 51.871 42.246 52.141 ;
     RECT  0.108 51.437 0.126 52.168 ;
     RECT  38.808 52.141 42.282 52.169 ;
     RECT  39.6 52.169 42.282 52.177 ;
     RECT  43.092 51.931 216.63 52.177 ;
     RECT  39.6 52.177 216.63 52.219 ;
     RECT  217.764 51.739 218.697 52.219 ;
     RECT  25.308 52.141 25.686 52.241 ;
     RECT  26.748 51.907 26.874 52.241 ;
     RECT  38.808 52.169 38.826 52.241 ;
     RECT  26.748 52.241 26.766 52.249 ;
     RECT  26.676 52.249 26.766 52.277 ;
     RECT  34.776 51.907 35.097 52.277 ;
     RECT  25.668 52.241 25.686 52.285 ;
     RECT  39.6 52.219 218.697 52.313 ;
     RECT  22.248 51.637 24.534 52.321 ;
     RECT  39.6 52.313 216.63 52.349 ;
     RECT  2.304 52.123 8.262 52.363 ;
     RECT  26.676 52.277 26.694 52.439 ;
     RECT  10.836 51.979 10.854 52.483 ;
     RECT  2.268 52.363 8.262 52.547 ;
     RECT  22.248 52.321 24.714 52.547 ;
     RECT  0.108 52.168 0.162 52.555 ;
     RECT  10.728 52.483 10.854 52.555 ;
     RECT  2.304 52.547 8.262 52.717 ;
     RECT  9 51.737 9.162 52.717 ;
     RECT  0.108 52.555 0.558 52.745 ;
     RECT  25.668 52.285 25.902 52.753 ;
     RECT  14.256 52.411 14.274 52.781 ;
     RECT  22.248 52.547 24.534 52.789 ;
     RECT  21.672 52.789 24.534 52.853 ;
     RECT  217.764 52.313 218.697 52.853 ;
     RECT  21.672 52.853 21.69 52.861 ;
     RECT  2.304 52.717 9.162 52.889 ;
     RECT  10.728 52.555 10.926 52.979 ;
     RECT  39.6 52.349 42.318 52.979 ;
     RECT  22.716 52.853 24.534 53.015 ;
     RECT  25.668 52.753 26.55 53.015 ;
     RECT  25.668 53.015 25.686 53.021 ;
     RECT  218.196 52.853 218.697 53.021 ;
     RECT  18.615 38.399 18.897 53.059 ;
     RECT  3.42 52.889 9.162 53.221 ;
     RECT  18.615 53.059 18.954 53.249 ;
     RECT  22.716 53.015 22.878 53.249 ;
     RECT  43.2 52.349 216.63 53.275 ;
     RECT  2.304 52.889 2.697 53.285 ;
     RECT  21.096 52.861 21.69 53.285 ;
     RECT  3.42 53.221 9.306 53.329 ;
     RECT  10.728 52.979 10.818 53.329 ;
     RECT  19.98 52.825 19.998 53.329 ;
     RECT  0.324 52.745 0.558 53.357 ;
     RECT  21.672 53.285 21.69 53.357 ;
     RECT  10.656 53.329 10.818 53.429 ;
     RECT  22.716 53.249 22.806 53.429 ;
     RECT  22.788 53.429 22.806 53.519 ;
     RECT  38.772 53.329 38.79 53.527 ;
     RECT  10.692 53.429 10.818 53.555 ;
     RECT  3.42 53.329 9.378 53.563 ;
     RECT  23.796 53.015 24.534 53.563 ;
     RECT  3.42 53.563 9.45 53.663 ;
     RECT  38.196 53.527 38.79 53.663 ;
     RECT  34.815 52.277 35.097 53.671 ;
     RECT  0.324 53.357 0.342 53.707 ;
     RECT  23.796 53.563 24.57 53.761 ;
     RECT  3.42 53.663 9.306 53.789 ;
     RECT  39.852 52.979 42.318 53.789 ;
     RECT  38.772 53.663 38.79 53.797 ;
     RECT  39.852 53.789 42.21 53.837 ;
     RECT  23.688 53.761 24.57 53.861 ;
     RECT  38.772 53.797 38.862 53.897 ;
     RECT  2.415 53.285 2.697 53.905 ;
     RECT  3.42 53.789 8.406 53.905 ;
     RECT  25.956 53.833 25.974 53.941 ;
     RECT  10.908 53.869 10.926 53.969 ;
     RECT  18.615 53.249 18.918 54.031 ;
     RECT  19.944 53.329 19.998 54.031 ;
     RECT  25.236 53.941 25.974 54.031 ;
     RECT  26.856 53.293 26.874 54.031 ;
     RECT  43.2 53.275 217.17 54.043 ;
     RECT  218.304 53.021 218.697 54.043 ;
     RECT  25.236 54.031 26.874 54.059 ;
     RECT  34.776 53.671 35.097 54.059 ;
     RECT  25.956 54.059 26.874 54.095 ;
     RECT  23.688 53.861 24.297 54.131 ;
     RECT  35.928 54.103 35.946 54.221 ;
     RECT  15.984 53.869 16.002 54.239 ;
     RECT  9.144 53.789 9.306 54.329 ;
     RECT  22.896 54.139 22.914 54.337 ;
     RECT  23.832 54.131 24.297 54.365 ;
     RECT  0.108 53.707 0.342 54.379 ;
     RECT  2.415 53.905 8.406 54.437 ;
     RECT  10.692 54.337 10.782 54.437 ;
     RECT  22.248 54.337 22.914 54.437 ;
     RECT  18.615 54.031 19.998 54.445 ;
     RECT  18.615 54.445 20.034 54.509 ;
     RECT  25.992 54.095 26.73 54.599 ;
     RECT  18.615 54.509 18.954 54.635 ;
     RECT  19.98 54.509 20.034 54.635 ;
     RECT  26.208 54.599 26.73 54.671 ;
     RECT  20.016 54.635 20.034 54.743 ;
     RECT  24.012 54.365 24.297 54.841 ;
     RECT  43.2 54.043 218.697 54.845 ;
     RECT  217.764 54.845 218.697 54.941 ;
     RECT  26.712 54.671 26.73 54.949 ;
     RECT  26.712 54.949 26.874 54.977 ;
     RECT  2.415 54.437 8.262 55.021 ;
     RECT  26.856 54.977 26.874 55.049 ;
     RECT  217.8 54.941 218.697 55.049 ;
     RECT  43.2 54.845 216.63 55.099 ;
     RECT  22.248 54.437 22.878 55.175 ;
     RECT  22.824 55.175 22.878 55.183 ;
     RECT  24.012 54.841 24.426 55.183 ;
     RECT  38.772 53.897 38.826 55.183 ;
     RECT  22.824 55.183 24.426 55.291 ;
     RECT  38.196 55.183 38.826 55.319 ;
     RECT  39.924 53.837 42.21 55.325 ;
     RECT  2.376 55.021 8.262 55.381 ;
     RECT  9.144 54.329 9.162 55.381 ;
     RECT  10.764 54.437 10.782 55.381 ;
     RECT  22.824 55.291 24.894 55.381 ;
     RECT  18.615 54.635 18.897 55.453 ;
     RECT  10.764 55.381 10.854 55.481 ;
     RECT  22.824 55.381 24.966 55.481 ;
     RECT  33.624 55.147 33.642 55.481 ;
     RECT  18.615 55.453 18.918 55.589 ;
     RECT  10.764 55.481 10.818 55.687 ;
     RECT  35.928 55.525 35.946 55.709 ;
     RECT  39.924 55.325 40.806 55.715 ;
     RECT  41.616 55.325 42.21 55.759 ;
     RECT  43.092 55.099 216.63 55.759 ;
     RECT  0.108 54.379 0.558 55.787 ;
     RECT  22.824 55.481 24.894 55.787 ;
     RECT  2.376 55.381 9.162 55.819 ;
     RECT  38.772 55.319 38.826 55.831 ;
     RECT  2.34 55.819 9.162 55.949 ;
     RECT  22.824 55.787 24.606 55.985 ;
     RECT  41.616 55.759 216.63 55.997 ;
     RECT  21.096 55.723 21.114 56.093 ;
     RECT  42.768 55.997 216.63 56.093 ;
     RECT  23.688 55.985 24.606 56.129 ;
     RECT  43.092 56.093 216.63 56.129 ;
     RECT  10.728 55.687 10.818 56.227 ;
     RECT  23.724 56.129 24.606 56.255 ;
     RECT  22.716 56.263 22.734 56.299 ;
     RECT  10.692 56.227 10.818 56.327 ;
     RECT  218.268 55.049 218.697 56.347 ;
     RECT  23.724 56.255 24.57 56.363 ;
     RECT  39.924 55.715 40.626 56.399 ;
     RECT  2.376 55.949 9.162 56.461 ;
     RECT  18.615 55.589 18.897 56.461 ;
     RECT  22.248 56.299 22.734 56.525 ;
     RECT  26.748 56.461 26.766 56.561 ;
     RECT  39.96 56.399 40.626 56.569 ;
     RECT  41.616 55.997 41.706 56.569 ;
     RECT  38.772 55.831 39.186 56.573 ;
     RECT  18.615 56.461 18.954 56.597 ;
     RECT  10.8 56.327 10.818 56.669 ;
     RECT  0.108 55.787 0.342 56.683 ;
     RECT  38.772 56.573 38.898 56.759 ;
     RECT  36.504 56.227 36.522 56.779 ;
     RECT  19.944 56.641 19.962 56.803 ;
     RECT  35.928 56.779 36.522 56.831 ;
     RECT  36.504 56.831 36.522 56.861 ;
     RECT  39.96 56.569 41.706 56.911 ;
     RECT  10.908 56.767 10.998 56.939 ;
     RECT  38.772 56.759 38.862 56.939 ;
     RECT  39.96 56.911 42.21 56.956 ;
     RECT  43.2 56.129 216.63 56.956 ;
     RECT  2.376 56.461 9.234 56.971 ;
     RECT  19.944 56.803 20.538 57.001 ;
     RECT  19.944 57.001 21.114 57.065 ;
     RECT  217.764 56.347 218.697 57.101 ;
     RECT  19.944 57.065 19.962 57.173 ;
     RECT  23.724 56.363 24.297 57.181 ;
     RECT  39.96 56.956 216.63 57.181 ;
     RECT  39.924 57.181 216.63 57.245 ;
     RECT  23.4 57.181 24.678 57.271 ;
     RECT  2.304 56.971 9.234 57.379 ;
     RECT  18.615 56.597 18.897 57.415 ;
     RECT  23.4 57.271 24.786 57.443 ;
     RECT  0.108 56.683 0.558 57.488 ;
     RECT  29.415 49.307 29.697 57.541 ;
     RECT  2.304 57.379 9.378 57.569 ;
     RECT  23.4 57.443 24.39 57.605 ;
     RECT  22.248 56.525 22.662 57.613 ;
     RECT  21.096 57.065 21.114 57.641 ;
     RECT  2.304 57.569 9.162 57.713 ;
     RECT  38.808 56.939 38.862 57.721 ;
     RECT  39.924 57.245 41.202 57.721 ;
     RECT  29.415 57.541 29.754 57.749 ;
     RECT  38.808 57.721 41.202 57.839 ;
     RECT  22.248 57.613 22.986 57.875 ;
     RECT  42.192 57.245 216.63 57.875 ;
     RECT  10.8 57.649 10.818 57.883 ;
     RECT  18.615 57.415 18.954 57.983 ;
     RECT  34.815 54.059 35.097 57.991 ;
     RECT  39.708 57.839 41.202 57.991 ;
     RECT  42.192 57.875 216.024 57.991 ;
     RECT  218.304 57.101 218.697 58.075 ;
     RECT  10.8 57.883 10.854 58.109 ;
     RECT  20.52 57.847 20.538 58.253 ;
     RECT  34.815 57.991 35.37 58.253 ;
     RECT  23.94 57.605 24.39 58.261 ;
     RECT  0.108 57.488 0.162 58.315 ;
     RECT  218.232 58.075 218.697 58.415 ;
     RECT  18.615 57.983 18.897 58.423 ;
     RECT  0.108 58.315 0.558 58.487 ;
     RECT  22.824 57.875 22.986 58.495 ;
     RECT  23.94 58.261 24.534 58.495 ;
     RECT  26.748 58.531 26.766 58.621 ;
     RECT  38.808 57.839 38.826 58.621 ;
     RECT  2.415 57.713 9.162 58.649 ;
     RECT  9.036 58.649 9.162 58.685 ;
     RECT  38.772 58.621 38.826 58.721 ;
     RECT  9.144 58.685 9.162 58.729 ;
     RECT  26.676 58.621 26.766 58.729 ;
     RECT  39.708 57.991 216.024 58.729 ;
     RECT  39.564 58.729 216.024 58.747 ;
     RECT  217.188 58.081 217.206 58.747 ;
     RECT  9.144 58.729 9.63 58.757 ;
     RECT  26.568 58.729 26.766 58.765 ;
     RECT  39.564 58.747 217.206 58.765 ;
     RECT  18.252 58.423 18.897 58.793 ;
     RECT  26.028 58.765 26.766 58.795 ;
     RECT  2.415 58.649 8.154 58.829 ;
     RECT  25.956 58.795 26.766 58.835 ;
     RECT  10.764 58.189 10.782 58.891 ;
     RECT  9.288 58.757 9.63 58.919 ;
     RECT  22.824 58.495 24.534 58.919 ;
     RECT  26.028 58.835 26.766 58.919 ;
     RECT  39.276 58.765 217.206 58.919 ;
     RECT  22.896 58.919 24.534 58.963 ;
     RECT  39.564 58.919 217.206 58.973 ;
     RECT  22.896 58.963 24.678 58.987 ;
     RECT  22.896 58.987 24.822 58.991 ;
     RECT  34.815 58.253 35.097 58.999 ;
     RECT  2.415 58.829 8.097 59.021 ;
     RECT  3.888 59.021 8.097 59.027 ;
     RECT  9.612 58.919 9.63 59.027 ;
     RECT  37.692 58.693 37.71 59.027 ;
     RECT  39.564 58.973 216.63 59.027 ;
     RECT  29.415 57.749 29.697 59.035 ;
     RECT  2.415 59.021 3.15 59.179 ;
     RECT  34.776 58.999 35.097 59.189 ;
     RECT  39.636 59.027 216.63 59.189 ;
     RECT  17.676 58.963 17.694 59.197 ;
     RECT  3.924 59.027 8.097 59.261 ;
     RECT  22.968 58.991 24.822 59.261 ;
     RECT  23.328 59.261 24.822 59.269 ;
     RECT  3.924 59.261 5.598 59.309 ;
     RECT  2.304 59.179 3.15 59.341 ;
     RECT  26.352 58.919 26.766 59.341 ;
     RECT  17.1 59.197 17.694 59.369 ;
     RECT  2.268 59.341 3.15 59.405 ;
     RECT  23.328 59.269 25.11 59.459 ;
     RECT  0.108 58.487 0.342 59.467 ;
     RECT  26.352 59.341 26.802 59.467 ;
     RECT  4.392 59.309 5.598 59.495 ;
     RECT  23.832 59.459 25.11 59.495 ;
     RECT  218.304 58.415 218.697 59.515 ;
     RECT  0.108 59.467 0.558 59.567 ;
     RECT  29.415 59.035 30.222 59.597 ;
     RECT  39.924 59.189 216.63 59.837 ;
     RECT  26.352 59.467 26.874 59.845 ;
     RECT  17.1 59.369 17.118 59.873 ;
     RECT  2.304 59.405 3.15 59.881 ;
     RECT  26.316 59.845 26.874 59.971 ;
     RECT  217.764 59.515 218.697 59.971 ;
     RECT  9.18 59.881 9.198 59.999 ;
     RECT  4.572 59.495 5.598 60.007 ;
     RECT  6.336 59.261 8.097 60.007 ;
     RECT  10.764 58.891 10.818 60.007 ;
     RECT  21.672 59.467 21.69 60.007 ;
     RECT  217.764 59.971 218.718 60.029 ;
     RECT  21.096 60.007 21.69 60.035 ;
     RECT  23.94 59.495 25.11 60.035 ;
     RECT  10.728 60.007 10.818 60.043 ;
     RECT  0.108 59.567 0.342 60.077 ;
     RECT  4.572 60.007 8.097 60.115 ;
     RECT  25.92 59.971 26.874 60.143 ;
     RECT  10.728 60.043 10.926 60.179 ;
     RECT  26.172 60.143 26.874 60.179 ;
     RECT  2.304 59.881 3.438 60.269 ;
     RECT  26.172 60.179 26.19 60.269 ;
     RECT  0.108 60.077 0.162 60.305 ;
     RECT  3.708 60.277 3.726 60.317 ;
     RECT  0.144 60.305 0.162 60.341 ;
     RECT  4.572 60.115 8.262 60.379 ;
     RECT  4.572 60.379 8.442 60.421 ;
     RECT  23.94 60.035 24.858 60.421 ;
     RECT  39.924 59.837 216.024 60.421 ;
     RECT  21.096 60.035 21.186 60.449 ;
     RECT  3.96 60.421 8.442 60.539 ;
     RECT  39.78 60.421 216.024 60.547 ;
     RECT  2.304 60.269 2.754 60.575 ;
     RECT  4.572 60.539 6.318 60.575 ;
     RECT  7.38 60.539 8.262 60.575 ;
     RECT  21.132 60.449 21.186 60.575 ;
     RECT  23.652 60.421 24.858 60.575 ;
     RECT  39.708 60.547 216.024 60.583 ;
     RECT  9.324 60.421 9.342 60.611 ;
     RECT  21.168 60.575 21.186 60.647 ;
     RECT  22.896 60.655 22.914 60.817 ;
     RECT  24.015 60.575 24.858 60.817 ;
     RECT  4.608 60.575 6.318 60.845 ;
     RECT  22.824 60.817 22.914 60.845 ;
     RECT  5.688 60.845 6.318 60.953 ;
     RECT  7.38 60.575 8.097 60.953 ;
     RECT  22.824 60.845 22.842 60.953 ;
     RECT  24.015 60.817 24.93 60.953 ;
     RECT  4.608 60.845 4.626 60.989 ;
     RECT  6.3 60.953 6.318 60.989 ;
     RECT  39.6 60.583 216.024 61.181 ;
     RECT  40.215 61.181 216.024 61.339 ;
     RECT  40.215 61.339 216.63 61.385 ;
     RECT  38.772 60.079 38.79 61.469 ;
     RECT  42.804 61.385 216.126 61.565 ;
     RECT  40.215 61.385 41.886 61.619 ;
     RECT  40.215 61.619 40.95 61.655 ;
     RECT  41.868 61.619 41.886 61.661 ;
     RECT  42.84 61.565 216.126 61.757 ;
     RECT  217.764 60.029 218.697 61.763 ;
     RECT  217.8 61.763 218.697 61.997 ;
     RECT  43.2 61.757 216.126 62.159 ;
     RECT  217.836 61.997 218.697 62.465 ;
     RECT  43.2 62.159 216.024 62.664 ;
     RECT  45.615 64.783 45.705 65.053 ;
     RECT  51.015 64.783 51.105 65.053 ;
     RECT  56.415 64.783 56.505 65.053 ;
     RECT  61.815 64.783 61.905 65.053 ;
     RECT  67.215 64.783 67.305 65.053 ;
     RECT  72.615 64.783 72.705 65.053 ;
     RECT  78.015 64.783 78.105 65.053 ;
     RECT  83.415 64.783 83.505 65.053 ;
     RECT  88.815 64.783 88.905 65.053 ;
     RECT  94.215 64.783 94.305 65.053 ;
     RECT  99.615 64.783 99.705 65.053 ;
     RECT  105.015 64.783 105.105 65.053 ;
     RECT  110.415 64.783 110.505 65.053 ;
     RECT  115.815 64.783 115.905 65.053 ;
     RECT  121.215 64.783 121.305 65.053 ;
     RECT  126.615 64.783 126.705 65.053 ;
     RECT  132.015 64.783 132.105 65.053 ;
     RECT  137.415 64.783 137.505 65.053 ;
     RECT  142.815 64.783 142.905 65.053 ;
     RECT  148.215 64.783 148.305 65.053 ;
     RECT  153.615 64.783 153.705 65.053 ;
     RECT  159.015 64.783 159.105 65.053 ;
     RECT  164.415 64.783 164.505 65.053 ;
     RECT  169.815 64.783 169.905 65.053 ;
     RECT  175.215 64.783 175.305 65.053 ;
     RECT  180.615 64.783 180.705 65.053 ;
     RECT  186.015 64.783 186.105 65.053 ;
     RECT  191.415 64.783 191.505 65.053 ;
     RECT  196.815 64.783 196.905 65.053 ;
     RECT  202.215 64.783 202.305 65.053 ;
     RECT  207.615 64.783 207.705 65.053 ;
     RECT  213.015 64.783 213.105 65.053 ;
     RECT  2.415 60.575 2.697 83.987 ;
     RECT  7.815 60.953 8.097 83.987 ;
     RECT  13.215 52.079 13.497 83.987 ;
     RECT  18.615 58.793 18.897 83.987 ;
     RECT  24.015 60.953 24.297 83.987 ;
     RECT  29.415 59.597 29.697 83.987 ;
     RECT  34.815 59.189 35.097 83.987 ;
     RECT  40.215 61.655 40.497 83.987 ;
     RECT  45.615 65.053 45.897 83.987 ;
     RECT  51.015 65.053 51.297 83.987 ;
     RECT  56.415 65.053 56.697 83.987 ;
     RECT  61.815 65.053 62.097 83.987 ;
     RECT  67.215 65.053 67.497 83.987 ;
     RECT  72.615 65.053 72.897 83.987 ;
     RECT  78.015 65.053 78.297 83.987 ;
     RECT  83.415 65.053 83.697 83.987 ;
     RECT  88.815 65.053 89.097 83.987 ;
     RECT  94.215 65.053 94.497 83.987 ;
     RECT  99.615 65.053 99.897 83.987 ;
     RECT  105.015 65.053 105.297 83.987 ;
     RECT  110.415 65.053 110.697 83.987 ;
     RECT  115.815 65.053 116.097 83.987 ;
     RECT  121.215 65.053 121.497 83.987 ;
     RECT  126.615 65.053 126.897 83.987 ;
     RECT  132.015 65.053 132.297 83.987 ;
     RECT  137.415 65.053 137.697 83.987 ;
     RECT  142.815 65.053 143.097 83.987 ;
     RECT  148.215 65.053 148.497 83.987 ;
     RECT  153.615 65.053 153.897 83.987 ;
     RECT  159.015 65.053 159.297 83.987 ;
     RECT  164.415 65.053 164.697 83.987 ;
     RECT  169.815 65.053 170.097 83.987 ;
     RECT  175.215 65.053 175.497 83.987 ;
     RECT  180.615 65.053 180.897 83.987 ;
     RECT  186.015 65.053 186.297 83.987 ;
     RECT  191.415 65.053 191.697 83.987 ;
     RECT  196.815 65.053 197.097 83.987 ;
     RECT  202.215 65.053 202.497 83.987 ;
     RECT  207.615 65.053 207.897 83.987 ;
     RECT  213.015 65.053 213.297 83.987 ;
     RECT  218.415 62.465 218.697 83.987 ;
     RECT  223.815 2.413 224.097 83.987 ;
     RECT  229.215 2.413 229.497 83.987 ;
     RECT  234.615 2.413 234.897 83.987 ;
     RECT  2.415 83.987 2.505 84.257 ;
     RECT  7.815 83.987 7.905 84.257 ;
     RECT  13.215 83.987 13.305 84.257 ;
     RECT  18.615 83.987 18.705 84.257 ;
     RECT  24.015 83.987 24.105 84.257 ;
     RECT  29.415 83.987 29.505 84.257 ;
     RECT  34.815 83.987 34.905 84.257 ;
     RECT  40.215 83.987 40.305 84.257 ;
     RECT  45.615 83.987 45.705 84.257 ;
     RECT  51.015 83.987 51.105 84.257 ;
     RECT  56.415 83.987 56.505 84.257 ;
     RECT  61.815 83.987 61.905 84.257 ;
     RECT  67.215 83.987 67.305 84.257 ;
     RECT  72.615 83.987 72.705 84.257 ;
     RECT  78.015 83.987 78.105 84.257 ;
     RECT  83.415 83.987 83.505 84.257 ;
     RECT  88.815 83.987 88.905 84.257 ;
     RECT  94.215 83.987 94.305 84.257 ;
     RECT  99.615 83.987 99.705 84.257 ;
     RECT  105.015 83.987 105.105 84.257 ;
     RECT  110.415 83.987 110.505 84.257 ;
     RECT  115.815 83.987 115.905 84.257 ;
     RECT  121.215 83.987 121.305 84.257 ;
     RECT  126.615 83.987 126.705 84.257 ;
     RECT  132.015 83.987 132.105 84.257 ;
     RECT  137.415 83.987 137.505 84.257 ;
     RECT  142.815 83.987 142.905 84.257 ;
     RECT  148.215 83.987 148.305 84.257 ;
     RECT  153.615 83.987 153.705 84.257 ;
     RECT  159.015 83.987 159.105 84.257 ;
     RECT  164.415 83.987 164.505 84.257 ;
     RECT  169.815 83.987 169.905 84.257 ;
     RECT  175.215 83.987 175.305 84.257 ;
     RECT  180.615 83.987 180.705 84.257 ;
     RECT  186.015 83.987 186.105 84.257 ;
     RECT  191.415 83.987 191.505 84.257 ;
     RECT  196.815 83.987 196.905 84.257 ;
     RECT  202.215 83.987 202.305 84.257 ;
     RECT  207.615 83.987 207.705 84.257 ;
     RECT  213.015 83.987 213.105 84.257 ;
     RECT  218.415 83.987 218.505 84.257 ;
     RECT  223.815 83.987 223.905 84.257 ;
     RECT  229.215 83.987 229.305 84.257 ;
     RECT  234.615 83.987 234.705 84.257 ;
    LAYER M4 ;
     RECT  0.084 36.432 0.097 36.456 ;
     RECT  0.06 36.456 0.097 36.528 ;
     RECT  0.084 36.528 0.097 36.552 ;
     RECT  0.06 36.552 0.097 36.624 ;
     RECT  0.084 36.624 0.097 36.648 ;
     RECT  0.06 36.648 0.097 36.72 ;
     RECT  0.084 36.72 0.097 36.744 ;
     RECT  0.06 36.744 0.097 36.816 ;
     RECT  0.084 36.816 0.097 36.84 ;
     RECT  0.06 36.84 0.097 36.912 ;
     RECT  0.084 36.912 0.097 36.936 ;
     RECT  0.06 36.936 0.097 37.008 ;
     RECT  0.084 37.008 0.097 37.032 ;
     RECT  0.06 37.032 0.097 37.104 ;
     RECT  0.084 37.104 0.097 37.128 ;
     RECT  0.06 37.128 0.097 37.2 ;
     RECT  0.084 37.2 0.097 37.224 ;
     RECT  0.06 37.224 0.097 37.296 ;
     RECT  0.084 37.296 0.097 37.32 ;
     RECT  0.06 37.32 0.097 37.392 ;
     RECT  0.084 37.392 0.097 37.416 ;
     RECT  0.06 37.416 0.097 37.488 ;
     RECT  0.084 37.488 0.097 37.512 ;
     RECT  0.06 37.512 0.097 37.584 ;
     RECT  0.084 37.584 0.097 37.608 ;
     RECT  0.06 37.608 0.097 37.68 ;
     RECT  0.084 37.68 0.097 37.704 ;
     RECT  0.06 37.704 0.097 37.776 ;
     RECT  0.084 37.776 0.097 37.8 ;
     RECT  0.06 37.8 0.097 37.872 ;
     RECT  0.084 37.872 0.097 37.896 ;
     RECT  0.06 37.896 0.097 37.968 ;
     RECT  0.084 37.968 0.097 37.992 ;
     RECT  0.084 15.792 0.137 15.816 ;
     RECT  0.06 15.816 0.137 15.888 ;
     RECT  0.084 15.888 0.137 15.912 ;
     RECT  0.06 15.912 0.137 15.984 ;
     RECT  0.084 15.984 0.137 16.008 ;
     RECT  0.06 16.008 0.137 16.08 ;
     RECT  0.084 16.08 0.137 16.104 ;
     RECT  0.06 16.104 0.137 16.176 ;
     RECT  0.084 16.176 0.137 16.2 ;
     RECT  0.06 16.2 0.137 16.272 ;
     RECT  0.084 16.272 0.137 16.296 ;
     RECT  0.06 16.296 0.137 16.368 ;
     RECT  0.084 16.368 0.137 16.392 ;
     RECT  0.06 16.392 0.137 16.464 ;
     RECT  0.084 16.464 0.137 16.488 ;
     RECT  0.06 16.488 0.137 16.56 ;
     RECT  0.084 16.56 0.137 16.584 ;
     RECT  0.06 16.584 0.137 16.656 ;
     RECT  0.084 16.656 0.137 16.68 ;
     RECT  0.06 16.68 0.137 16.752 ;
     RECT  0.084 16.752 0.137 16.776 ;
     RECT  0.06 16.776 0.137 16.848 ;
     RECT  0.084 16.848 0.137 16.872 ;
     RECT  0.06 16.872 0.137 16.944 ;
     RECT  0.084 16.944 0.137 16.968 ;
     RECT  0.06 16.968 0.137 17.04 ;
     RECT  0.084 17.04 0.137 17.064 ;
     RECT  0.06 17.064 0.137 17.136 ;
     RECT  0.084 17.136 0.137 17.16 ;
     RECT  0.06 17.16 0.137 17.232 ;
     RECT  0.084 17.232 0.137 17.256 ;
     RECT  0.06 17.256 0.137 17.328 ;
     RECT  0.084 17.328 0.137 17.352 ;
     RECT  0.06 17.352 0.137 17.424 ;
     RECT  0.084 17.424 0.137 17.448 ;
     RECT  0.06 17.448 0.137 17.52 ;
     RECT  0.084 17.52 0.137 17.544 ;
     RECT  0.06 17.544 0.137 17.616 ;
     RECT  0.084 17.616 0.137 17.64 ;
     RECT  0.06 17.64 0.137 17.712 ;
     RECT  0.084 17.712 0.137 17.736 ;
     RECT  0.06 17.736 0.137 17.808 ;
     RECT  0.084 17.808 0.137 17.832 ;
     RECT  0.06 17.832 0.137 17.904 ;
     RECT  0.084 17.904 0.137 17.928 ;
     RECT  0.06 17.928 0.137 18 ;
     RECT  0.084 18 0.137 18.024 ;
     RECT  0.06 18.024 0.137 18.096 ;
     RECT  0.084 18.096 0.137 18.12 ;
     RECT  0.06 18.12 0.137 18.192 ;
     RECT  0.084 18.192 0.137 18.216 ;
     RECT  0.06 18.216 0.137 18.288 ;
     RECT  0.084 18.288 0.137 18.312 ;
     RECT  0.06 18.312 0.137 18.384 ;
     RECT  0.084 18.384 0.137 18.408 ;
     RECT  0.06 18.408 0.137 18.48 ;
     RECT  0.084 18.48 0.137 18.504 ;
     RECT  0.06 18.504 0.137 18.576 ;
     RECT  0.084 18.576 0.137 18.6 ;
     RECT  0.06 18.6 0.137 18.672 ;
     RECT  0.084 18.672 0.137 18.696 ;
     RECT  0.06 18.696 0.137 18.768 ;
     RECT  0.084 18.768 0.137 18.792 ;
     RECT  0.06 18.792 0.137 18.864 ;
     RECT  0.084 18.864 0.137 18.888 ;
     RECT  0.06 18.888 0.137 18.96 ;
     RECT  0.084 18.96 0.137 18.984 ;
     RECT  0.06 18.984 0.137 19.056 ;
     RECT  0.084 19.056 0.137 19.08 ;
     RECT  0.06 19.08 0.137 19.152 ;
     RECT  0.084 19.152 0.137 19.176 ;
     RECT  0.06 19.176 0.137 19.248 ;
     RECT  0.084 19.248 0.137 19.272 ;
     RECT  0.06 19.272 0.137 19.344 ;
     RECT  0.084 19.344 0.137 19.368 ;
     RECT  0.06 19.368 0.137 19.44 ;
     RECT  0.084 19.44 0.137 19.464 ;
     RECT  0.06 19.464 0.137 19.536 ;
     RECT  0.084 19.536 0.137 19.56 ;
     RECT  0.06 19.56 0.137 19.632 ;
     RECT  0.084 19.632 0.137 19.656 ;
     RECT  0.06 19.656 0.137 19.728 ;
     RECT  0.084 19.728 0.137 19.752 ;
     RECT  0.06 19.752 0.137 19.824 ;
     RECT  0.084 19.824 0.137 19.848 ;
     RECT  0.06 19.848 0.137 19.92 ;
     RECT  0.084 19.92 0.137 19.944 ;
     RECT  0.06 19.944 0.137 20.016 ;
     RECT  0.084 20.016 0.137 20.04 ;
     RECT  0.06 20.04 0.137 20.112 ;
     RECT  0.084 20.112 0.137 20.136 ;
     RECT  0.06 20.136 0.137 20.208 ;
     RECT  0.084 20.208 0.137 20.232 ;
     RECT  0.06 20.232 0.137 20.304 ;
     RECT  0.084 20.304 0.137 20.328 ;
     RECT  0.06 20.328 0.137 20.4 ;
     RECT  0.084 20.4 0.137 20.424 ;
     RECT  0.06 20.424 0.137 20.496 ;
     RECT  0.084 20.496 0.137 20.52 ;
     RECT  0.06 20.52 0.137 20.592 ;
     RECT  0.084 20.592 0.137 20.616 ;
     RECT  0.06 20.616 0.137 20.688 ;
     RECT  0.084 20.688 0.137 20.712 ;
     RECT  0.06 20.712 0.137 20.784 ;
     RECT  0.084 20.784 0.137 20.808 ;
     RECT  0.06 20.808 0.137 20.88 ;
     RECT  0.084 20.88 0.137 20.904 ;
     RECT  0.06 20.904 0.137 20.976 ;
     RECT  0.084 20.976 0.137 21 ;
     RECT  0.06 21 0.137 21.072 ;
     RECT  0.084 21.072 0.137 21.096 ;
     RECT  0.06 21.096 0.137 21.168 ;
     RECT  0.084 21.168 0.137 21.192 ;
     RECT  0.06 21.192 0.137 21.264 ;
     RECT  0.084 21.264 0.137 21.288 ;
     RECT  0.06 21.288 0.137 21.36 ;
     RECT  0.084 21.36 0.137 21.384 ;
     RECT  0.06 21.384 0.137 21.456 ;
     RECT  0.084 21.456 0.137 21.48 ;
     RECT  0.06 21.48 0.137 21.552 ;
     RECT  0.084 21.552 0.137 21.576 ;
     RECT  0.06 21.576 0.137 21.648 ;
     RECT  0.084 21.648 0.137 21.672 ;
     RECT  0.06 21.672 0.137 21.744 ;
     RECT  0.084 21.744 0.137 21.768 ;
     RECT  0.06 21.768 0.137 21.84 ;
     RECT  0.084 21.84 0.137 21.864 ;
     RECT  0.06 21.864 0.137 21.936 ;
     RECT  0.084 21.936 0.137 21.96 ;
     RECT  0.06 21.96 0.137 22.032 ;
     RECT  0.084 22.032 0.137 22.056 ;
     RECT  0.06 22.056 0.137 22.128 ;
     RECT  0.084 22.128 0.137 22.152 ;
     RECT  0.06 22.152 0.137 22.224 ;
     RECT  0.084 22.224 0.137 22.248 ;
     RECT  0.06 22.248 0.137 22.32 ;
     RECT  0.084 22.32 0.137 22.344 ;
     RECT  0.06 22.344 0.137 22.416 ;
     RECT  0.084 22.416 0.137 22.44 ;
     RECT  0.06 22.44 0.137 22.512 ;
     RECT  0.084 22.512 0.137 22.536 ;
     RECT  0.06 22.536 0.137 22.608 ;
     RECT  0.084 22.608 0.137 22.632 ;
     RECT  0.06 22.632 0.137 22.704 ;
     RECT  0.084 22.704 0.137 22.728 ;
     RECT  0.06 22.728 0.137 22.8 ;
     RECT  0.084 22.8 0.137 22.824 ;
     RECT  0.06 22.824 0.137 22.896 ;
     RECT  0.084 22.896 0.137 22.92 ;
     RECT  0.06 22.92 0.137 22.992 ;
     RECT  0.084 22.992 0.137 23.016 ;
     RECT  0.06 23.016 0.137 23.088 ;
     RECT  0.084 23.088 0.137 23.112 ;
     RECT  0.06 23.112 0.137 23.184 ;
     RECT  0.084 23.184 0.137 23.208 ;
     RECT  0.06 23.208 0.137 23.28 ;
     RECT  0.084 23.28 0.137 23.304 ;
     RECT  0.06 23.304 0.137 23.376 ;
     RECT  0.084 23.376 0.137 23.4 ;
     RECT  0.06 23.4 0.137 23.472 ;
     RECT  0.084 23.472 0.137 23.496 ;
     RECT  0.06 23.496 0.137 23.568 ;
     RECT  0.084 23.568 0.137 23.592 ;
     RECT  0.06 23.592 0.137 23.664 ;
     RECT  0.084 23.664 0.137 23.688 ;
     RECT  0.06 23.688 0.137 23.76 ;
     RECT  0.084 23.76 0.137 23.784 ;
     RECT  0.06 23.784 0.137 23.856 ;
     RECT  0.084 23.856 0.137 23.88 ;
     RECT  0.06 23.88 0.137 23.952 ;
     RECT  0.084 23.952 0.137 23.976 ;
     RECT  0.06 23.976 0.137 24.048 ;
     RECT  0.084 24.048 0.137 24.072 ;
     RECT  0.06 24.072 0.137 24.144 ;
     RECT  0.084 24.144 0.137 24.168 ;
     RECT  0.06 24.168 0.137 24.24 ;
     RECT  0.084 24.24 0.137 24.264 ;
     RECT  0.06 24.264 0.137 24.336 ;
     RECT  0.084 24.336 0.137 24.36 ;
     RECT  0.06 24.36 0.137 24.432 ;
     RECT  0.084 24.432 0.137 24.456 ;
     RECT  0.06 24.456 0.137 24.528 ;
     RECT  0.084 24.528 0.137 24.552 ;
     RECT  0.06 24.552 0.137 24.624 ;
     RECT  0.084 24.624 0.137 24.648 ;
     RECT  0.06 24.648 0.137 24.72 ;
     RECT  0.084 24.72 0.137 24.744 ;
     RECT  0.06 24.744 0.137 24.816 ;
     RECT  0.084 24.816 0.137 24.84 ;
     RECT  0.06 24.84 0.137 24.912 ;
     RECT  0.084 24.912 0.137 24.936 ;
     RECT  0.06 24.936 0.137 25.008 ;
     RECT  0.084 25.008 0.137 25.032 ;
     RECT  0.06 25.032 0.137 25.104 ;
     RECT  0.084 25.104 0.137 25.128 ;
     RECT  0.06 25.128 0.137 25.2 ;
     RECT  0.084 25.2 0.137 25.224 ;
     RECT  0.06 25.224 0.137 25.296 ;
     RECT  0.084 25.296 0.137 25.32 ;
     RECT  0.06 25.32 0.137 25.392 ;
     RECT  0.084 25.392 0.137 25.416 ;
     RECT  0.06 25.416 0.137 25.488 ;
     RECT  0.084 25.488 0.137 25.512 ;
     RECT  0.06 25.512 0.137 25.584 ;
     RECT  0.084 25.584 0.137 25.608 ;
     RECT  0.06 25.608 0.137 25.68 ;
     RECT  0.084 25.68 0.137 25.704 ;
     RECT  0.06 25.704 0.137 25.776 ;
     RECT  0.084 25.776 0.137 25.8 ;
     RECT  0.06 25.8 0.137 25.872 ;
     RECT  0.084 25.872 0.137 25.896 ;
     RECT  0.06 25.896 0.137 25.968 ;
     RECT  0.084 25.968 0.137 25.992 ;
     RECT  0.06 25.992 0.137 26.064 ;
     RECT  0.084 26.064 0.137 26.088 ;
     RECT  0.06 26.088 0.137 26.16 ;
     RECT  0.084 26.16 0.137 26.184 ;
     RECT  0.06 26.184 0.137 26.256 ;
     RECT  0.084 26.256 0.137 26.28 ;
     RECT  0.06 26.28 0.137 26.352 ;
     RECT  0.084 26.352 0.137 26.376 ;
     RECT  0.06 26.376 0.137 26.448 ;
     RECT  0.084 26.448 0.137 26.472 ;
     RECT  0.06 26.472 0.137 26.544 ;
     RECT  0.084 26.544 0.137 26.568 ;
     RECT  0.06 26.568 0.137 26.64 ;
     RECT  0.084 26.64 0.137 26.664 ;
     RECT  0.06 26.664 0.137 26.736 ;
     RECT  0.084 26.736 0.137 26.76 ;
     RECT  0.06 26.76 0.137 26.832 ;
     RECT  0.084 26.832 0.137 26.856 ;
     RECT  0.06 26.856 0.137 26.928 ;
     RECT  0.084 26.928 0.137 26.952 ;
     RECT  0.06 26.952 0.137 27.024 ;
     RECT  0.084 27.024 0.137 27.048 ;
     RECT  0.06 27.048 0.137 27.12 ;
     RECT  0.084 27.12 0.137 27.144 ;
     RECT  0.06 27.144 0.137 27.216 ;
     RECT  0.084 27.216 0.137 27.24 ;
     RECT  0.06 27.24 0.137 27.312 ;
     RECT  0.084 27.312 0.137 27.336 ;
     RECT  0.06 27.336 0.137 27.408 ;
     RECT  0.084 27.408 0.137 27.432 ;
     RECT  0.06 27.432 0.137 27.504 ;
     RECT  0.084 27.504 0.137 27.528 ;
     RECT  0.06 27.528 0.137 27.6 ;
     RECT  0.084 27.6 0.137 27.624 ;
     RECT  0.06 27.624 0.137 27.696 ;
     RECT  0.084 27.696 0.137 27.72 ;
     RECT  0.06 27.72 0.137 27.792 ;
     RECT  0.084 27.792 0.137 27.816 ;
     RECT  0.06 27.816 0.137 27.888 ;
     RECT  0.084 27.888 0.137 27.912 ;
     RECT  0.06 27.912 0.137 27.984 ;
     RECT  0.084 27.984 0.137 28.008 ;
     RECT  0.06 28.008 0.137 28.848 ;
     RECT  0.084 28.848 0.137 28.872 ;
     RECT  0.06 28.872 0.137 28.944 ;
     RECT  0.084 28.944 0.137 28.968 ;
     RECT  0.06 28.968 0.137 29.04 ;
     RECT  0.084 29.04 0.137 29.064 ;
     RECT  0.06 29.064 0.137 29.136 ;
     RECT  0.084 29.136 0.137 29.16 ;
     RECT  0.06 29.16 0.137 29.232 ;
     RECT  0.084 29.232 0.137 29.256 ;
     RECT  0.06 29.256 0.137 29.328 ;
     RECT  0.084 29.328 0.137 29.352 ;
     RECT  0.06 29.352 0.137 29.424 ;
     RECT  0.084 29.424 0.137 29.448 ;
     RECT  0.06 29.448 0.137 29.52 ;
     RECT  0.084 29.52 0.137 29.544 ;
     RECT  0.06 29.544 0.137 29.616 ;
     RECT  0.084 29.616 0.137 29.64 ;
     RECT  0.06 29.64 0.137 29.712 ;
     RECT  0.084 29.712 0.137 29.736 ;
     RECT  0.06 29.736 0.137 29.808 ;
     RECT  0.084 29.808 0.137 29.832 ;
     RECT  0.06 29.832 0.137 29.904 ;
     RECT  0.084 29.904 0.137 29.928 ;
     RECT  0.06 29.928 0.137 30 ;
     RECT  0.084 30 0.137 30.024 ;
     RECT  0.06 30.024 0.137 30.096 ;
     RECT  0.084 30.096 0.137 30.12 ;
     RECT  0.06 30.12 0.137 30.192 ;
     RECT  0.084 30.192 0.137 30.216 ;
     RECT  0.06 30.216 0.137 30.288 ;
     RECT  0.084 30.288 0.137 30.312 ;
     RECT  0.06 30.312 0.137 30.384 ;
     RECT  0.084 30.384 0.137 30.408 ;
     RECT  0.06 30.408 0.137 30.48 ;
     RECT  0.084 30.48 0.137 30.504 ;
     RECT  0.06 30.504 0.137 30.576 ;
     RECT  0.084 30.576 0.137 30.6 ;
     RECT  0.06 30.6 0.137 30.672 ;
     RECT  0.084 30.672 0.137 30.696 ;
     RECT  0.06 30.696 0.137 30.768 ;
     RECT  0.084 30.768 0.137 30.792 ;
     RECT  0.06 30.792 0.137 30.864 ;
     RECT  0.084 30.864 0.137 30.888 ;
     RECT  0.06 30.888 0.137 30.96 ;
     RECT  0.084 30.96 0.137 30.984 ;
     RECT  0.06 30.984 0.137 31.056 ;
     RECT  0.084 31.056 0.137 31.08 ;
     RECT  0.06 31.08 0.137 31.152 ;
     RECT  0.084 31.152 0.137 31.176 ;
     RECT  0.06 31.176 0.137 31.248 ;
     RECT  0.084 31.248 0.137 31.272 ;
     RECT  0.06 31.272 0.137 31.344 ;
     RECT  0.084 31.344 0.137 31.368 ;
     RECT  0.06 31.368 0.137 31.44 ;
     RECT  0.084 31.44 0.137 31.464 ;
     RECT  0.06 31.464 0.137 31.536 ;
     RECT  0.084 31.536 0.137 31.56 ;
     RECT  0.06 31.56 0.137 31.632 ;
     RECT  0.084 31.632 0.137 31.656 ;
     RECT  0.06 31.656 0.137 31.728 ;
     RECT  0.084 31.728 0.137 31.752 ;
     RECT  0.06 31.752 0.137 31.824 ;
     RECT  0.084 31.824 0.137 31.848 ;
     RECT  0.06 31.848 0.137 31.92 ;
     RECT  0.084 31.92 0.137 31.944 ;
     RECT  0.06 31.944 0.137 32.016 ;
     RECT  0.084 32.016 0.137 32.04 ;
     RECT  0.06 32.04 0.137 32.112 ;
     RECT  0.084 32.112 0.137 32.136 ;
     RECT  0.06 32.136 0.137 32.208 ;
     RECT  0.084 32.208 0.137 32.232 ;
     RECT  0.06 32.232 0.137 32.304 ;
     RECT  0.084 32.304 0.137 32.328 ;
     RECT  0.06 32.328 0.137 32.4 ;
     RECT  0.084 32.4 0.137 32.424 ;
     RECT  0.06 32.424 0.137 32.496 ;
     RECT  0.084 32.496 0.137 32.52 ;
     RECT  0.06 32.52 0.137 32.592 ;
     RECT  0.084 32.592 0.137 32.616 ;
     RECT  0.06 32.616 0.137 32.688 ;
     RECT  0.084 32.688 0.137 32.712 ;
     RECT  0.06 32.712 0.137 32.784 ;
     RECT  0.084 32.784 0.137 32.808 ;
     RECT  0.06 32.808 0.137 32.88 ;
     RECT  0.084 32.88 0.137 32.904 ;
     RECT  0.06 32.904 0.137 32.976 ;
     RECT  0.084 32.976 0.137 33 ;
     RECT  0.06 33 0.137 33.072 ;
     RECT  0.084 33.072 0.137 33.096 ;
     RECT  0.06 33.096 0.137 33.168 ;
     RECT  0.084 33.168 0.137 33.192 ;
     RECT  0.06 33.192 0.137 33.264 ;
     RECT  0.084 33.264 0.137 33.288 ;
     RECT  0.06 33.288 0.137 33.36 ;
     RECT  0.084 33.36 0.137 33.384 ;
     RECT  0.06 33.384 0.137 33.456 ;
     RECT  0.084 33.456 0.137 33.48 ;
     RECT  0.06 33.48 0.137 33.552 ;
     RECT  0.084 33.552 0.137 33.576 ;
     RECT  0.06 33.576 0.137 33.648 ;
     RECT  0.084 33.648 0.137 33.672 ;
     RECT  0.06 33.672 0.137 33.744 ;
     RECT  0.084 33.744 0.137 33.768 ;
     RECT  0.06 33.768 0.137 33.84 ;
     RECT  0.084 33.84 0.137 33.864 ;
     RECT  0.06 33.864 0.137 33.936 ;
     RECT  0.084 33.936 0.137 33.96 ;
     RECT  0.06 33.96 0.137 34.032 ;
     RECT  0.084 34.032 0.137 34.056 ;
     RECT  0.06 34.056 0.137 34.128 ;
     RECT  0.084 34.128 0.137 34.152 ;
     RECT  0.06 34.152 0.137 34.224 ;
     RECT  0.084 34.224 0.137 34.248 ;
     RECT  0.06 34.248 0.137 34.32 ;
     RECT  0.084 34.32 0.137 34.344 ;
     RECT  0.06 34.344 0.137 34.416 ;
     RECT  0.084 34.416 0.137 34.44 ;
     RECT  0.06 34.44 0.137 34.512 ;
     RECT  0.084 34.512 0.137 34.536 ;
     RECT  0.06 34.536 0.137 34.608 ;
     RECT  0.084 34.608 0.137 34.632 ;
     RECT  0.06 34.632 0.137 34.704 ;
     RECT  0.084 34.704 0.137 34.728 ;
     RECT  0.06 34.728 0.137 34.8 ;
     RECT  0.084 34.8 0.137 34.824 ;
     RECT  0.06 34.824 0.137 34.896 ;
     RECT  0.084 34.896 0.137 34.92 ;
     RECT  0.137 15.792 0.173 34.824 ;
     RECT  0.084 48.048 0.173 48.072 ;
     RECT  0.06 48.072 0.173 48.144 ;
     RECT  0.084 48.144 0.173 48.168 ;
     RECT  0.06 48.168 0.173 48.24 ;
     RECT  0.084 48.24 0.173 48.264 ;
     RECT  0.06 48.264 0.173 48.336 ;
     RECT  0.084 48.336 0.173 48.36 ;
     RECT  0.06 48.36 0.173 48.432 ;
     RECT  0.084 48.432 0.173 48.456 ;
     RECT  0.06 48.456 0.173 48.528 ;
     RECT  0.084 48.528 0.173 48.552 ;
     RECT  0.06 48.552 0.173 48.624 ;
     RECT  0.084 48.624 0.173 48.648 ;
     RECT  0.06 48.648 0.173 48.72 ;
     RECT  0.084 48.72 0.173 48.744 ;
     RECT  0.06 48.744 0.173 48.816 ;
     RECT  0.084 48.816 0.173 48.84 ;
     RECT  0.06 48.84 0.173 48.912 ;
     RECT  0.084 48.912 0.173 48.936 ;
     RECT  0.06 48.936 0.173 49.008 ;
     RECT  0.084 49.008 0.173 49.032 ;
     RECT  0.06 49.032 0.173 49.104 ;
     RECT  0.084 49.104 0.173 49.128 ;
     RECT  0.06 49.128 0.173 49.2 ;
     RECT  0.084 49.2 0.173 49.224 ;
     RECT  0.06 49.224 0.173 49.296 ;
     RECT  0.084 49.296 0.173 49.32 ;
     RECT  0.06 49.32 0.173 49.392 ;
     RECT  0.084 49.392 0.173 49.416 ;
     RECT  0.06 49.416 0.173 49.488 ;
     RECT  0.084 49.488 0.173 49.512 ;
     RECT  0.06 49.512 0.173 49.584 ;
     RECT  0.084 49.584 0.173 49.608 ;
     RECT  0.06 49.608 0.173 49.68 ;
     RECT  0.084 49.68 0.173 49.704 ;
     RECT  0.06 49.704 0.173 49.776 ;
     RECT  0.084 49.776 0.173 49.8 ;
     RECT  0.06 49.8 0.173 49.872 ;
     RECT  0.084 49.872 0.173 49.896 ;
     RECT  0.06 49.896 0.173 49.968 ;
     RECT  0.084 49.968 0.173 49.992 ;
     RECT  0.06 49.992 0.173 50.064 ;
     RECT  0.084 50.064 0.173 50.088 ;
     RECT  0.06 50.088 0.173 50.16 ;
     RECT  0.084 50.16 0.173 50.184 ;
     RECT  0.06 50.184 0.173 50.256 ;
     RECT  0.084 50.256 0.173 50.28 ;
     RECT  0.06 50.28 0.173 50.352 ;
     RECT  0.084 50.352 0.173 50.376 ;
     RECT  0.06 50.376 0.173 50.448 ;
     RECT  0.084 50.448 0.173 50.472 ;
     RECT  0.06 50.472 0.173 50.544 ;
     RECT  0.084 50.544 0.173 50.568 ;
     RECT  0.06 50.568 0.173 50.64 ;
     RECT  0.084 50.64 0.173 50.664 ;
     RECT  0.06 50.664 0.173 50.736 ;
     RECT  0.084 50.736 0.173 50.76 ;
     RECT  0.06 50.76 0.173 50.832 ;
     RECT  0.084 50.832 0.173 50.856 ;
     RECT  0.06 50.856 0.173 50.928 ;
     RECT  0.084 50.928 0.173 50.952 ;
     RECT  0.06 50.952 0.173 51.024 ;
     RECT  0.084 51.024 0.173 51.048 ;
     RECT  0.06 51.048 0.173 51.12 ;
     RECT  0.084 51.12 0.173 51.144 ;
     RECT  0.06 51.144 0.173 51.216 ;
     RECT  0.084 51.216 0.173 51.24 ;
     RECT  0.06 51.24 0.173 51.312 ;
     RECT  0.084 51.312 0.173 51.336 ;
     RECT  0.06 51.336 0.173 51.408 ;
     RECT  0.084 51.408 0.173 51.432 ;
     RECT  0.06 51.432 0.173 51.504 ;
     RECT  0.084 51.504 0.173 51.528 ;
     RECT  0.06 51.528 0.173 51.6 ;
     RECT  0.084 51.6 0.173 51.624 ;
     RECT  0.06 51.624 0.173 51.696 ;
     RECT  0.084 51.696 0.173 51.72 ;
     RECT  0.06 51.72 0.173 51.792 ;
     RECT  0.084 51.792 0.173 51.816 ;
     RECT  0.06 51.816 0.173 51.888 ;
     RECT  0.084 51.888 0.173 51.912 ;
     RECT  0.06 51.912 0.173 51.984 ;
     RECT  0.084 51.984 0.173 52.008 ;
     RECT  0.06 52.008 0.173 52.08 ;
     RECT  0.084 52.08 0.173 52.104 ;
     RECT  0.06 52.104 0.173 52.176 ;
     RECT  0.084 52.176 0.173 52.2 ;
     RECT  0.06 52.2 0.173 52.272 ;
     RECT  0.084 52.272 0.173 52.296 ;
     RECT  0.06 52.296 0.173 52.368 ;
     RECT  0.084 52.368 0.173 52.392 ;
     RECT  0.06 52.392 0.173 52.464 ;
     RECT  0.084 52.464 0.173 52.488 ;
     RECT  0.06 52.488 0.173 52.56 ;
     RECT  0.084 52.56 0.173 52.584 ;
     RECT  0.06 52.584 0.173 52.656 ;
     RECT  0.084 52.656 0.173 52.68 ;
     RECT  0.06 52.68 0.173 52.752 ;
     RECT  0.084 52.752 0.173 52.776 ;
     RECT  0.06 52.776 0.173 52.848 ;
     RECT  0.084 52.848 0.173 52.872 ;
     RECT  0.06 52.872 0.173 52.944 ;
     RECT  0.084 52.944 0.173 52.968 ;
     RECT  0.06 52.968 0.173 53.04 ;
     RECT  0.084 53.04 0.173 53.064 ;
     RECT  0.06 53.064 0.173 53.136 ;
     RECT  0.084 53.136 0.173 53.16 ;
     RECT  0.06 53.16 0.173 53.232 ;
     RECT  0.084 53.232 0.173 53.256 ;
     RECT  0.06 53.256 0.173 53.328 ;
     RECT  0.084 53.328 0.173 53.352 ;
     RECT  0.06 53.352 0.173 53.424 ;
     RECT  0.084 53.424 0.173 53.448 ;
     RECT  0.06 53.448 0.173 53.52 ;
     RECT  0.084 53.52 0.173 53.544 ;
     RECT  0.06 53.544 0.173 53.616 ;
     RECT  0.084 53.616 0.173 53.64 ;
     RECT  0.06 53.64 0.173 53.712 ;
     RECT  0.084 53.712 0.173 53.736 ;
     RECT  0.06 53.736 0.173 53.808 ;
     RECT  0.084 53.808 0.173 53.832 ;
     RECT  0.06 53.832 0.173 53.904 ;
     RECT  0.084 53.904 0.173 53.928 ;
     RECT  0.06 53.928 0.173 54 ;
     RECT  0.084 54 0.173 54.024 ;
     RECT  0.06 54.024 0.173 54.096 ;
     RECT  0.084 54.096 0.173 54.12 ;
     RECT  0.06 54.12 0.173 54.192 ;
     RECT  0.084 54.192 0.173 54.216 ;
     RECT  0.06 54.216 0.173 54.288 ;
     RECT  0.084 54.288 0.173 54.312 ;
     RECT  0.06 54.312 0.173 54.384 ;
     RECT  0.084 54.384 0.173 54.408 ;
     RECT  0.06 54.408 0.173 54.48 ;
     RECT  0.084 54.48 0.173 54.504 ;
     RECT  0.06 54.504 0.173 54.576 ;
     RECT  0.084 54.576 0.173 54.6 ;
     RECT  0.06 54.6 0.173 54.672 ;
     RECT  0.084 54.672 0.173 54.696 ;
     RECT  0.06 54.696 0.173 54.768 ;
     RECT  0.084 54.768 0.173 54.792 ;
     RECT  0.06 54.792 0.173 54.864 ;
     RECT  0.084 54.864 0.173 54.888 ;
     RECT  0.06 54.888 0.173 54.96 ;
     RECT  0.084 54.96 0.173 54.984 ;
     RECT  0.06 54.984 0.173 55.056 ;
     RECT  0.084 55.056 0.173 55.08 ;
     RECT  0.06 55.08 0.173 55.152 ;
     RECT  0.084 55.152 0.173 55.176 ;
     RECT  0.06 55.176 0.173 55.248 ;
     RECT  0.084 55.248 0.173 55.272 ;
     RECT  0.06 55.272 0.173 55.344 ;
     RECT  0.084 55.344 0.173 55.368 ;
     RECT  0.06 55.368 0.173 55.44 ;
     RECT  0.084 55.44 0.173 55.464 ;
     RECT  0.06 55.464 0.173 55.536 ;
     RECT  0.084 55.536 0.173 55.56 ;
     RECT  0.06 55.56 0.173 55.632 ;
     RECT  0.084 55.632 0.173 55.656 ;
     RECT  0.06 55.656 0.173 55.728 ;
     RECT  0.084 55.728 0.173 55.752 ;
     RECT  0.06 55.752 0.173 55.824 ;
     RECT  0.084 55.824 0.173 55.848 ;
     RECT  0.06 55.848 0.173 55.92 ;
     RECT  0.084 55.92 0.173 55.944 ;
     RECT  0.06 55.944 0.173 56.016 ;
     RECT  0.084 56.016 0.173 56.04 ;
     RECT  0.06 56.04 0.173 56.112 ;
     RECT  0.084 56.112 0.173 56.136 ;
     RECT  0.06 56.136 0.173 56.208 ;
     RECT  0.084 56.208 0.173 56.232 ;
     RECT  0.06 56.232 0.173 56.304 ;
     RECT  0.084 56.304 0.173 56.328 ;
     RECT  0.06 56.328 0.173 56.4 ;
     RECT  0.084 56.4 0.173 56.424 ;
     RECT  0.06 56.424 0.173 56.496 ;
     RECT  0.084 56.496 0.173 56.52 ;
     RECT  0.06 56.52 0.173 56.592 ;
     RECT  0.084 56.592 0.173 56.616 ;
     RECT  0.06 56.616 0.173 56.688 ;
     RECT  0.084 56.688 0.173 56.712 ;
     RECT  0.06 56.712 0.173 56.784 ;
     RECT  0.084 56.784 0.173 56.808 ;
     RECT  0.06 56.808 0.173 56.88 ;
     RECT  0.084 56.88 0.173 56.904 ;
     RECT  0.06 56.904 0.173 56.976 ;
     RECT  0.084 56.976 0.173 57 ;
     RECT  0.06 57 0.173 57.072 ;
     RECT  0.084 57.072 0.173 57.096 ;
     RECT  0.06 57.096 0.173 57.168 ;
     RECT  0.084 57.168 0.173 57.192 ;
     RECT  0.06 57.192 0.173 57.264 ;
     RECT  0.084 57.264 0.173 57.288 ;
     RECT  0.06 57.288 0.173 57.36 ;
     RECT  0.084 57.36 0.173 57.384 ;
     RECT  0.06 57.384 0.173 57.456 ;
     RECT  0.084 57.456 0.173 57.48 ;
     RECT  0.06 57.48 0.173 57.552 ;
     RECT  0.084 57.552 0.173 57.576 ;
     RECT  0.06 57.576 0.173 57.648 ;
     RECT  0.084 57.648 0.173 57.672 ;
     RECT  0.06 57.672 0.173 57.744 ;
     RECT  0.084 57.744 0.173 57.768 ;
     RECT  0.06 57.768 0.173 57.84 ;
     RECT  0.084 57.84 0.173 57.864 ;
     RECT  0.06 57.864 0.173 57.936 ;
     RECT  0.084 57.936 0.173 57.96 ;
     RECT  0.06 57.96 0.173 58.032 ;
     RECT  0.084 58.032 0.173 58.056 ;
     RECT  0.06 58.056 0.173 58.128 ;
     RECT  0.084 58.128 0.173 58.152 ;
     RECT  0.06 58.152 0.173 58.224 ;
     RECT  0.084 58.224 0.173 58.248 ;
     RECT  0.06 58.248 0.173 58.32 ;
     RECT  0.084 58.32 0.173 58.344 ;
     RECT  0.06 58.344 0.173 58.416 ;
     RECT  0.084 58.416 0.173 58.44 ;
     RECT  0.06 58.44 0.173 58.512 ;
     RECT  0.084 58.512 0.173 58.536 ;
     RECT  0.06 58.536 0.173 58.608 ;
     RECT  0.084 58.608 0.173 58.632 ;
     RECT  0.06 58.632 0.173 58.704 ;
     RECT  0.084 58.704 0.173 58.728 ;
     RECT  0.06 58.728 0.173 58.8 ;
     RECT  0.084 58.8 0.173 58.824 ;
     RECT  0.06 58.824 0.173 58.896 ;
     RECT  0.084 58.896 0.173 58.92 ;
     RECT  0.06 58.92 0.173 58.992 ;
     RECT  0.084 58.992 0.173 59.016 ;
     RECT  0.06 59.016 0.173 59.088 ;
     RECT  0.084 59.088 0.173 59.112 ;
     RECT  0.06 59.112 0.173 59.184 ;
     RECT  0.084 59.184 0.173 59.208 ;
     RECT  0.06 59.208 0.173 59.28 ;
     RECT  0.084 59.28 0.173 59.304 ;
     RECT  0.06 59.304 0.173 59.376 ;
     RECT  0.084 59.376 0.173 59.4 ;
     RECT  0.06 59.4 0.173 59.472 ;
     RECT  0.084 59.472 0.173 59.496 ;
     RECT  0.06 59.496 0.173 59.568 ;
     RECT  0.084 59.568 0.173 59.592 ;
     RECT  0.06 59.592 0.173 59.664 ;
     RECT  0.084 59.664 0.173 59.688 ;
     RECT  0.06 59.688 0.173 59.76 ;
     RECT  0.084 59.76 0.173 59.784 ;
     RECT  0.06 59.784 0.173 59.856 ;
     RECT  0.084 59.856 0.173 59.88 ;
     RECT  0.06 59.88 0.173 59.952 ;
     RECT  0.084 59.952 0.173 59.976 ;
     RECT  0.06 59.976 0.173 60.048 ;
     RECT  0.084 60.048 0.173 60.072 ;
     RECT  0.06 60.072 0.173 60.144 ;
     RECT  0.084 60.144 0.173 60.168 ;
     RECT  0.06 60.168 0.173 60.24 ;
     RECT  0.084 60.24 0.173 60.264 ;
     RECT  0.173 15.792 0.209 34.728 ;
     RECT  0.209 15.888 0.569 34.728 ;
     RECT  0.097 36.336 0.569 37.992 ;
     RECT  0.569 15.984 2.408 34.728 ;
     RECT  0.569 36.336 2.408 37.896 ;
     RECT  0.173 48.144 2.408 60.264 ;
     RECT  2.408 2.148 2.512 84.252 ;
     RECT  2.512 2.418 2.704 83.982 ;
     RECT  2.704 15.984 2.981 35.304 ;
     RECT  2.704 48.096 3.305 60.072 ;
     RECT  2.704 36.336 3.557 38.76 ;
     RECT  2.981 15.984 3.593 16.632 ;
     RECT  3.305 48.144 3.697 60.072 ;
     RECT  3.697 48.144 3.845 60.312 ;
     RECT  3.557 36.336 3.917 36.36 ;
     RECT  3.593 16.08 3.953 16.632 ;
     RECT  2.981 17.616 3.953 35.304 ;
     RECT  3.953 16.32 3.985 16.632 ;
     RECT  3.953 17.616 3.985 18.456 ;
     RECT  3.557 37.392 3.989 38.76 ;
     RECT  3.953 19.632 4.061 35.304 ;
     RECT  3.845 49.008 4.133 60.312 ;
     RECT  4.133 49.344 4.169 60.312 ;
     RECT  4.061 27.84 4.237 35.304 ;
     RECT  3.985 16.32 4.277 18.456 ;
     RECT  3.989 37.392 4.385 38.472 ;
     RECT  4.169 49.824 4.421 60.312 ;
     RECT  4.421 49.824 5.141 59.304 ;
     RECT  5.141 59.088 5.177 59.304 ;
     RECT  4.237 27.84 5.209 35.88 ;
     RECT  5.141 49.824 5.209 58.104 ;
     RECT  4.277 16.32 5.317 18.408 ;
     RECT  5.317 16.32 5.353 18.552 ;
     RECT  4.061 19.728 5.353 26.856 ;
     RECT  5.209 27.84 5.429 36.84 ;
     RECT  5.353 16.32 5.465 26.856 ;
     RECT  5.209 49.536 5.465 58.104 ;
     RECT  5.101 48.432 5.573 48.456 ;
     RECT  5.465 49.536 5.609 55.608 ;
     RECT  5.429 31.344 5.699 36.84 ;
     RECT  5.429 27.84 5.817 30.216 ;
     RECT  5.465 16.512 5.861 26.856 ;
     RECT  5.699 31.344 5.897 35.304 ;
     RECT  5.861 25.152 5.933 26.856 ;
     RECT  4.385 37.824 6.041 38.472 ;
     RECT  5.699 36.432 6.113 36.84 ;
     RECT  5.817 27.84 6.149 29.352 ;
     RECT  5.933 25.152 6.221 26.472 ;
     RECT  5.609 49.536 6.221 54.6 ;
     RECT  4.421 60.288 6.221 60.312 ;
     RECT  5.897 31.344 6.257 35.064 ;
     RECT  5.177 59.184 6.275 59.304 ;
     RECT  6.221 25.152 6.293 25.512 ;
     RECT  5.465 56.64 6.329 58.104 ;
     RECT  5.609 55.584 6.505 55.608 ;
     RECT  6.329 56.64 6.505 57.576 ;
     RECT  6.221 49.536 6.517 53.784 ;
     RECT  6.517 49.344 6.541 53.784 ;
     RECT  6.113 36.432 6.563 36.456 ;
     RECT  6.541 49.056 6.563 53.784 ;
     RECT  6.517 43.632 6.565 43.656 ;
     RECT  6.293 25.152 6.581 25.416 ;
     RECT  6.563 49.056 6.625 50.568 ;
     RECT  6.563 51.6 6.653 53.784 ;
     RECT  6.505 55.584 6.721 57.576 ;
     RECT  5.861 16.512 6.829 24.12 ;
     RECT  6.581 25.152 6.829 25.176 ;
     RECT  6.149 27.84 6.833 27.864 ;
     RECT  6.257 33.024 6.973 35.064 ;
     RECT  7.1 27.792 7.117 27.816 ;
     RECT  6.149 29.328 7.141 29.352 ;
     RECT  6.973 33.024 7.34 35.208 ;
     RECT  7.333 36.672 7.381 36.696 ;
     RECT  6.041 38.448 7.381 38.472 ;
     RECT  6.721 55.296 7.405 57.576 ;
     RECT  6.361 58.56 7.405 58.68 ;
     RECT  6.793 60.384 7.549 60.408 ;
     RECT  6.829 16.128 7.669 25.176 ;
     RECT  7.669 15.792 7.808 25.176 ;
     RECT  7.117 27.168 7.808 27.816 ;
     RECT  7.141 29.328 7.808 29.544 ;
     RECT  6.865 30.576 7.808 30.6 ;
     RECT  6.257 31.728 7.808 31.752 ;
     RECT  7.34 33.024 7.808 35.64 ;
     RECT  7.381 36.672 7.808 38.472 ;
     RECT  6.565 43.632 7.808 43.752 ;
     RECT  6.625 50.016 7.808 50.568 ;
     RECT  6.653 52.32 7.808 53.784 ;
     RECT  7.405 55.296 7.808 58.68 ;
     RECT  7.549 59.712 7.808 60.408 ;
     RECT  7.808 2.148 7.912 84.252 ;
     RECT  7.912 2.418 8.104 83.982 ;
     RECT  8.104 17.376 8.165 24.36 ;
     RECT  8.104 52.32 8.165 53.592 ;
     RECT  8.104 29.328 8.237 29.544 ;
     RECT  8.104 32.736 8.243 35.016 ;
     RECT  8.104 55.824 8.273 57.144 ;
     RECT  8.104 58.128 8.309 58.632 ;
     RECT  8.104 27.168 8.381 27.192 ;
     RECT  8.165 53.52 8.417 53.592 ;
     RECT  8.273 56.544 8.417 57.144 ;
     RECT  8.243 32.736 8.453 34.968 ;
     RECT  8.417 56.784 8.453 57.144 ;
     RECT  8.104 60.384 8.453 60.408 ;
     RECT  8.453 57.12 8.489 57.144 ;
     RECT  8.309 58.176 8.561 58.632 ;
     RECT  8.417 53.52 8.597 53.544 ;
     RECT  8.104 48.624 8.705 48.648 ;
     RECT  8.561 58.608 9.101 58.632 ;
     RECT  8.165 17.376 9.133 20.52 ;
     RECT  8.165 21.504 9.133 24.36 ;
     RECT  8.165 52.32 9.137 52.344 ;
     RECT  8.104 50.016 9.353 50.04 ;
     RECT  9.133 17.376 9.425 24.36 ;
     RECT  8.453 33.888 9.425 34.968 ;
     RECT  8.104 15.696 9.601 16.152 ;
     RECT  9.425 17.376 9.601 20.856 ;
     RECT  9.425 21.936 9.637 24.36 ;
     RECT  9.601 15.696 10.037 20.856 ;
     RECT  10.037 17.472 10.073 20.856 ;
     RECT  8.453 32.736 10.217 32.76 ;
     RECT  10.073 17.76 10.649 20.856 ;
     RECT  9.425 33.888 10.789 34.104 ;
     RECT  9.637 21.936 10.909 24.456 ;
     RECT  10.649 19.104 12.373 20.856 ;
     RECT  12.841 25.44 12.985 25.464 ;
     RECT  8.104 43.632 13.129 43.656 ;
     RECT  10.037 15.696 13.208 15.72 ;
     RECT  12.373 19.104 13.208 21.528 ;
     RECT  10.909 22.512 13.208 24.456 ;
     RECT  12.985 25.44 13.208 25.56 ;
     RECT  8.237 29.328 13.208 29.352 ;
     RECT  8.104 31.104 13.208 31.128 ;
     RECT  10.789 33.792 13.208 34.104 ;
     RECT  10.837 38.208 13.208 38.232 ;
     RECT  13.129 43.344 13.208 43.656 ;
     RECT  10.573 48.24 13.208 48.264 ;
     RECT  13.208 2.148 13.312 84.252 ;
     RECT  13.312 2.418 13.504 83.982 ;
     RECT  13.504 43.344 13.781 43.656 ;
     RECT  13.504 22.512 13.817 25.56 ;
     RECT  13.781 43.344 13.955 43.368 ;
     RECT  13.504 31.104 14.177 31.944 ;
     RECT  13.504 26.736 14.641 26.76 ;
     RECT  13.504 29.328 14.749 29.352 ;
     RECT  13.817 22.512 14.821 24.792 ;
     RECT  14.641 25.872 14.821 26.76 ;
     RECT  14.177 31.104 15.356 31.128 ;
     RECT  13.504 33.792 15.397 34.104 ;
     RECT  15.397 33.648 15.443 34.104 ;
     RECT  14.821 22.512 15.509 26.76 ;
     RECT  15.509 22.512 15.587 26.376 ;
     RECT  15.356 31.104 15.587 31.848 ;
     RECT  14.749 29.328 16.297 29.928 ;
     RECT  15.587 22.512 16.549 25.752 ;
     RECT  16.297 29.04 16.805 29.928 ;
     RECT  16.549 22.512 17.417 26.136 ;
     RECT  13.504 15.696 18.608 15.72 ;
     RECT  13.504 19.104 18.608 21.528 ;
     RECT  17.417 22.512 18.608 24.456 ;
     RECT  17.417 25.536 18.608 26.136 ;
     RECT  16.805 29.328 18.608 29.928 ;
     RECT  15.587 31.104 18.608 31.128 ;
     RECT  15.443 33.648 18.608 33.816 ;
     RECT  13.504 37.968 18.608 38.232 ;
     RECT  13.504 48.24 18.608 48.264 ;
     RECT  18.608 2.148 18.712 84.252 ;
     RECT  18.712 2.418 18.904 83.982 ;
     RECT  18.904 37.968 18.965 37.992 ;
     RECT  18.904 19.104 20.293 25.56 ;
     RECT  20.293 19.104 20.509 26.088 ;
     RECT  20.221 27.216 20.509 27.24 ;
     RECT  20.509 19.104 20.761 27.24 ;
     RECT  20.761 19.104 21.125 27.336 ;
     RECT  22.813 58.656 22.925 58.68 ;
     RECT  21.125 19.104 23.173 20.856 ;
     RECT  21.125 22.512 23.708 27.336 ;
     RECT  18.904 33.648 23.845 33.816 ;
     RECT  18.904 15.696 24.008 15.72 ;
     RECT  23.173 19.104 24.008 21.528 ;
     RECT  23.708 22.512 24.008 27.48 ;
     RECT  18.904 29.328 24.008 29.928 ;
     RECT  18.904 31.104 24.008 31.128 ;
     RECT  23.845 33.648 24.008 34.104 ;
     RECT  18.904 48.24 24.008 48.264 ;
     RECT  23.749 58.704 24.008 59.016 ;
     RECT  24.008 2.148 24.112 84.252 ;
     RECT  24.112 2.418 24.304 83.982 ;
     RECT  24.304 25.68 24.617 27.48 ;
     RECT  24.617 25.728 24.725 27.48 ;
     RECT  24.725 26.064 24.761 27.48 ;
     RECT  24.304 58.992 24.833 59.016 ;
     RECT  24.761 26.064 25.229 27.432 ;
     RECT  25.229 26.064 25.733 27.192 ;
     RECT  25.733 26.064 25.805 27.144 ;
     RECT  25.805 26.256 25.841 27.144 ;
     RECT  25.945 58.8 26.741 58.824 ;
     RECT  25.841 27.12 27.965 27.144 ;
     RECT  24.304 15.696 29.408 15.72 ;
     RECT  24.304 19.104 29.408 24.36 ;
     RECT  24.304 29.328 29.408 29.928 ;
     RECT  24.304 31.104 29.408 31.128 ;
     RECT  26.341 32.208 29.408 32.232 ;
     RECT  24.304 33.792 29.408 34.104 ;
     RECT  24.304 48.24 29.408 48.264 ;
     RECT  25.657 52.992 29.408 53.016 ;
     RECT  29.408 2.148 29.512 84.252 ;
     RECT  29.512 2.418 29.704 83.982 ;
     RECT  29.704 33.792 30.809 34.104 ;
     RECT  29.704 19.104 31.961 24.36 ;
     RECT  29.704 29.328 32.533 29.928 ;
     RECT  29.704 31.104 32.533 31.128 ;
     RECT  31.129 27.312 32.579 27.336 ;
     RECT  30.809 33.888 32.641 34.104 ;
     RECT  32.641 33.648 32.897 34.104 ;
     RECT  31.961 22.32 33.037 24.36 ;
     RECT  29.704 32.208 33.059 32.232 ;
     RECT  32.897 33.648 33.059 33.912 ;
     RECT  32.497 35.424 33.637 35.448 ;
     RECT  33.397 36.864 33.637 36.888 ;
     RECT  33.637 35.424 33.683 36.888 ;
     RECT  31.961 19.104 33.973 20.856 ;
     RECT  33.059 33.888 34.045 33.912 ;
     RECT  29.704 15.696 34.808 15.72 ;
     RECT  33.973 19.104 34.808 21.144 ;
     RECT  33.037 22.272 34.808 24.36 ;
     RECT  32.533 29.328 34.808 31.128 ;
     RECT  34.045 33.888 34.808 34.392 ;
     RECT  33.683 35.424 34.808 36.072 ;
     RECT  29.704 48.24 34.808 48.264 ;
     RECT  34.189 49.872 34.808 49.896 ;
     RECT  29.704 52.992 34.808 53.016 ;
     RECT  29.704 59.568 34.808 59.592 ;
     RECT  34.808 2.148 34.912 84.252 ;
     RECT  34.912 2.418 35.104 83.982 ;
     RECT  35.104 33.792 35.201 33.912 ;
     RECT  35.104 35.424 35.273 35.448 ;
     RECT  35.104 56.784 36.493 56.808 ;
     RECT  35.104 49.872 37.033 49.896 ;
     RECT  35.104 50.88 37.033 50.904 ;
     RECT  35.104 29.328 37.073 29.928 ;
     RECT  35.104 19.104 37.253 20.952 ;
     RECT  37.253 19.104 37.573 20.568 ;
     RECT  37.573 19.008 37.657 20.568 ;
     RECT  35.201 33.792 38.149 33.816 ;
     RECT  35.104 15.696 38.761 15.72 ;
     RECT  35.104 22.272 38.761 24.36 ;
     RECT  38.149 33.792 38.761 34.68 ;
     RECT  38.761 33.648 38.797 34.68 ;
     RECT  38.761 15.696 38.801 15.816 ;
     RECT  38.401 36.24 38.801 36.264 ;
     RECT  38.797 33.12 38.905 34.68 ;
     RECT  38.905 33.024 39.049 34.68 ;
     RECT  39.049 32.496 39.085 34.68 ;
     RECT  35.104 48.24 39.157 48.264 ;
     RECT  35.104 55.68 39.157 55.704 ;
     RECT  36.493 56.784 39.157 56.856 ;
     RECT  39.085 32.496 39.161 34.728 ;
     RECT  37.073 29.328 39.265 29.832 ;
     RECT  38.761 61.44 39.589 61.464 ;
     RECT  39.157 48.24 39.661 48.792 ;
     RECT  37.033 49.872 39.661 50.904 ;
     RECT  38.761 22.224 39.697 24.36 ;
     RECT  39.265 28.704 39.733 29.832 ;
     RECT  39.733 28.704 39.769 29.88 ;
     RECT  35.104 52.992 39.841 53.016 ;
     RECT  35.104 54.192 39.841 54.216 ;
     RECT  39.841 52.992 39.913 54.216 ;
     RECT  39.157 55.68 39.949 56.856 ;
     RECT  35.104 59.568 39.985 59.592 ;
     RECT  39.769 28.704 40.021 30.072 ;
     RECT  35.104 31.104 40.021 31.128 ;
     RECT  39.161 32.592 40.057 34.728 ;
     RECT  39.949 55.68 40.057 57.72 ;
     RECT  40.057 32.592 40.093 34.776 ;
     RECT  39.661 48.24 40.093 50.904 ;
     RECT  39.697 22.224 40.165 25.128 ;
     RECT  40.129 43.536 40.165 43.56 ;
     RECT  40.165 43.536 40.201 43.848 ;
     RECT  38.801 15.792 40.208 15.816 ;
     RECT  37.657 19.008 40.208 20.184 ;
     RECT  40.165 22.224 40.208 25.752 ;
     RECT  40.021 28.704 40.208 31.128 ;
     RECT  40.093 32.592 40.208 34.968 ;
     RECT  40.201 37.968 40.208 37.992 ;
     RECT  39.661 40.272 40.208 40.296 ;
     RECT  39.841 41.376 40.208 41.4 ;
     RECT  40.201 43.536 40.208 43.944 ;
     RECT  40.093 47.328 40.208 50.904 ;
     RECT  39.913 52.704 40.208 54.216 ;
     RECT  40.057 55.68 40.208 58.2 ;
     RECT  39.985 59.52 40.208 59.592 ;
     RECT  39.589 61.152 40.208 61.464 ;
     RECT  40.208 2.148 40.312 84.252 ;
     RECT  40.312 2.418 40.504 83.982 ;
     RECT  40.504 39.12 40.601 41.4 ;
     RECT  40.504 37.968 40.673 37.992 ;
     RECT  40.504 28.464 40.853 35.256 ;
     RECT  40.601 39.12 40.853 39.144 ;
     RECT  40.853 28.704 40.925 35.256 ;
     RECT  40.601 40.128 40.925 41.4 ;
     RECT  40.925 31.104 41.069 35.256 ;
     RECT  40.504 43.056 41.321 44.76 ;
     RECT  40.504 25.248 41.533 26.04 ;
     RECT  40.504 19.008 41.605 20.184 ;
     RECT  41.069 33.648 41.605 35.256 ;
     RECT  40.925 40.608 41.605 41.4 ;
     RECT  40.504 46.752 41.605 59.64 ;
     RECT  40.504 60.672 41.605 61.464 ;
     RECT  40.504 15.792 41.645 15.816 ;
     RECT  40.504 22.224 41.795 24.216 ;
     RECT  41.605 46.752 41.857 61.464 ;
     RECT  40.925 28.704 42.145 29.832 ;
     RECT  42.109 37.824 42.145 38.232 ;
     RECT  41.605 19.008 42.181 21 ;
     RECT  41.605 33.648 42.217 35.448 ;
     RECT  42.181 19.008 42.517 21.048 ;
     RECT  42.145 37.536 42.685 38.232 ;
     RECT  41.605 40.608 42.721 41.592 ;
     RECT  41.857 46.752 42.829 61.656 ;
     RECT  42.685 37.536 43.009 38.328 ;
     RECT  42.421 15.216 43.045 15.24 ;
     RECT  43.045 15.216 43.187 15.96 ;
     RECT  41.795 22.272 43.2 24.216 ;
     RECT  41.533 25.248 43.2 26.328 ;
     RECT  42.145 28.32 43.2 29.832 ;
     RECT  41.069 31.104 43.2 32.472 ;
     RECT  42.217 33.648 43.2 35.544 ;
     RECT  43.009 37.536 43.2 38.76 ;
     RECT  42.721 40.608 43.2 41.688 ;
     RECT  41.321 43.68 43.2 44.76 ;
     RECT  42.829 46.752 43.2 61.752 ;
     RECT  42.517 18.144 43.272 21.048 ;
     RECT  43.2 22.272 43.272 61.752 ;
     RECT  43.187 15.216 45.608 15.24 ;
     RECT  43.272 18.144 45.608 62.664 ;
     RECT  45.608 2.148 45.712 62.664 ;
     RECT  45.608 64.788 45.712 84.252 ;
     RECT  45.712 2.418 45.904 62.664 ;
     RECT  45.712 65.058 45.904 83.982 ;
     RECT  45.904 15.216 51.008 15.24 ;
     RECT  45.904 18.144 51.008 62.664 ;
     RECT  51.008 2.148 51.112 62.664 ;
     RECT  51.008 64.788 51.112 84.252 ;
     RECT  51.112 2.418 51.304 62.664 ;
     RECT  51.112 65.058 51.304 83.982 ;
     RECT  54.565 14.112 56.408 14.136 ;
     RECT  51.304 15.216 56.408 15.24 ;
     RECT  51.304 18.144 56.408 62.664 ;
     RECT  56.408 2.148 56.512 62.664 ;
     RECT  56.408 64.788 56.512 84.252 ;
     RECT  56.512 2.418 56.704 62.664 ;
     RECT  56.512 65.058 56.704 83.982 ;
     RECT  56.704 14.112 60.037 14.136 ;
     RECT  60.037 13.632 61.669 14.136 ;
     RECT  61.669 13.632 61.808 14.232 ;
     RECT  56.704 15.216 61.808 15.24 ;
     RECT  56.704 17.472 61.808 62.664 ;
     RECT  61.808 2.148 61.912 62.664 ;
     RECT  61.808 64.788 61.912 84.252 ;
     RECT  61.912 2.418 62.104 62.664 ;
     RECT  61.912 65.058 62.104 83.982 ;
     RECT  62.104 17.472 64.897 62.664 ;
     RECT  62.104 13.536 67.208 14.232 ;
     RECT  62.104 15.216 67.208 15.24 ;
     RECT  64.897 17.424 67.208 62.664 ;
     RECT  67.208 2.148 67.312 62.664 ;
     RECT  67.208 64.788 67.312 84.252 ;
     RECT  67.312 2.418 67.504 62.664 ;
     RECT  67.312 65.058 67.504 83.982 ;
     RECT  67.504 13.536 72.608 14.232 ;
     RECT  67.504 15.216 72.608 15.24 ;
     RECT  67.504 17.424 72.608 62.664 ;
     RECT  72.608 2.148 72.712 62.664 ;
     RECT  72.608 64.788 72.712 84.252 ;
     RECT  72.712 2.418 72.904 62.664 ;
     RECT  72.712 65.058 72.904 83.982 ;
     RECT  72.904 15.216 75.049 15.24 ;
     RECT  72.904 13.536 78.008 14.232 ;
     RECT  75.049 15.216 78.008 15.864 ;
     RECT  72.904 17.424 78.008 62.664 ;
     RECT  78.008 2.148 78.112 62.664 ;
     RECT  78.008 64.788 78.112 84.252 ;
     RECT  78.112 2.418 78.304 62.664 ;
     RECT  78.112 65.058 78.304 83.982 ;
     RECT  78.304 17.424 79.765 62.664 ;
     RECT  78.304 13.536 81.169 14.232 ;
     RECT  78.304 15.216 81.169 15.864 ;
     RECT  79.765 17.376 81.421 62.664 ;
     RECT  81.421 17.184 81.493 62.664 ;
     RECT  81.169 13.536 82.069 15.864 ;
     RECT  81.493 16.944 82.069 62.664 ;
     RECT  82.069 13.536 82.645 62.664 ;
     RECT  82.645 13.392 83.408 62.664 ;
     RECT  83.408 2.148 83.512 62.664 ;
     RECT  83.408 64.788 83.512 84.252 ;
     RECT  83.512 2.418 83.704 62.664 ;
     RECT  83.512 65.058 83.704 83.982 ;
     RECT  83.704 13.392 86.033 62.664 ;
     RECT  86.033 13.632 87.109 62.664 ;
     RECT  87.109 13.392 88.808 62.664 ;
     RECT  88.808 2.148 88.912 62.664 ;
     RECT  88.808 64.788 88.912 84.252 ;
     RECT  88.912 2.418 89.104 62.664 ;
     RECT  88.912 65.058 89.104 83.982 ;
     RECT  89.104 13.392 90.641 62.664 ;
     RECT  90.641 13.536 94.208 62.664 ;
     RECT  94.208 2.148 94.312 62.664 ;
     RECT  94.208 64.788 94.312 84.252 ;
     RECT  94.312 2.418 94.504 62.664 ;
     RECT  94.312 65.058 94.504 83.982 ;
     RECT  94.504 13.536 99.608 62.664 ;
     RECT  99.608 2.148 99.712 62.664 ;
     RECT  99.608 64.788 99.712 84.252 ;
     RECT  99.712 2.418 99.904 62.664 ;
     RECT  99.712 65.058 99.904 83.982 ;
     RECT  99.904 13.536 105.008 62.664 ;
     RECT  105.008 2.148 105.112 62.664 ;
     RECT  105.008 64.788 105.112 84.252 ;
     RECT  105.112 2.418 105.304 62.664 ;
     RECT  105.112 65.058 105.304 83.982 ;
     RECT  105.304 13.536 110.408 62.664 ;
     RECT  110.408 2.148 110.512 62.664 ;
     RECT  110.408 64.788 110.512 84.252 ;
     RECT  110.512 2.418 110.704 62.664 ;
     RECT  110.512 65.058 110.704 83.982 ;
     RECT  110.704 13.536 115.808 62.664 ;
     RECT  115.808 2.148 115.912 62.664 ;
     RECT  115.808 64.788 115.912 84.252 ;
     RECT  115.912 2.418 116.104 62.664 ;
     RECT  115.912 65.058 116.104 83.982 ;
     RECT  116.104 13.536 121.208 62.664 ;
     RECT  121.208 2.148 121.312 62.664 ;
     RECT  121.208 64.788 121.312 84.252 ;
     RECT  121.312 2.418 121.504 62.664 ;
     RECT  121.312 65.058 121.504 83.982 ;
     RECT  121.504 13.536 126.608 62.664 ;
     RECT  126.608 2.148 126.712 62.664 ;
     RECT  126.608 64.788 126.712 84.252 ;
     RECT  126.712 2.418 126.904 62.664 ;
     RECT  126.712 65.058 126.904 83.982 ;
     RECT  126.904 13.536 132.008 62.664 ;
     RECT  132.008 2.148 132.112 62.664 ;
     RECT  132.008 64.788 132.112 84.252 ;
     RECT  132.112 2.418 132.304 62.664 ;
     RECT  132.112 65.058 132.304 83.982 ;
     RECT  132.304 13.536 137.408 62.664 ;
     RECT  137.408 2.148 137.512 62.664 ;
     RECT  137.408 64.788 137.512 84.252 ;
     RECT  137.512 2.418 137.704 62.664 ;
     RECT  137.512 65.058 137.704 83.982 ;
     RECT  137.704 13.536 142.808 62.664 ;
     RECT  142.808 2.148 142.912 62.664 ;
     RECT  142.808 64.788 142.912 84.252 ;
     RECT  142.912 2.418 143.104 62.664 ;
     RECT  142.912 65.058 143.104 83.982 ;
     RECT  143.104 13.536 148.208 62.664 ;
     RECT  148.208 2.148 148.312 62.664 ;
     RECT  148.208 64.788 148.312 84.252 ;
     RECT  148.312 2.418 148.504 62.664 ;
     RECT  148.312 65.058 148.504 83.982 ;
     RECT  148.504 13.536 153.608 62.664 ;
     RECT  153.608 2.148 153.712 62.664 ;
     RECT  153.608 64.788 153.712 84.252 ;
     RECT  153.712 2.418 153.904 62.664 ;
     RECT  153.712 65.058 153.904 83.982 ;
     RECT  153.904 13.536 159.008 62.664 ;
     RECT  159.008 2.148 159.112 62.664 ;
     RECT  159.008 64.788 159.112 84.252 ;
     RECT  159.112 2.418 159.304 62.664 ;
     RECT  159.112 65.058 159.304 83.982 ;
     RECT  159.304 13.536 164.408 62.664 ;
     RECT  164.408 2.148 164.512 62.664 ;
     RECT  164.408 64.788 164.512 84.252 ;
     RECT  164.512 2.418 164.704 62.664 ;
     RECT  164.512 65.058 164.704 83.982 ;
     RECT  164.704 13.536 169.808 62.664 ;
     RECT  169.808 2.148 169.912 62.664 ;
     RECT  169.808 64.788 169.912 84.252 ;
     RECT  169.912 2.418 170.104 62.664 ;
     RECT  169.912 65.058 170.104 83.982 ;
     RECT  170.104 13.536 175.208 62.664 ;
     RECT  175.208 2.148 175.312 62.664 ;
     RECT  175.208 64.788 175.312 84.252 ;
     RECT  175.312 2.418 175.504 62.664 ;
     RECT  175.312 65.058 175.504 83.982 ;
     RECT  175.504 13.536 180.608 62.664 ;
     RECT  180.608 2.148 180.712 62.664 ;
     RECT  180.608 64.788 180.712 84.252 ;
     RECT  180.712 2.418 180.904 62.664 ;
     RECT  180.712 65.058 180.904 83.982 ;
     RECT  180.904 13.536 186.008 62.664 ;
     RECT  186.008 2.148 186.112 62.664 ;
     RECT  186.008 64.788 186.112 84.252 ;
     RECT  186.112 2.418 186.304 62.664 ;
     RECT  186.112 65.058 186.304 83.982 ;
     RECT  186.304 13.536 191.408 62.664 ;
     RECT  191.408 2.148 191.512 62.664 ;
     RECT  191.408 64.788 191.512 84.252 ;
     RECT  191.512 2.418 191.704 62.664 ;
     RECT  191.512 65.058 191.704 83.982 ;
     RECT  191.704 13.536 196.808 62.664 ;
     RECT  196.808 2.148 196.912 62.664 ;
     RECT  196.808 64.788 196.912 84.252 ;
     RECT  196.912 2.418 197.104 62.664 ;
     RECT  196.912 65.058 197.104 83.982 ;
     RECT  197.104 13.536 202.208 62.664 ;
     RECT  202.208 2.148 202.312 62.664 ;
     RECT  202.208 64.788 202.312 84.252 ;
     RECT  202.312 2.418 202.504 62.664 ;
     RECT  202.312 65.058 202.504 83.982 ;
     RECT  202.504 13.536 207.608 62.664 ;
     RECT  207.608 2.148 207.712 62.664 ;
     RECT  207.608 64.788 207.712 84.252 ;
     RECT  207.712 2.418 207.904 62.664 ;
     RECT  207.712 65.058 207.904 83.982 ;
     RECT  207.904 13.536 213.008 62.664 ;
     RECT  213.008 2.148 213.112 62.664 ;
     RECT  213.008 64.788 213.112 84.252 ;
     RECT  213.112 2.418 213.304 62.664 ;
     RECT  213.112 65.058 213.304 83.982 ;
     RECT  213.304 13.536 215.952 62.664 ;
     RECT  215.952 13.536 216.461 21 ;
     RECT  216.461 13.536 216.515 19.752 ;
     RECT  216.515 13.632 216.947 19.704 ;
     RECT  215.952 22.272 216.965 61.656 ;
     RECT  216.965 22.272 217.001 23.736 ;
     RECT  217.001 22.272 217.037 23.688 ;
     RECT  216.965 24.96 217.397 61.656 ;
     RECT  216.947 19.632 217.427 19.704 ;
     RECT  216.947 13.632 218.408 17.88 ;
     RECT  217.427 19.68 218.408 19.704 ;
     RECT  216.461 20.88 218.408 21 ;
     RECT  217.037 22.368 218.408 23.688 ;
     RECT  217.397 24.96 218.408 26.328 ;
     RECT  217.397 27.552 218.408 61.656 ;
     RECT  218.408 2.148 218.512 84.252 ;
     RECT  218.512 2.418 218.704 83.982 ;
     RECT  218.704 60 218.729 60.024 ;
     RECT  218.704 48.96 218.837 48.984 ;
     RECT  218.704 24.96 218.909 26.328 ;
     RECT  218.704 13.632 218.915 13.656 ;
     RECT  218.704 28.512 218.915 33.864 ;
     RECT  218.909 24.96 218.945 26.088 ;
     RECT  218.704 20.88 218.963 21 ;
     RECT  218.945 25.248 218.963 26.088 ;
     RECT  218.963 20.976 219.011 21 ;
     RECT  218.963 25.248 219.011 25.848 ;
     RECT  218.915 28.512 219.053 31.224 ;
     RECT  219.011 25.296 219.089 25.848 ;
     RECT  219.053 28.8 219.161 31.224 ;
     RECT  218.704 22.56 219.233 23.688 ;
     RECT  219.233 22.56 219.269 23.16 ;
     RECT  218.915 32.304 219.485 33.864 ;
     RECT  219.161 28.8 219.593 30.648 ;
     RECT  219.089 25.296 219.629 25.56 ;
     RECT  219.593 28.8 219.665 29.304 ;
     RECT  219.665 28.992 219.701 29.304 ;
     RECT  219.269 22.56 220.061 23.112 ;
     RECT  219.629 25.536 220.205 25.56 ;
     RECT  220.061 22.848 220.241 23.112 ;
     RECT  219.485 33.12 220.277 33.864 ;
     RECT  219.593 30.624 220.313 30.648 ;
     RECT  220.277 33.84 220.349 33.864 ;
     RECT  220.241 22.848 220.385 22.872 ;
     RECT  219.701 28.992 220.421 29.016 ;
     RECT  223.808 2.148 223.912 84.252 ;
     RECT  223.912 2.418 224.104 83.982 ;
     RECT  229.208 2.148 229.312 84.252 ;
     RECT  229.312 2.418 229.504 83.982 ;
     RECT  234.608 2.148 234.712 84.252 ;
     RECT  234.712 2.418 234.904 83.982 ;
    LAYER M5 ;
     RECT  2.4 2.137 2.52 2.151 ;
     RECT  7.8 2.137 7.92 2.151 ;
     RECT  13.2 2.137 13.32 2.151 ;
     RECT  18.6 2.137 18.72 2.151 ;
     RECT  24 2.137 24.12 2.151 ;
     RECT  29.4 2.137 29.52 2.151 ;
     RECT  34.8 2.137 34.92 2.151 ;
     RECT  40.2 2.137 40.32 2.151 ;
     RECT  45.6 2.137 45.72 2.151 ;
     RECT  51 2.137 51.12 2.151 ;
     RECT  56.4 2.137 56.52 2.151 ;
     RECT  61.8 2.137 61.92 2.151 ;
     RECT  67.2 2.137 67.32 2.151 ;
     RECT  72.6 2.137 72.72 2.151 ;
     RECT  78 2.137 78.12 2.151 ;
     RECT  83.4 2.137 83.52 2.151 ;
     RECT  88.8 2.137 88.92 2.151 ;
     RECT  94.2 2.137 94.32 2.151 ;
     RECT  99.6 2.137 99.72 2.151 ;
     RECT  105 2.137 105.12 2.151 ;
     RECT  110.4 2.137 110.52 2.151 ;
     RECT  115.8 2.137 115.92 2.151 ;
     RECT  121.2 2.137 121.32 2.151 ;
     RECT  126.6 2.137 126.72 2.151 ;
     RECT  132 2.137 132.12 2.151 ;
     RECT  137.4 2.137 137.52 2.151 ;
     RECT  142.8 2.137 142.92 2.151 ;
     RECT  148.2 2.137 148.32 2.151 ;
     RECT  153.6 2.137 153.72 2.151 ;
     RECT  159 2.137 159.12 2.151 ;
     RECT  164.4 2.137 164.52 2.151 ;
     RECT  169.8 2.137 169.92 2.151 ;
     RECT  175.2 2.137 175.32 2.151 ;
     RECT  180.6 2.137 180.72 2.151 ;
     RECT  186 2.137 186.12 2.151 ;
     RECT  191.4 2.137 191.52 2.151 ;
     RECT  196.8 2.137 196.92 2.151 ;
     RECT  202.2 2.137 202.32 2.151 ;
     RECT  207.6 2.137 207.72 2.151 ;
     RECT  213 2.137 213.12 2.151 ;
     RECT  218.4 2.137 218.52 2.151 ;
     RECT  223.8 2.137 223.92 2.151 ;
     RECT  229.2 2.137 229.32 2.151 ;
     RECT  234.6 2.137 234.72 2.151 ;
     RECT  218.4 2.151 218.712 13.621 ;
     RECT  216.48 13.525 216.504 14.101 ;
     RECT  78 2.151 78.312 14.149 ;
     RECT  216.24 14.101 216.504 14.149 ;
     RECT  61.8 2.151 62.112 14.197 ;
     RECT  216.24 14.149 216.648 14.197 ;
     RECT  216.24 14.197 217.032 14.341 ;
     RECT  218.4 13.621 218.904 14.341 ;
     RECT  83.4 2.151 83.712 14.389 ;
     RECT  7.8 2.151 8.112 15.781 ;
     RECT  42.432 15.205 42.456 15.925 ;
     RECT  216.24 14.341 218.904 17.461 ;
     RECT  216.048 17.461 218.904 17.603 ;
     RECT  2.4 2.151 2.712 18.181 ;
     RECT  82.512 14.389 83.712 18.275 ;
     RECT  216.24 17.603 218.904 18.757 ;
     RECT  42.432 15.925 43.176 18.805 ;
     RECT  54.576 14.101 54.6 18.851 ;
     RECT  60.048 13.621 60.072 18.851 ;
     RECT  61.68 14.197 62.112 18.851 ;
     RECT  78 14.149 79.224 18.851 ;
     RECT  42.432 18.805 43.272 19.091 ;
     RECT  42.432 19.091 43.128 19.141 ;
     RECT  7.68 15.781 8.112 19.189 ;
     RECT  41.76 19.141 43.128 19.189 ;
     RECT  34.8 2.151 35.112 19.285 ;
     RECT  2.4 18.181 2.904 19.763 ;
     RECT  37.584 18.997 37.608 20.579 ;
     RECT  216.096 18.757 218.904 20.869 ;
     RECT  41.664 19.189 43.128 20.965 ;
     RECT  216.096 20.869 218.952 20.965 ;
     RECT  6.864 19.189 8.112 21.155 ;
     RECT  34.176 19.285 35.112 21.155 ;
     RECT  7.68 21.155 8.112 21.683 ;
     RECT  41.616 20.965 43.128 22.403 ;
     RECT  5.376 17.077 5.4 22.789 ;
     RECT  5.376 22.789 6.216 23.027 ;
     RECT  41.616 22.403 42.6 23.315 ;
     RECT  13.2 2.151 13.512 24.469 ;
     RECT  15.936 23.413 15.96 24.947 ;
     RECT  5.376 23.027 5.4 25.141 ;
     RECT  216.096 20.965 219 25.283 ;
     RECT  24 2.151 24.312 25.525 ;
     RECT  13.2 24.469 13.608 25.571 ;
     RECT  22.368 23.893 22.392 25.669 ;
     RECT  22.176 25.669 22.392 25.715 ;
     RECT  5.376 25.141 5.592 25.717 ;
     RECT  4.704 25.717 5.592 25.763 ;
     RECT  216.096 25.283 218.952 26.099 ;
     RECT  22.176 25.715 22.2 26.819 ;
     RECT  23.856 25.525 24.312 27.109 ;
     RECT  23.76 27.109 24.312 27.491 ;
     RECT  7.8 21.683 8.112 27.781 ;
     RECT  216.096 26.099 218.904 28.835 ;
     RECT  40.2 2.151 40.512 28.933 ;
     RECT  40.08 28.933 40.512 29.173 ;
     RECT  42.432 23.315 42.6 29.363 ;
     RECT  0.144 29.269 0.168 29.555 ;
     RECT  7.152 27.781 8.112 29.555 ;
     RECT  39.984 29.173 40.512 29.603 ;
     RECT  42.432 29.363 42.552 29.843 ;
     RECT  2.4 19.763 2.712 30.037 ;
     RECT  2.304 30.037 2.712 30.227 ;
     RECT  5.76 29.221 5.784 30.227 ;
     RECT  32.544 27.301 32.568 30.565 ;
     RECT  32.544 30.565 32.76 30.611 ;
     RECT  32.736 30.611 32.76 30.853 ;
     RECT  32.736 30.853 33.048 30.899 ;
     RECT  42.48 29.843 42.552 31.139 ;
     RECT  0.144 31.477 0.168 31.763 ;
     RECT  15.552 26.341 15.576 31.813 ;
     RECT  15.408 31.813 15.576 31.859 ;
     RECT  13.2 25.571 13.512 31.909 ;
     RECT  216.192 28.835 218.904 32.003 ;
     RECT  216.192 32.003 218.712 32.099 ;
     RECT  216.192 32.099 217.416 32.387 ;
     RECT  216.192 32.387 216.984 32.867 ;
     RECT  216.192 32.867 216.408 32.963 ;
     RECT  216.192 32.963 216.216 33.059 ;
     RECT  218.4 32.099 218.712 33.349 ;
     RECT  218.304 33.349 218.712 33.539 ;
     RECT  33.024 30.899 33.048 33.683 ;
     RECT  42.48 31.139 42.504 33.683 ;
     RECT  7.8 29.555 8.112 34.021 ;
     RECT  15.408 31.859 15.432 34.115 ;
     RECT  23.856 27.491 24.312 34.115 ;
     RECT  4.704 25.763 4.728 34.355 ;
     RECT  7.8 34.021 8.232 34.981 ;
     RECT  7.392 34.981 8.232 35.027 ;
     RECT  5.664 35.269 5.688 35.891 ;
     RECT  7.392 35.027 8.112 36.421 ;
     RECT  33.648 35.413 33.672 36.899 ;
     RECT  0.144 37.717 0.168 37.907 ;
     RECT  13.2 31.909 14.136 37.957 ;
     RECT  13.2 37.957 14.232 38.099 ;
     RECT  10.848 21.925 10.872 38.243 ;
     RECT  6.528 36.421 8.112 38.483 ;
     RECT  13.2 38.099 13.944 43.379 ;
     RECT  6.528 38.483 6.552 43.621 ;
     RECT  7.8 38.483 8.112 43.621 ;
     RECT  6.528 43.621 8.112 43.667 ;
     RECT  6.576 43.667 8.112 43.763 ;
     RECT  6.576 43.763 6.6 49.091 ;
     RECT  2.4 30.227 2.712 50.053 ;
     RECT  6.528 49.333 6.552 51.061 ;
     RECT  5.952 51.061 6.552 51.107 ;
     RECT  2.4 50.053 3.288 51.635 ;
     RECT  0.144 53.365 0.168 53.555 ;
     RECT  0.144 54.709 0.168 54.899 ;
     RECT  7.8 43.763 8.112 55.813 ;
     RECT  0.144 56.053 0.168 56.339 ;
     RECT  7.8 55.813 8.232 56.531 ;
     RECT  2.4 51.635 2.712 56.629 ;
     RECT  5.952 51.107 5.976 57.301 ;
     RECT  5.952 57.301 6.264 57.347 ;
     RECT  2.4 56.629 3 57.541 ;
     RECT  0.144 58.741 0.168 59.027 ;
     RECT  6.24 57.347 6.264 59.315 ;
     RECT  2.4 57.541 3.384 59.459 ;
     RECT  2.4 59.459 2.712 84.249 ;
     RECT  7.8 56.531 8.112 84.249 ;
     RECT  13.2 43.379 13.512 84.249 ;
     RECT  18.6 2.151 18.912 84.249 ;
     RECT  24 34.115 24.312 84.249 ;
     RECT  29.4 2.151 29.712 84.249 ;
     RECT  34.8 21.155 35.112 84.249 ;
     RECT  40.2 29.603 40.512 84.249 ;
     RECT  45.6 2.151 45.912 84.249 ;
     RECT  51 2.151 51.312 84.249 ;
     RECT  56.4 2.151 56.712 84.249 ;
     RECT  61.8 18.851 62.112 84.249 ;
     RECT  67.2 2.151 67.512 84.249 ;
     RECT  72.6 2.151 72.912 84.249 ;
     RECT  78 18.851 78.312 84.249 ;
     RECT  83.4 18.275 83.712 84.249 ;
     RECT  88.8 2.151 89.112 84.249 ;
     RECT  94.2 2.151 94.512 84.249 ;
     RECT  99.6 2.151 99.912 84.249 ;
     RECT  105 2.151 105.312 84.249 ;
     RECT  110.4 2.151 110.712 84.249 ;
     RECT  115.8 2.151 116.112 84.249 ;
     RECT  121.2 2.151 121.512 84.249 ;
     RECT  126.6 2.151 126.912 84.249 ;
     RECT  132 2.151 132.312 84.249 ;
     RECT  137.4 2.151 137.712 84.249 ;
     RECT  142.8 2.151 143.112 84.249 ;
     RECT  148.2 2.151 148.512 84.249 ;
     RECT  153.6 2.151 153.912 84.249 ;
     RECT  159 2.151 159.312 84.249 ;
     RECT  164.4 2.151 164.712 84.249 ;
     RECT  169.8 2.151 170.112 84.249 ;
     RECT  175.2 2.151 175.512 84.249 ;
     RECT  180.6 2.151 180.912 84.249 ;
     RECT  186 2.151 186.312 84.249 ;
     RECT  191.4 2.151 191.712 84.249 ;
     RECT  196.8 2.151 197.112 84.249 ;
     RECT  202.2 2.151 202.512 84.249 ;
     RECT  207.6 2.151 207.912 84.249 ;
     RECT  213 2.151 213.312 84.249 ;
     RECT  218.4 33.539 218.712 84.249 ;
     RECT  223.8 2.151 224.112 84.249 ;
     RECT  229.2 2.151 229.512 84.249 ;
     RECT  234.6 2.151 234.912 84.249 ;
     RECT  2.4 84.249 2.52 84.263 ;
     RECT  7.8 84.249 7.92 84.263 ;
     RECT  13.2 84.249 13.32 84.263 ;
     RECT  18.6 84.249 18.72 84.263 ;
     RECT  24 84.249 24.12 84.263 ;
     RECT  29.4 84.249 29.52 84.263 ;
     RECT  34.8 84.249 34.92 84.263 ;
     RECT  40.2 84.249 40.32 84.263 ;
     RECT  45.6 84.249 45.72 84.263 ;
     RECT  51 84.249 51.12 84.263 ;
     RECT  56.4 84.249 56.52 84.263 ;
     RECT  61.8 84.249 61.92 84.263 ;
     RECT  67.2 84.249 67.32 84.263 ;
     RECT  72.6 84.249 72.72 84.263 ;
     RECT  78 84.249 78.12 84.263 ;
     RECT  83.4 84.249 83.52 84.263 ;
     RECT  88.8 84.249 88.92 84.263 ;
     RECT  94.2 84.249 94.32 84.263 ;
     RECT  99.6 84.249 99.72 84.263 ;
     RECT  105 84.249 105.12 84.263 ;
     RECT  110.4 84.249 110.52 84.263 ;
     RECT  115.8 84.249 115.92 84.263 ;
     RECT  121.2 84.249 121.32 84.263 ;
     RECT  126.6 84.249 126.72 84.263 ;
     RECT  132 84.249 132.12 84.263 ;
     RECT  137.4 84.249 137.52 84.263 ;
     RECT  142.8 84.249 142.92 84.263 ;
     RECT  148.2 84.249 148.32 84.263 ;
     RECT  153.6 84.249 153.72 84.263 ;
     RECT  159 84.249 159.12 84.263 ;
     RECT  164.4 84.249 164.52 84.263 ;
     RECT  169.8 84.249 169.92 84.263 ;
     RECT  175.2 84.249 175.32 84.263 ;
     RECT  180.6 84.249 180.72 84.263 ;
     RECT  186 84.249 186.12 84.263 ;
     RECT  191.4 84.249 191.52 84.263 ;
     RECT  196.8 84.249 196.92 84.263 ;
     RECT  202.2 84.249 202.32 84.263 ;
     RECT  207.6 84.249 207.72 84.263 ;
     RECT  213 84.249 213.12 84.263 ;
     RECT  218.4 84.249 218.52 84.263 ;
     RECT  223.8 84.249 223.92 84.263 ;
     RECT  229.2 84.249 229.32 84.263 ;
     RECT  234.6 84.249 234.72 84.263 ;
     RECT  217.032 14.197 218.4 14.341 ;
     RECT  216.096 17.603 216.24 18.757 ;
     RECT  40.512 19.141 41.76 19.189 ;
     RECT  5.4 19.189 6.864 21.155 ;
     RECT  40.512 19.189 41.664 20.965 ;
     RECT  40.512 20.965 41.616 23.315 ;
     RECT  22.392 25.525 23.856 25.715 ;
     RECT  23.76 25.715 23.856 27.109 ;
     RECT  4.728 29.221 5.76 30.227 ;
     RECT  5.784 29.221 7.152 29.555 ;
     RECT  14.136 31.909 15.408 34.115 ;
     RECT  217.416 32.099 218.4 32.387 ;
     RECT  216.984 32.387 218.4 32.867 ;
     RECT  218.304 32.867 218.4 33.349 ;
     RECT  33.672 35.413 34.8 36.899 ;
     RECT  6.552 38.483 7.8 43.621 ;
     RECT  6.6 43.763 7.8 49.091 ;
     RECT  6.576 49.091 7.8 49.333 ;
     RECT  6.552 49.333 7.8 51.107 ;
     RECT  0.144 53.555 0.168 54.709 ;
     RECT  0.144 54.899 0.168 56.053 ;
  END
END ot_hbm_idx_qctl_static
END LIBRARY
